VERSION 5.4 ;
NAMESCASESENSITIVE ON ;
BUSBITCHARS "[]" ;
DIVIDERCHAR "/" ;
UNITS
  DATABASE MICRONS 2000 ;
END UNITS
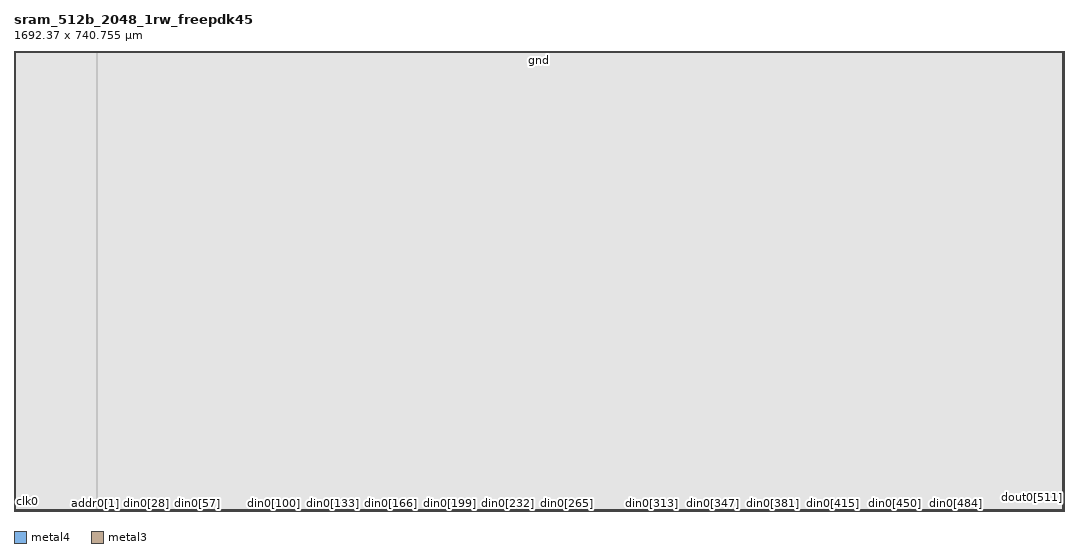
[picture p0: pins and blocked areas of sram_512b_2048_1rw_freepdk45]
MACRO sram_512b_2048_1rw_freepdk45
   CLASS BLOCK ;
   SIZE 1692.37 BY 740.755 ;
   SYMMETRY X Y R90 ;
   PIN din0[0]
      DIRECTION INPUT ;
      PORT
         LAYER metal4 ;
         RECT  133.4175 0.0 133.5575 0.14 ;
      END
   END din0[0]
   PIN din0[1]
      DIRECTION INPUT ;
      PORT
         LAYER metal4 ;
         RECT  136.2775 0.0 136.4175 0.14 ;
      END
   END din0[1]
   PIN din0[2]
      DIRECTION INPUT ;
      PORT
         LAYER metal4 ;
         RECT  139.1375 0.0 139.2775 0.14 ;
      END
   END din0[2]
   PIN din0[3]
      DIRECTION INPUT ;
      PORT
         LAYER metal4 ;
         RECT  141.9975 0.0 142.1375 0.14 ;
      END
   END din0[3]
   PIN din0[4]
      DIRECTION INPUT ;
      PORT
         LAYER metal4 ;
         RECT  144.8575 0.0 144.9975 0.14 ;
      END
   END din0[4]
   PIN din0[5]
      DIRECTION INPUT ;
      PORT
         LAYER metal4 ;
         RECT  147.7175 0.0 147.8575 0.14 ;
      END
   END din0[5]
   PIN din0[6]
      DIRECTION INPUT ;
      PORT
         LAYER metal4 ;
         RECT  150.5775 0.0 150.7175 0.14 ;
      END
   END din0[6]
   PIN din0[7]
      DIRECTION INPUT ;
      PORT
         LAYER metal4 ;
         RECT  153.4375 0.0 153.5775 0.14 ;
      END
   END din0[7]
   PIN din0[8]
      DIRECTION INPUT ;
      PORT
         LAYER metal4 ;
         RECT  156.2975 0.0 156.4375 0.14 ;
      END
   END din0[8]
   PIN din0[9]
      DIRECTION INPUT ;
      PORT
         LAYER metal4 ;
         RECT  159.1575 0.0 159.2975 0.14 ;
      END
   END din0[9]
   PIN din0[10]
      DIRECTION INPUT ;
      PORT
         LAYER metal4 ;
         RECT  162.0175 0.0 162.1575 0.14 ;
      END
   END din0[10]
   PIN din0[11]
      DIRECTION INPUT ;
      PORT
         LAYER metal4 ;
         RECT  164.8775 0.0 165.0175 0.14 ;
      END
   END din0[11]
   PIN din0[12]
      DIRECTION INPUT ;
      PORT
         LAYER metal4 ;
         RECT  167.7375 0.0 167.8775 0.14 ;
      END
   END din0[12]
   PIN din0[13]
      DIRECTION INPUT ;
      PORT
         LAYER metal4 ;
         RECT  170.5975 0.0 170.7375 0.14 ;
      END
   END din0[13]
   PIN din0[14]
      DIRECTION INPUT ;
      PORT
         LAYER metal4 ;
         RECT  173.4575 0.0 173.5975 0.14 ;
      END
   END din0[14]
   PIN din0[15]
      DIRECTION INPUT ;
      PORT
         LAYER metal4 ;
         RECT  176.3175 0.0 176.4575 0.14 ;
      END
   END din0[15]
   PIN din0[16]
      DIRECTION INPUT ;
      PORT
         LAYER metal4 ;
         RECT  179.1775 0.0 179.3175 0.14 ;
      END
   END din0[16]
   PIN din0[17]
      DIRECTION INPUT ;
      PORT
         LAYER metal4 ;
         RECT  182.0375 0.0 182.1775 0.14 ;
      END
   END din0[17]
   PIN din0[18]
      DIRECTION INPUT ;
      PORT
         LAYER metal4 ;
         RECT  184.8975 0.0 185.0375 0.14 ;
      END
   END din0[18]
   PIN din0[19]
      DIRECTION INPUT ;
      PORT
         LAYER metal4 ;
         RECT  187.7575 0.0 187.8975 0.14 ;
      END
   END din0[19]
   PIN din0[20]
      DIRECTION INPUT ;
      PORT
         LAYER metal4 ;
         RECT  190.6175 0.0 190.7575 0.14 ;
      END
   END din0[20]
   PIN din0[21]
      DIRECTION INPUT ;
      PORT
         LAYER metal4 ;
         RECT  193.4775 0.0 193.6175 0.14 ;
      END
   END din0[21]
   PIN din0[22]
      DIRECTION INPUT ;
      PORT
         LAYER metal4 ;
         RECT  196.3375 0.0 196.4775 0.14 ;
      END
   END din0[22]
   PIN din0[23]
      DIRECTION INPUT ;
      PORT
         LAYER metal4 ;
         RECT  199.1975 0.0 199.3375 0.14 ;
      END
   END din0[23]
   PIN din0[24]
      DIRECTION INPUT ;
      PORT
         LAYER metal4 ;
         RECT  202.0575 0.0 202.1975 0.14 ;
      END
   END din0[24]
   PIN din0[25]
      DIRECTION INPUT ;
      PORT
         LAYER metal4 ;
         RECT  204.9175 0.0 205.0575 0.14 ;
      END
   END din0[25]
   PIN din0[26]
      DIRECTION INPUT ;
      PORT
         LAYER metal4 ;
         RECT  207.7775 0.0 207.9175 0.14 ;
      END
   END din0[26]
   PIN din0[27]
      DIRECTION INPUT ;
      PORT
         LAYER metal4 ;
         RECT  210.6375 0.0 210.7775 0.14 ;
      END
   END din0[27]
   PIN din0[28]
      DIRECTION INPUT ;
      PORT
         LAYER metal4 ;
         RECT  213.4975 0.0 213.6375 0.14 ;
      END
   END din0[28]
   PIN din0[29]
      DIRECTION INPUT ;
      PORT
         LAYER metal4 ;
         RECT  216.3575 0.0 216.4975 0.14 ;
      END
   END din0[29]
   PIN din0[30]
      DIRECTION INPUT ;
      PORT
         LAYER metal4 ;
         RECT  219.2175 0.0 219.3575 0.14 ;
      END
   END din0[30]
   PIN din0[31]
      DIRECTION INPUT ;
      PORT
         LAYER metal4 ;
         RECT  222.0775 0.0 222.2175 0.14 ;
      END
   END din0[31]
   PIN din0[32]
      DIRECTION INPUT ;
      PORT
         LAYER metal4 ;
         RECT  224.9375 0.0 225.0775 0.14 ;
      END
   END din0[32]
   PIN din0[33]
      DIRECTION INPUT ;
      PORT
         LAYER metal4 ;
         RECT  227.7975 0.0 227.9375 0.14 ;
      END
   END din0[33]
   PIN din0[34]
      DIRECTION INPUT ;
      PORT
         LAYER metal4 ;
         RECT  230.6575 0.0 230.7975 0.14 ;
      END
   END din0[34]
   PIN din0[35]
      DIRECTION INPUT ;
      PORT
         LAYER metal4 ;
         RECT  233.5175 0.0 233.6575 0.14 ;
      END
   END din0[35]
   PIN din0[36]
      DIRECTION INPUT ;
      PORT
         LAYER metal4 ;
         RECT  236.3775 0.0 236.5175 0.14 ;
      END
   END din0[36]
   PIN din0[37]
      DIRECTION INPUT ;
      PORT
         LAYER metal4 ;
         RECT  239.2375 0.0 239.3775 0.14 ;
      END
   END din0[37]
   PIN din0[38]
      DIRECTION INPUT ;
      PORT
         LAYER metal4 ;
         RECT  242.0975 0.0 242.2375 0.14 ;
      END
   END din0[38]
   PIN din0[39]
      DIRECTION INPUT ;
      PORT
         LAYER metal4 ;
         RECT  244.9575 0.0 245.0975 0.14 ;
      END
   END din0[39]
   PIN din0[40]
      DIRECTION INPUT ;
      PORT
         LAYER metal4 ;
         RECT  247.8175 0.0 247.9575 0.14 ;
      END
   END din0[40]
   PIN din0[41]
      DIRECTION INPUT ;
      PORT
         LAYER metal4 ;
         RECT  250.6775 0.0 250.8175 0.14 ;
      END
   END din0[41]
   PIN din0[42]
      DIRECTION INPUT ;
      PORT
         LAYER metal4 ;
         RECT  253.5375 0.0 253.6775 0.14 ;
      END
   END din0[42]
   PIN din0[43]
      DIRECTION INPUT ;
      PORT
         LAYER metal4 ;
         RECT  256.3975 0.0 256.5375 0.14 ;
      END
   END din0[43]
   PIN din0[44]
      DIRECTION INPUT ;
      PORT
         LAYER metal4 ;
         RECT  259.2575 0.0 259.3975 0.14 ;
      END
   END din0[44]
   PIN din0[45]
      DIRECTION INPUT ;
      PORT
         LAYER metal4 ;
         RECT  262.1175 0.0 262.2575 0.14 ;
      END
   END din0[45]
   PIN din0[46]
      DIRECTION INPUT ;
      PORT
         LAYER metal4 ;
         RECT  264.9775 0.0 265.1175 0.14 ;
      END
   END din0[46]
   PIN din0[47]
      DIRECTION INPUT ;
      PORT
         LAYER metal4 ;
         RECT  267.8375 0.0 267.9775 0.14 ;
      END
   END din0[47]
   PIN din0[48]
      DIRECTION INPUT ;
      PORT
         LAYER metal4 ;
         RECT  270.6975 0.0 270.8375 0.14 ;
      END
   END din0[48]
   PIN din0[49]
      DIRECTION INPUT ;
      PORT
         LAYER metal4 ;
         RECT  273.5575 0.0 273.6975 0.14 ;
      END
   END din0[49]
   PIN din0[50]
      DIRECTION INPUT ;
      PORT
         LAYER metal4 ;
         RECT  276.4175 0.0 276.5575 0.14 ;
      END
   END din0[50]
   PIN din0[51]
      DIRECTION INPUT ;
      PORT
         LAYER metal4 ;
         RECT  279.2775 0.0 279.4175 0.14 ;
      END
   END din0[51]
   PIN din0[52]
      DIRECTION INPUT ;
      PORT
         LAYER metal4 ;
         RECT  282.1375 0.0 282.2775 0.14 ;
      END
   END din0[52]
   PIN din0[53]
      DIRECTION INPUT ;
      PORT
         LAYER metal4 ;
         RECT  284.9975 0.0 285.1375 0.14 ;
      END
   END din0[53]
   PIN din0[54]
      DIRECTION INPUT ;
      PORT
         LAYER metal4 ;
         RECT  287.8575 0.0 287.9975 0.14 ;
      END
   END din0[54]
   PIN din0[55]
      DIRECTION INPUT ;
      PORT
         LAYER metal4 ;
         RECT  290.7175 0.0 290.8575 0.14 ;
      END
   END din0[55]
   PIN din0[56]
      DIRECTION INPUT ;
      PORT
         LAYER metal4 ;
         RECT  293.5775 0.0 293.7175 0.14 ;
      END
   END din0[56]
   PIN din0[57]
      DIRECTION INPUT ;
      PORT
         LAYER metal4 ;
         RECT  296.4375 0.0 296.5775 0.14 ;
      END
   END din0[57]
   PIN din0[58]
      DIRECTION INPUT ;
      PORT
         LAYER metal4 ;
         RECT  299.2975 0.0 299.4375 0.14 ;
      END
   END din0[58]
   PIN din0[59]
      DIRECTION INPUT ;
      PORT
         LAYER metal4 ;
         RECT  302.1575 0.0 302.2975 0.14 ;
      END
   END din0[59]
   PIN din0[60]
      DIRECTION INPUT ;
      PORT
         LAYER metal4 ;
         RECT  305.0175 0.0 305.1575 0.14 ;
      END
   END din0[60]
   PIN din0[61]
      DIRECTION INPUT ;
      PORT
         LAYER metal4 ;
         RECT  307.8775 0.0 308.0175 0.14 ;
      END
   END din0[61]
   PIN din0[62]
      DIRECTION INPUT ;
      PORT
         LAYER metal4 ;
         RECT  310.7375 0.0 310.8775 0.14 ;
      END
   END din0[62]
   PIN din0[63]
      DIRECTION INPUT ;
      PORT
         LAYER metal4 ;
         RECT  313.5975 0.0 313.7375 0.14 ;
      END
   END din0[63]
   PIN din0[64]
      DIRECTION INPUT ;
      PORT
         LAYER metal4 ;
         RECT  316.4575 0.0 316.5975 0.14 ;
      END
   END din0[64]
   PIN din0[65]
      DIRECTION INPUT ;
      PORT
         LAYER metal4 ;
         RECT  319.3175 0.0 319.4575 0.14 ;
      END
   END din0[65]
   PIN din0[66]
      DIRECTION INPUT ;
      PORT
         LAYER metal4 ;
         RECT  322.1775 0.0 322.3175 0.14 ;
      END
   END din0[66]
   PIN din0[67]
      DIRECTION INPUT ;
      PORT
         LAYER metal4 ;
         RECT  325.0375 0.0 325.1775 0.14 ;
      END
   END din0[67]
   PIN din0[68]
      DIRECTION INPUT ;
      PORT
         LAYER metal4 ;
         RECT  327.8975 0.0 328.0375 0.14 ;
      END
   END din0[68]
   PIN din0[69]
      DIRECTION INPUT ;
      PORT
         LAYER metal4 ;
         RECT  330.7575 0.0 330.8975 0.14 ;
      END
   END din0[69]
   PIN din0[70]
      DIRECTION INPUT ;
      PORT
         LAYER metal4 ;
         RECT  333.6175 0.0 333.7575 0.14 ;
      END
   END din0[70]
   PIN din0[71]
      DIRECTION INPUT ;
      PORT
         LAYER metal4 ;
         RECT  336.4775 0.0 336.6175 0.14 ;
      END
   END din0[71]
   PIN din0[72]
      DIRECTION INPUT ;
      PORT
         LAYER metal4 ;
         RECT  339.3375 0.0 339.4775 0.14 ;
      END
   END din0[72]
   PIN din0[73]
      DIRECTION INPUT ;
      PORT
         LAYER metal4 ;
         RECT  342.1975 0.0 342.3375 0.14 ;
      END
   END din0[73]
   PIN din0[74]
      DIRECTION INPUT ;
      PORT
         LAYER metal4 ;
         RECT  345.0575 0.0 345.1975 0.14 ;
      END
   END din0[74]
   PIN din0[75]
      DIRECTION INPUT ;
      PORT
         LAYER metal4 ;
         RECT  347.9175 0.0 348.0575 0.14 ;
      END
   END din0[75]
   PIN din0[76]
      DIRECTION INPUT ;
      PORT
         LAYER metal4 ;
         RECT  350.7775 0.0 350.9175 0.14 ;
      END
   END din0[76]
   PIN din0[77]
      DIRECTION INPUT ;
      PORT
         LAYER metal4 ;
         RECT  353.6375 0.0 353.7775 0.14 ;
      END
   END din0[77]
   PIN din0[78]
      DIRECTION INPUT ;
      PORT
         LAYER metal4 ;
         RECT  356.4975 0.0 356.6375 0.14 ;
      END
   END din0[78]
   PIN din0[79]
      DIRECTION INPUT ;
      PORT
         LAYER metal4 ;
         RECT  359.3575 0.0 359.4975 0.14 ;
      END
   END din0[79]
   PIN din0[80]
      DIRECTION INPUT ;
      PORT
         LAYER metal4 ;
         RECT  362.2175 0.0 362.3575 0.14 ;
      END
   END din0[80]
   PIN din0[81]
      DIRECTION INPUT ;
      PORT
         LAYER metal4 ;
         RECT  365.0775 0.0 365.2175 0.14 ;
      END
   END din0[81]
   PIN din0[82]
      DIRECTION INPUT ;
      PORT
         LAYER metal4 ;
         RECT  367.9375 0.0 368.0775 0.14 ;
      END
   END din0[82]
   PIN din0[83]
      DIRECTION INPUT ;
      PORT
         LAYER metal4 ;
         RECT  370.7975 0.0 370.9375 0.14 ;
      END
   END din0[83]
   PIN din0[84]
      DIRECTION INPUT ;
      PORT
         LAYER metal4 ;
         RECT  373.6575 0.0 373.7975 0.14 ;
      END
   END din0[84]
   PIN din0[85]
      DIRECTION INPUT ;
      PORT
         LAYER metal4 ;
         RECT  376.5175 0.0 376.6575 0.14 ;
      END
   END din0[85]
   PIN din0[86]
      DIRECTION INPUT ;
      PORT
         LAYER metal4 ;
         RECT  379.3775 0.0 379.5175 0.14 ;
      END
   END din0[86]
   PIN din0[87]
      DIRECTION INPUT ;
      PORT
         LAYER metal4 ;
         RECT  382.2375 0.0 382.3775 0.14 ;
      END
   END din0[87]
   PIN din0[88]
      DIRECTION INPUT ;
      PORT
         LAYER metal4 ;
         RECT  385.0975 0.0 385.2375 0.14 ;
      END
   END din0[88]
   PIN din0[89]
      DIRECTION INPUT ;
      PORT
         LAYER metal4 ;
         RECT  387.9575 0.0 388.0975 0.14 ;
      END
   END din0[89]
   PIN din0[90]
      DIRECTION INPUT ;
      PORT
         LAYER metal4 ;
         RECT  390.8175 0.0 390.9575 0.14 ;
      END
   END din0[90]
   PIN din0[91]
      DIRECTION INPUT ;
      PORT
         LAYER metal4 ;
         RECT  393.6775 0.0 393.8175 0.14 ;
      END
   END din0[91]
   PIN din0[92]
      DIRECTION INPUT ;
      PORT
         LAYER metal4 ;
         RECT  396.5375 0.0 396.6775 0.14 ;
      END
   END din0[92]
   PIN din0[93]
      DIRECTION INPUT ;
      PORT
         LAYER metal4 ;
         RECT  399.3975 0.0 399.5375 0.14 ;
      END
   END din0[93]
   PIN din0[94]
      DIRECTION INPUT ;
      PORT
         LAYER metal4 ;
         RECT  402.2575 0.0 402.3975 0.14 ;
      END
   END din0[94]
   PIN din0[95]
      DIRECTION INPUT ;
      PORT
         LAYER metal4 ;
         RECT  405.1175 0.0 405.2575 0.14 ;
      END
   END din0[95]
   PIN din0[96]
      DIRECTION INPUT ;
      PORT
         LAYER metal4 ;
         RECT  407.9775 0.0 408.1175 0.14 ;
      END
   END din0[96]
   PIN din0[97]
      DIRECTION INPUT ;
      PORT
         LAYER metal4 ;
         RECT  410.8375 0.0 410.9775 0.14 ;
      END
   END din0[97]
   PIN din0[98]
      DIRECTION INPUT ;
      PORT
         LAYER metal4 ;
         RECT  413.6975 0.0 413.8375 0.14 ;
      END
   END din0[98]
   PIN din0[99]
      DIRECTION INPUT ;
      PORT
         LAYER metal4 ;
         RECT  416.5575 0.0 416.6975 0.14 ;
      END
   END din0[99]
   PIN din0[100]
      DIRECTION INPUT ;
      PORT
         LAYER metal4 ;
         RECT  419.4175 0.0 419.5575 0.14 ;
      END
   END din0[100]
   PIN din0[101]
      DIRECTION INPUT ;
      PORT
         LAYER metal4 ;
         RECT  422.2775 0.0 422.4175 0.14 ;
      END
   END din0[101]
   PIN din0[102]
      DIRECTION INPUT ;
      PORT
         LAYER metal4 ;
         RECT  425.1375 0.0 425.2775 0.14 ;
      END
   END din0[102]
   PIN din0[103]
      DIRECTION INPUT ;
      PORT
         LAYER metal4 ;
         RECT  427.9975 0.0 428.1375 0.14 ;
      END
   END din0[103]
   PIN din0[104]
      DIRECTION INPUT ;
      PORT
         LAYER metal4 ;
         RECT  430.8575 0.0 430.9975 0.14 ;
      END
   END din0[104]
   PIN din0[105]
      DIRECTION INPUT ;
      PORT
         LAYER metal4 ;
         RECT  433.7175 0.0 433.8575 0.14 ;
      END
   END din0[105]
   PIN din0[106]
      DIRECTION INPUT ;
      PORT
         LAYER metal4 ;
         RECT  436.5775 0.0 436.7175 0.14 ;
      END
   END din0[106]
   PIN din0[107]
      DIRECTION INPUT ;
      PORT
         LAYER metal4 ;
         RECT  439.4375 0.0 439.5775 0.14 ;
      END
   END din0[107]
   PIN din0[108]
      DIRECTION INPUT ;
      PORT
         LAYER metal4 ;
         RECT  442.2975 0.0 442.4375 0.14 ;
      END
   END din0[108]
   PIN din0[109]
      DIRECTION INPUT ;
      PORT
         LAYER metal4 ;
         RECT  445.1575 0.0 445.2975 0.14 ;
      END
   END din0[109]
   PIN din0[110]
      DIRECTION INPUT ;
      PORT
         LAYER metal4 ;
         RECT  448.0175 0.0 448.1575 0.14 ;
      END
   END din0[110]
   PIN din0[111]
      DIRECTION INPUT ;
      PORT
         LAYER metal4 ;
         RECT  450.8775 0.0 451.0175 0.14 ;
      END
   END din0[111]
   PIN din0[112]
      DIRECTION INPUT ;
      PORT
         LAYER metal4 ;
         RECT  453.7375 0.0 453.8775 0.14 ;
      END
   END din0[112]
   PIN din0[113]
      DIRECTION INPUT ;
      PORT
         LAYER metal4 ;
         RECT  456.5975 0.0 456.7375 0.14 ;
      END
   END din0[113]
   PIN din0[114]
      DIRECTION INPUT ;
      PORT
         LAYER metal4 ;
         RECT  459.4575 0.0 459.5975 0.14 ;
      END
   END din0[114]
   PIN din0[115]
      DIRECTION INPUT ;
      PORT
         LAYER metal4 ;
         RECT  462.3175 0.0 462.4575 0.14 ;
      END
   END din0[115]
   PIN din0[116]
      DIRECTION INPUT ;
      PORT
         LAYER metal4 ;
         RECT  465.1775 0.0 465.3175 0.14 ;
      END
   END din0[116]
   PIN din0[117]
      DIRECTION INPUT ;
      PORT
         LAYER metal4 ;
         RECT  468.0375 0.0 468.1775 0.14 ;
      END
   END din0[117]
   PIN din0[118]
      DIRECTION INPUT ;
      PORT
         LAYER metal4 ;
         RECT  470.8975 0.0 471.0375 0.14 ;
      END
   END din0[118]
   PIN din0[119]
      DIRECTION INPUT ;
      PORT
         LAYER metal4 ;
         RECT  473.7575 0.0 473.8975 0.14 ;
      END
   END din0[119]
   PIN din0[120]
      DIRECTION INPUT ;
      PORT
         LAYER metal4 ;
         RECT  476.6175 0.0 476.7575 0.14 ;
      END
   END din0[120]
   PIN din0[121]
      DIRECTION INPUT ;
      PORT
         LAYER metal4 ;
         RECT  479.4775 0.0 479.6175 0.14 ;
      END
   END din0[121]
   PIN din0[122]
      DIRECTION INPUT ;
      PORT
         LAYER metal4 ;
         RECT  482.3375 0.0 482.4775 0.14 ;
      END
   END din0[122]
   PIN din0[123]
      DIRECTION INPUT ;
      PORT
         LAYER metal4 ;
         RECT  485.1975 0.0 485.3375 0.14 ;
      END
   END din0[123]
   PIN din0[124]
      DIRECTION INPUT ;
      PORT
         LAYER metal4 ;
         RECT  488.0575 0.0 488.1975 0.14 ;
      END
   END din0[124]
   PIN din0[125]
      DIRECTION INPUT ;
      PORT
         LAYER metal4 ;
         RECT  490.9175 0.0 491.0575 0.14 ;
      END
   END din0[125]
   PIN din0[126]
      DIRECTION INPUT ;
      PORT
         LAYER metal4 ;
         RECT  493.7775 0.0 493.9175 0.14 ;
      END
   END din0[126]
   PIN din0[127]
      DIRECTION INPUT ;
      PORT
         LAYER metal4 ;
         RECT  496.6375 0.0 496.7775 0.14 ;
      END
   END din0[127]
   PIN din0[128]
      DIRECTION INPUT ;
      PORT
         LAYER metal4 ;
         RECT  499.4975 0.0 499.6375 0.14 ;
      END
   END din0[128]
   PIN din0[129]
      DIRECTION INPUT ;
      PORT
         LAYER metal4 ;
         RECT  502.3575 0.0 502.4975 0.14 ;
      END
   END din0[129]
   PIN din0[130]
      DIRECTION INPUT ;
      PORT
         LAYER metal4 ;
         RECT  505.2175 0.0 505.3575 0.14 ;
      END
   END din0[130]
   PIN din0[131]
      DIRECTION INPUT ;
      PORT
         LAYER metal4 ;
         RECT  508.0775 0.0 508.2175 0.14 ;
      END
   END din0[131]
   PIN din0[132]
      DIRECTION INPUT ;
      PORT
         LAYER metal4 ;
         RECT  510.9375 0.0 511.0775 0.14 ;
      END
   END din0[132]
   PIN din0[133]
      DIRECTION INPUT ;
      PORT
         LAYER metal4 ;
         RECT  513.7975 0.0 513.9375 0.14 ;
      END
   END din0[133]
   PIN din0[134]
      DIRECTION INPUT ;
      PORT
         LAYER metal4 ;
         RECT  516.6575 0.0 516.7975 0.14 ;
      END
   END din0[134]
   PIN din0[135]
      DIRECTION INPUT ;
      PORT
         LAYER metal4 ;
         RECT  519.5175 0.0 519.6575 0.14 ;
      END
   END din0[135]
   PIN din0[136]
      DIRECTION INPUT ;
      PORT
         LAYER metal4 ;
         RECT  522.3775 0.0 522.5175 0.14 ;
      END
   END din0[136]
   PIN din0[137]
      DIRECTION INPUT ;
      PORT
         LAYER metal4 ;
         RECT  525.2375 0.0 525.3775 0.14 ;
      END
   END din0[137]
   PIN din0[138]
      DIRECTION INPUT ;
      PORT
         LAYER metal4 ;
         RECT  528.0975 0.0 528.2375 0.14 ;
      END
   END din0[138]
   PIN din0[139]
      DIRECTION INPUT ;
      PORT
         LAYER metal4 ;
         RECT  530.9575 0.0 531.0975 0.14 ;
      END
   END din0[139]
   PIN din0[140]
      DIRECTION INPUT ;
      PORT
         LAYER metal4 ;
         RECT  533.8175 0.0 533.9575 0.14 ;
      END
   END din0[140]
   PIN din0[141]
      DIRECTION INPUT ;
      PORT
         LAYER metal4 ;
         RECT  536.6775 0.0 536.8175 0.14 ;
      END
   END din0[141]
   PIN din0[142]
      DIRECTION INPUT ;
      PORT
         LAYER metal4 ;
         RECT  539.5375 0.0 539.6775 0.14 ;
      END
   END din0[142]
   PIN din0[143]
      DIRECTION INPUT ;
      PORT
         LAYER metal4 ;
         RECT  542.3975 0.0 542.5375 0.14 ;
      END
   END din0[143]
   PIN din0[144]
      DIRECTION INPUT ;
      PORT
         LAYER metal4 ;
         RECT  545.2575 0.0 545.3975 0.14 ;
      END
   END din0[144]
   PIN din0[145]
      DIRECTION INPUT ;
      PORT
         LAYER metal4 ;
         RECT  548.1175 0.0 548.2575 0.14 ;
      END
   END din0[145]
   PIN din0[146]
      DIRECTION INPUT ;
      PORT
         LAYER metal4 ;
         RECT  550.9775 0.0 551.1175 0.14 ;
      END
   END din0[146]
   PIN din0[147]
      DIRECTION INPUT ;
      PORT
         LAYER metal4 ;
         RECT  553.8375 0.0 553.9775 0.14 ;
      END
   END din0[147]
   PIN din0[148]
      DIRECTION INPUT ;
      PORT
         LAYER metal4 ;
         RECT  556.6975 0.0 556.8375 0.14 ;
      END
   END din0[148]
   PIN din0[149]
      DIRECTION INPUT ;
      PORT
         LAYER metal4 ;
         RECT  559.5575 0.0 559.6975 0.14 ;
      END
   END din0[149]
   PIN din0[150]
      DIRECTION INPUT ;
      PORT
         LAYER metal4 ;
         RECT  562.4175 0.0 562.5575 0.14 ;
      END
   END din0[150]
   PIN din0[151]
      DIRECTION INPUT ;
      PORT
         LAYER metal4 ;
         RECT  565.2775 0.0 565.4175 0.14 ;
      END
   END din0[151]
   PIN din0[152]
      DIRECTION INPUT ;
      PORT
         LAYER metal4 ;
         RECT  568.1375 0.0 568.2775 0.14 ;
      END
   END din0[152]
   PIN din0[153]
      DIRECTION INPUT ;
      PORT
         LAYER metal4 ;
         RECT  570.9975 0.0 571.1375 0.14 ;
      END
   END din0[153]
   PIN din0[154]
      DIRECTION INPUT ;
      PORT
         LAYER metal4 ;
         RECT  573.8575 0.0 573.9975 0.14 ;
      END
   END din0[154]
   PIN din0[155]
      DIRECTION INPUT ;
      PORT
         LAYER metal4 ;
         RECT  576.7175 0.0 576.8575 0.14 ;
      END
   END din0[155]
   PIN din0[156]
      DIRECTION INPUT ;
      PORT
         LAYER metal4 ;
         RECT  579.5775 0.0 579.7175 0.14 ;
      END
   END din0[156]
   PIN din0[157]
      DIRECTION INPUT ;
      PORT
         LAYER metal4 ;
         RECT  582.4375 0.0 582.5775 0.14 ;
      END
   END din0[157]
   PIN din0[158]
      DIRECTION INPUT ;
      PORT
         LAYER metal4 ;
         RECT  585.2975 0.0 585.4375 0.14 ;
      END
   END din0[158]
   PIN din0[159]
      DIRECTION INPUT ;
      PORT
         LAYER metal4 ;
         RECT  588.1575 0.0 588.2975 0.14 ;
      END
   END din0[159]
   PIN din0[160]
      DIRECTION INPUT ;
      PORT
         LAYER metal4 ;
         RECT  591.0175 0.0 591.1575 0.14 ;
      END
   END din0[160]
   PIN din0[161]
      DIRECTION INPUT ;
      PORT
         LAYER metal4 ;
         RECT  593.8775 0.0 594.0175 0.14 ;
      END
   END din0[161]
   PIN din0[162]
      DIRECTION INPUT ;
      PORT
         LAYER metal4 ;
         RECT  596.7375 0.0 596.8775 0.14 ;
      END
   END din0[162]
   PIN din0[163]
      DIRECTION INPUT ;
      PORT
         LAYER metal4 ;
         RECT  599.5975 0.0 599.7375 0.14 ;
      END
   END din0[163]
   PIN din0[164]
      DIRECTION INPUT ;
      PORT
         LAYER metal4 ;
         RECT  602.4575 0.0 602.5975 0.14 ;
      END
   END din0[164]
   PIN din0[165]
      DIRECTION INPUT ;
      PORT
         LAYER metal4 ;
         RECT  605.3175 0.0 605.4575 0.14 ;
      END
   END din0[165]
   PIN din0[166]
      DIRECTION INPUT ;
      PORT
         LAYER metal4 ;
         RECT  608.1775 0.0 608.3175 0.14 ;
      END
   END din0[166]
   PIN din0[167]
      DIRECTION INPUT ;
      PORT
         LAYER metal4 ;
         RECT  611.0375 0.0 611.1775 0.14 ;
      END
   END din0[167]
   PIN din0[168]
      DIRECTION INPUT ;
      PORT
         LAYER metal4 ;
         RECT  613.8975 0.0 614.0375 0.14 ;
      END
   END din0[168]
   PIN din0[169]
      DIRECTION INPUT ;
      PORT
         LAYER metal4 ;
         RECT  616.7575 0.0 616.8975 0.14 ;
      END
   END din0[169]
   PIN din0[170]
      DIRECTION INPUT ;
      PORT
         LAYER metal4 ;
         RECT  619.6175 0.0 619.7575 0.14 ;
      END
   END din0[170]
   PIN din0[171]
      DIRECTION INPUT ;
      PORT
         LAYER metal4 ;
         RECT  622.4775 0.0 622.6175 0.14 ;
      END
   END din0[171]
   PIN din0[172]
      DIRECTION INPUT ;
      PORT
         LAYER metal4 ;
         RECT  625.3375 0.0 625.4775 0.14 ;
      END
   END din0[172]
   PIN din0[173]
      DIRECTION INPUT ;
      PORT
         LAYER metal4 ;
         RECT  628.1975 0.0 628.3375 0.14 ;
      END
   END din0[173]
   PIN din0[174]
      DIRECTION INPUT ;
      PORT
         LAYER metal4 ;
         RECT  631.0575 0.0 631.1975 0.14 ;
      END
   END din0[174]
   PIN din0[175]
      DIRECTION INPUT ;
      PORT
         LAYER metal4 ;
         RECT  633.9175 0.0 634.0575 0.14 ;
      END
   END din0[175]
   PIN din0[176]
      DIRECTION INPUT ;
      PORT
         LAYER metal4 ;
         RECT  636.7775 0.0 636.9175 0.14 ;
      END
   END din0[176]
   PIN din0[177]
      DIRECTION INPUT ;
      PORT
         LAYER metal4 ;
         RECT  639.6375 0.0 639.7775 0.14 ;
      END
   END din0[177]
   PIN din0[178]
      DIRECTION INPUT ;
      PORT
         LAYER metal4 ;
         RECT  642.4975 0.0 642.6375 0.14 ;
      END
   END din0[178]
   PIN din0[179]
      DIRECTION INPUT ;
      PORT
         LAYER metal4 ;
         RECT  645.3575 0.0 645.4975 0.14 ;
      END
   END din0[179]
   PIN din0[180]
      DIRECTION INPUT ;
      PORT
         LAYER metal4 ;
         RECT  648.2175 0.0 648.3575 0.14 ;
      END
   END din0[180]
   PIN din0[181]
      DIRECTION INPUT ;
      PORT
         LAYER metal4 ;
         RECT  651.0775 0.0 651.2175 0.14 ;
      END
   END din0[181]
   PIN din0[182]
      DIRECTION INPUT ;
      PORT
         LAYER metal4 ;
         RECT  653.9375 0.0 654.0775 0.14 ;
      END
   END din0[182]
   PIN din0[183]
      DIRECTION INPUT ;
      PORT
         LAYER metal4 ;
         RECT  656.7975 0.0 656.9375 0.14 ;
      END
   END din0[183]
   PIN din0[184]
      DIRECTION INPUT ;
      PORT
         LAYER metal4 ;
         RECT  659.6575 0.0 659.7975 0.14 ;
      END
   END din0[184]
   PIN din0[185]
      DIRECTION INPUT ;
      PORT
         LAYER metal4 ;
         RECT  662.5175 0.0 662.6575 0.14 ;
      END
   END din0[185]
   PIN din0[186]
      DIRECTION INPUT ;
      PORT
         LAYER metal4 ;
         RECT  665.3775 0.0 665.5175 0.14 ;
      END
   END din0[186]
   PIN din0[187]
      DIRECTION INPUT ;
      PORT
         LAYER metal4 ;
         RECT  668.2375 0.0 668.3775 0.14 ;
      END
   END din0[187]
   PIN din0[188]
      DIRECTION INPUT ;
      PORT
         LAYER metal4 ;
         RECT  671.0975 0.0 671.2375 0.14 ;
      END
   END din0[188]
   PIN din0[189]
      DIRECTION INPUT ;
      PORT
         LAYER metal4 ;
         RECT  673.9575 0.0 674.0975 0.14 ;
      END
   END din0[189]
   PIN din0[190]
      DIRECTION INPUT ;
      PORT
         LAYER metal4 ;
         RECT  676.8175 0.0 676.9575 0.14 ;
      END
   END din0[190]
   PIN din0[191]
      DIRECTION INPUT ;
      PORT
         LAYER metal4 ;
         RECT  679.6775 0.0 679.8175 0.14 ;
      END
   END din0[191]
   PIN din0[192]
      DIRECTION INPUT ;
      PORT
         LAYER metal4 ;
         RECT  682.5375 0.0 682.6775 0.14 ;
      END
   END din0[192]
   PIN din0[193]
      DIRECTION INPUT ;
      PORT
         LAYER metal4 ;
         RECT  685.3975 0.0 685.5375 0.14 ;
      END
   END din0[193]
   PIN din0[194]
      DIRECTION INPUT ;
      PORT
         LAYER metal4 ;
         RECT  688.2575 0.0 688.3975 0.14 ;
      END
   END din0[194]
   PIN din0[195]
      DIRECTION INPUT ;
      PORT
         LAYER metal4 ;
         RECT  691.1175 0.0 691.2575 0.14 ;
      END
   END din0[195]
   PIN din0[196]
      DIRECTION INPUT ;
      PORT
         LAYER metal4 ;
         RECT  693.9775 0.0 694.1175 0.14 ;
      END
   END din0[196]
   PIN din0[197]
      DIRECTION INPUT ;
      PORT
         LAYER metal4 ;
         RECT  696.8375 0.0 696.9775 0.14 ;
      END
   END din0[197]
   PIN din0[198]
      DIRECTION INPUT ;
      PORT
         LAYER metal4 ;
         RECT  699.6975 0.0 699.8375 0.14 ;
      END
   END din0[198]
   PIN din0[199]
      DIRECTION INPUT ;
      PORT
         LAYER metal4 ;
         RECT  702.5575 0.0 702.6975 0.14 ;
      END
   END din0[199]
   PIN din0[200]
      DIRECTION INPUT ;
      PORT
         LAYER metal4 ;
         RECT  705.4175 0.0 705.5575 0.14 ;
      END
   END din0[200]
   PIN din0[201]
      DIRECTION INPUT ;
      PORT
         LAYER metal4 ;
         RECT  708.2775 0.0 708.4175 0.14 ;
      END
   END din0[201]
   PIN din0[202]
      DIRECTION INPUT ;
      PORT
         LAYER metal4 ;
         RECT  711.1375 0.0 711.2775 0.14 ;
      END
   END din0[202]
   PIN din0[203]
      DIRECTION INPUT ;
      PORT
         LAYER metal4 ;
         RECT  713.9975 0.0 714.1375 0.14 ;
      END
   END din0[203]
   PIN din0[204]
      DIRECTION INPUT ;
      PORT
         LAYER metal4 ;
         RECT  716.8575 0.0 716.9975 0.14 ;
      END
   END din0[204]
   PIN din0[205]
      DIRECTION INPUT ;
      PORT
         LAYER metal4 ;
         RECT  719.7175 0.0 719.8575 0.14 ;
      END
   END din0[205]
   PIN din0[206]
      DIRECTION INPUT ;
      PORT
         LAYER metal4 ;
         RECT  722.5775 0.0 722.7175 0.14 ;
      END
   END din0[206]
   PIN din0[207]
      DIRECTION INPUT ;
      PORT
         LAYER metal4 ;
         RECT  725.4375 0.0 725.5775 0.14 ;
      END
   END din0[207]
   PIN din0[208]
      DIRECTION INPUT ;
      PORT
         LAYER metal4 ;
         RECT  728.2975 0.0 728.4375 0.14 ;
      END
   END din0[208]
   PIN din0[209]
      DIRECTION INPUT ;
      PORT
         LAYER metal4 ;
         RECT  731.1575 0.0 731.2975 0.14 ;
      END
   END din0[209]
   PIN din0[210]
      DIRECTION INPUT ;
      PORT
         LAYER metal4 ;
         RECT  734.0175 0.0 734.1575 0.14 ;
      END
   END din0[210]
   PIN din0[211]
      DIRECTION INPUT ;
      PORT
         LAYER metal4 ;
         RECT  736.8775 0.0 737.0175 0.14 ;
      END
   END din0[211]
   PIN din0[212]
      DIRECTION INPUT ;
      PORT
         LAYER metal4 ;
         RECT  739.7375 0.0 739.8775 0.14 ;
      END
   END din0[212]
   PIN din0[213]
      DIRECTION INPUT ;
      PORT
         LAYER metal4 ;
         RECT  742.5975 0.0 742.7375 0.14 ;
      END
   END din0[213]
   PIN din0[214]
      DIRECTION INPUT ;
      PORT
         LAYER metal4 ;
         RECT  745.4575 0.0 745.5975 0.14 ;
      END
   END din0[214]
   PIN din0[215]
      DIRECTION INPUT ;
      PORT
         LAYER metal4 ;
         RECT  748.3175 0.0 748.4575 0.14 ;
      END
   END din0[215]
   PIN din0[216]
      DIRECTION INPUT ;
      PORT
         LAYER metal4 ;
         RECT  751.1775 0.0 751.3175 0.14 ;
      END
   END din0[216]
   PIN din0[217]
      DIRECTION INPUT ;
      PORT
         LAYER metal4 ;
         RECT  754.0375 0.0 754.1775 0.14 ;
      END
   END din0[217]
   PIN din0[218]
      DIRECTION INPUT ;
      PORT
         LAYER metal4 ;
         RECT  756.8975 0.0 757.0375 0.14 ;
      END
   END din0[218]
   PIN din0[219]
      DIRECTION INPUT ;
      PORT
         LAYER metal4 ;
         RECT  759.7575 0.0 759.8975 0.14 ;
      END
   END din0[219]
   PIN din0[220]
      DIRECTION INPUT ;
      PORT
         LAYER metal4 ;
         RECT  762.6175 0.0 762.7575 0.14 ;
      END
   END din0[220]
   PIN din0[221]
      DIRECTION INPUT ;
      PORT
         LAYER metal4 ;
         RECT  765.4775 0.0 765.6175 0.14 ;
      END
   END din0[221]
   PIN din0[222]
      DIRECTION INPUT ;
      PORT
         LAYER metal4 ;
         RECT  768.3375 0.0 768.4775 0.14 ;
      END
   END din0[222]
   PIN din0[223]
      DIRECTION INPUT ;
      PORT
         LAYER metal4 ;
         RECT  771.1975 0.0 771.3375 0.14 ;
      END
   END din0[223]
   PIN din0[224]
      DIRECTION INPUT ;
      PORT
         LAYER metal4 ;
         RECT  774.0575 0.0 774.1975 0.14 ;
      END
   END din0[224]
   PIN din0[225]
      DIRECTION INPUT ;
      PORT
         LAYER metal4 ;
         RECT  776.9175 0.0 777.0575 0.14 ;
      END
   END din0[225]
   PIN din0[226]
      DIRECTION INPUT ;
      PORT
         LAYER metal4 ;
         RECT  779.7775 0.0 779.9175 0.14 ;
      END
   END din0[226]
   PIN din0[227]
      DIRECTION INPUT ;
      PORT
         LAYER metal4 ;
         RECT  782.6375 0.0 782.7775 0.14 ;
      END
   END din0[227]
   PIN din0[228]
      DIRECTION INPUT ;
      PORT
         LAYER metal4 ;
         RECT  785.4975 0.0 785.6375 0.14 ;
      END
   END din0[228]
   PIN din0[229]
      DIRECTION INPUT ;
      PORT
         LAYER metal4 ;
         RECT  788.3575 0.0 788.4975 0.14 ;
      END
   END din0[229]
   PIN din0[230]
      DIRECTION INPUT ;
      PORT
         LAYER metal4 ;
         RECT  791.2175 0.0 791.3575 0.14 ;
      END
   END din0[230]
   PIN din0[231]
      DIRECTION INPUT ;
      PORT
         LAYER metal4 ;
         RECT  794.0775 0.0 794.2175 0.14 ;
      END
   END din0[231]
   PIN din0[232]
      DIRECTION INPUT ;
      PORT
         LAYER metal4 ;
         RECT  796.9375 0.0 797.0775 0.14 ;
      END
   END din0[232]
   PIN din0[233]
      DIRECTION INPUT ;
      PORT
         LAYER metal4 ;
         RECT  799.7975 0.0 799.9375 0.14 ;
      END
   END din0[233]
   PIN din0[234]
      DIRECTION INPUT ;
      PORT
         LAYER metal4 ;
         RECT  802.6575 0.0 802.7975 0.14 ;
      END
   END din0[234]
   PIN din0[235]
      DIRECTION INPUT ;
      PORT
         LAYER metal4 ;
         RECT  805.5175 0.0 805.6575 0.14 ;
      END
   END din0[235]
   PIN din0[236]
      DIRECTION INPUT ;
      PORT
         LAYER metal4 ;
         RECT  808.3775 0.0 808.5175 0.14 ;
      END
   END din0[236]
   PIN din0[237]
      DIRECTION INPUT ;
      PORT
         LAYER metal4 ;
         RECT  811.2375 0.0 811.3775 0.14 ;
      END
   END din0[237]
   PIN din0[238]
      DIRECTION INPUT ;
      PORT
         LAYER metal4 ;
         RECT  814.0975 0.0 814.2375 0.14 ;
      END
   END din0[238]
   PIN din0[239]
      DIRECTION INPUT ;
      PORT
         LAYER metal4 ;
         RECT  816.9575 0.0 817.0975 0.14 ;
      END
   END din0[239]
   PIN din0[240]
      DIRECTION INPUT ;
      PORT
         LAYER metal4 ;
         RECT  819.8175 0.0 819.9575 0.14 ;
      END
   END din0[240]
   PIN din0[241]
      DIRECTION INPUT ;
      PORT
         LAYER metal4 ;
         RECT  822.6775 0.0 822.8175 0.14 ;
      END
   END din0[241]
   PIN din0[242]
      DIRECTION INPUT ;
      PORT
         LAYER metal4 ;
         RECT  825.5375 0.0 825.6775 0.14 ;
      END
   END din0[242]
   PIN din0[243]
      DIRECTION INPUT ;
      PORT
         LAYER metal4 ;
         RECT  828.3975 0.0 828.5375 0.14 ;
      END
   END din0[243]
   PIN din0[244]
      DIRECTION INPUT ;
      PORT
         LAYER metal4 ;
         RECT  831.2575 0.0 831.3975 0.14 ;
      END
   END din0[244]
   PIN din0[245]
      DIRECTION INPUT ;
      PORT
         LAYER metal4 ;
         RECT  834.1175 0.0 834.2575 0.14 ;
      END
   END din0[245]
   PIN din0[246]
      DIRECTION INPUT ;
      PORT
         LAYER metal4 ;
         RECT  836.9775 0.0 837.1175 0.14 ;
      END
   END din0[246]
   PIN din0[247]
      DIRECTION INPUT ;
      PORT
         LAYER metal4 ;
         RECT  839.8375 0.0 839.9775 0.14 ;
      END
   END din0[247]
   PIN din0[248]
      DIRECTION INPUT ;
      PORT
         LAYER metal4 ;
         RECT  842.6975 0.0 842.8375 0.14 ;
      END
   END din0[248]
   PIN din0[249]
      DIRECTION INPUT ;
      PORT
         LAYER metal4 ;
         RECT  845.5575 0.0 845.6975 0.14 ;
      END
   END din0[249]
   PIN din0[250]
      DIRECTION INPUT ;
      PORT
         LAYER metal4 ;
         RECT  848.4175 0.0 848.5575 0.14 ;
      END
   END din0[250]
   PIN din0[251]
      DIRECTION INPUT ;
      PORT
         LAYER metal4 ;
         RECT  851.2775 0.0 851.4175 0.14 ;
      END
   END din0[251]
   PIN din0[252]
      DIRECTION INPUT ;
      PORT
         LAYER metal4 ;
         RECT  854.1375 0.0 854.2775 0.14 ;
      END
   END din0[252]
   PIN din0[253]
      DIRECTION INPUT ;
      PORT
         LAYER metal4 ;
         RECT  856.9975 0.0 857.1375 0.14 ;
      END
   END din0[253]
   PIN din0[254]
      DIRECTION INPUT ;
      PORT
         LAYER metal4 ;
         RECT  859.8575 0.0 859.9975 0.14 ;
      END
   END din0[254]
   PIN din0[255]
      DIRECTION INPUT ;
      PORT
         LAYER metal4 ;
         RECT  862.7175 0.0 862.8575 0.14 ;
      END
   END din0[255]
   PIN din0[256]
      DIRECTION INPUT ;
      PORT
         LAYER metal4 ;
         RECT  865.5775 0.0 865.7175 0.14 ;
      END
   END din0[256]
   PIN din0[257]
      DIRECTION INPUT ;
      PORT
         LAYER metal4 ;
         RECT  868.4375 0.0 868.5775 0.14 ;
      END
   END din0[257]
   PIN din0[258]
      DIRECTION INPUT ;
      PORT
         LAYER metal4 ;
         RECT  871.2975 0.0 871.4375 0.14 ;
      END
   END din0[258]
   PIN din0[259]
      DIRECTION INPUT ;
      PORT
         LAYER metal4 ;
         RECT  874.1575 0.0 874.2975 0.14 ;
      END
   END din0[259]
   PIN din0[260]
      DIRECTION INPUT ;
      PORT
         LAYER metal4 ;
         RECT  877.0175 0.0 877.1575 0.14 ;
      END
   END din0[260]
   PIN din0[261]
      DIRECTION INPUT ;
      PORT
         LAYER metal4 ;
         RECT  879.8775 0.0 880.0175 0.14 ;
      END
   END din0[261]
   PIN din0[262]
      DIRECTION INPUT ;
      PORT
         LAYER metal4 ;
         RECT  882.7375 0.0 882.8775 0.14 ;
      END
   END din0[262]
   PIN din0[263]
      DIRECTION INPUT ;
      PORT
         LAYER metal4 ;
         RECT  885.5975 0.0 885.7375 0.14 ;
      END
   END din0[263]
   PIN din0[264]
      DIRECTION INPUT ;
      PORT
         LAYER metal4 ;
         RECT  888.4575 0.0 888.5975 0.14 ;
      END
   END din0[264]
   PIN din0[265]
      DIRECTION INPUT ;
      PORT
         LAYER metal4 ;
         RECT  891.3175 0.0 891.4575 0.14 ;
      END
   END din0[265]
   PIN din0[266]
      DIRECTION INPUT ;
      PORT
         LAYER metal4 ;
         RECT  894.1775 0.0 894.3175 0.14 ;
      END
   END din0[266]
   PIN din0[267]
      DIRECTION INPUT ;
      PORT
         LAYER metal4 ;
         RECT  897.0375 0.0 897.1775 0.14 ;
      END
   END din0[267]
   PIN din0[268]
      DIRECTION INPUT ;
      PORT
         LAYER metal4 ;
         RECT  899.8975 0.0 900.0375 0.14 ;
      END
   END din0[268]
   PIN din0[269]
      DIRECTION INPUT ;
      PORT
         LAYER metal4 ;
         RECT  902.7575 0.0 902.8975 0.14 ;
      END
   END din0[269]
   PIN din0[270]
      DIRECTION INPUT ;
      PORT
         LAYER metal4 ;
         RECT  905.6175 0.0 905.7575 0.14 ;
      END
   END din0[270]
   PIN din0[271]
      DIRECTION INPUT ;
      PORT
         LAYER metal4 ;
         RECT  908.4775 0.0 908.6175 0.14 ;
      END
   END din0[271]
   PIN din0[272]
      DIRECTION INPUT ;
      PORT
         LAYER metal4 ;
         RECT  911.3375 0.0 911.4775 0.14 ;
      END
   END din0[272]
   PIN din0[273]
      DIRECTION INPUT ;
      PORT
         LAYER metal4 ;
         RECT  914.1975 0.0 914.3375 0.14 ;
      END
   END din0[273]
   PIN din0[274]
      DIRECTION INPUT ;
      PORT
         LAYER metal4 ;
         RECT  917.0575 0.0 917.1975 0.14 ;
      END
   END din0[274]
   PIN din0[275]
      DIRECTION INPUT ;
      PORT
         LAYER metal4 ;
         RECT  919.9175 0.0 920.0575 0.14 ;
      END
   END din0[275]
   PIN din0[276]
      DIRECTION INPUT ;
      PORT
         LAYER metal4 ;
         RECT  922.7775 0.0 922.9175 0.14 ;
      END
   END din0[276]
   PIN din0[277]
      DIRECTION INPUT ;
      PORT
         LAYER metal4 ;
         RECT  925.6375 0.0 925.7775 0.14 ;
      END
   END din0[277]
   PIN din0[278]
      DIRECTION INPUT ;
      PORT
         LAYER metal4 ;
         RECT  928.4975 0.0 928.6375 0.14 ;
      END
   END din0[278]
   PIN din0[279]
      DIRECTION INPUT ;
      PORT
         LAYER metal4 ;
         RECT  931.3575 0.0 931.4975 0.14 ;
      END
   END din0[279]
   PIN din0[280]
      DIRECTION INPUT ;
      PORT
         LAYER metal4 ;
         RECT  934.2175 0.0 934.3575 0.14 ;
      END
   END din0[280]
   PIN din0[281]
      DIRECTION INPUT ;
      PORT
         LAYER metal4 ;
         RECT  937.0775 0.0 937.2175 0.14 ;
      END
   END din0[281]
   PIN din0[282]
      DIRECTION INPUT ;
      PORT
         LAYER metal4 ;
         RECT  939.9375 0.0 940.0775 0.14 ;
      END
   END din0[282]
   PIN din0[283]
      DIRECTION INPUT ;
      PORT
         LAYER metal4 ;
         RECT  942.7975 0.0 942.9375 0.14 ;
      END
   END din0[283]
   PIN din0[284]
      DIRECTION INPUT ;
      PORT
         LAYER metal4 ;
         RECT  945.6575 0.0 945.7975 0.14 ;
      END
   END din0[284]
   PIN din0[285]
      DIRECTION INPUT ;
      PORT
         LAYER metal4 ;
         RECT  948.5175 0.0 948.6575 0.14 ;
      END
   END din0[285]
   PIN din0[286]
      DIRECTION INPUT ;
      PORT
         LAYER metal4 ;
         RECT  951.3775 0.0 951.5175 0.14 ;
      END
   END din0[286]
   PIN din0[287]
      DIRECTION INPUT ;
      PORT
         LAYER metal4 ;
         RECT  954.2375 0.0 954.3775 0.14 ;
      END
   END din0[287]
   PIN din0[288]
      DIRECTION INPUT ;
      PORT
         LAYER metal4 ;
         RECT  957.0975 0.0 957.2375 0.14 ;
      END
   END din0[288]
   PIN din0[289]
      DIRECTION INPUT ;
      PORT
         LAYER metal4 ;
         RECT  959.9575 0.0 960.0975 0.14 ;
      END
   END din0[289]
   PIN din0[290]
      DIRECTION INPUT ;
      PORT
         LAYER metal4 ;
         RECT  962.8175 0.0 962.9575 0.14 ;
      END
   END din0[290]
   PIN din0[291]
      DIRECTION INPUT ;
      PORT
         LAYER metal4 ;
         RECT  965.6775 0.0 965.8175 0.14 ;
      END
   END din0[291]
   PIN din0[292]
      DIRECTION INPUT ;
      PORT
         LAYER metal4 ;
         RECT  968.5375 0.0 968.6775 0.14 ;
      END
   END din0[292]
   PIN din0[293]
      DIRECTION INPUT ;
      PORT
         LAYER metal4 ;
         RECT  971.3975 0.0 971.5375 0.14 ;
      END
   END din0[293]
   PIN din0[294]
      DIRECTION INPUT ;
      PORT
         LAYER metal4 ;
         RECT  974.2575 0.0 974.3975 0.14 ;
      END
   END din0[294]
   PIN din0[295]
      DIRECTION INPUT ;
      PORT
         LAYER metal4 ;
         RECT  977.1175 0.0 977.2575 0.14 ;
      END
   END din0[295]
   PIN din0[296]
      DIRECTION INPUT ;
      PORT
         LAYER metal4 ;
         RECT  979.9775 0.0 980.1175 0.14 ;
      END
   END din0[296]
   PIN din0[297]
      DIRECTION INPUT ;
      PORT
         LAYER metal4 ;
         RECT  982.8375 0.0 982.9775 0.14 ;
      END
   END din0[297]
   PIN din0[298]
      DIRECTION INPUT ;
      PORT
         LAYER metal4 ;
         RECT  985.6975 0.0 985.8375 0.14 ;
      END
   END din0[298]
   PIN din0[299]
      DIRECTION INPUT ;
      PORT
         LAYER metal4 ;
         RECT  988.5575 0.0 988.6975 0.14 ;
      END
   END din0[299]
   PIN din0[300]
      DIRECTION INPUT ;
      PORT
         LAYER metal4 ;
         RECT  991.4175 0.0 991.5575 0.14 ;
      END
   END din0[300]
   PIN din0[301]
      DIRECTION INPUT ;
      PORT
         LAYER metal4 ;
         RECT  994.2775 0.0 994.4175 0.14 ;
      END
   END din0[301]
   PIN din0[302]
      DIRECTION INPUT ;
      PORT
         LAYER metal4 ;
         RECT  997.1375 0.0 997.2775 0.14 ;
      END
   END din0[302]
   PIN din0[303]
      DIRECTION INPUT ;
      PORT
         LAYER metal4 ;
         RECT  999.9975 0.0 1000.1375 0.14 ;
      END
   END din0[303]
   PIN din0[304]
      DIRECTION INPUT ;
      PORT
         LAYER metal4 ;
         RECT  1002.8575 0.0 1002.9975 0.14 ;
      END
   END din0[304]
   PIN din0[305]
      DIRECTION INPUT ;
      PORT
         LAYER metal4 ;
         RECT  1005.7175 0.0 1005.8575 0.14 ;
      END
   END din0[305]
   PIN din0[306]
      DIRECTION INPUT ;
      PORT
         LAYER metal4 ;
         RECT  1008.5775 0.0 1008.7175 0.14 ;
      END
   END din0[306]
   PIN din0[307]
      DIRECTION INPUT ;
      PORT
         LAYER metal4 ;
         RECT  1011.4375 0.0 1011.5775 0.14 ;
      END
   END din0[307]
   PIN din0[308]
      DIRECTION INPUT ;
      PORT
         LAYER metal4 ;
         RECT  1014.2975 0.0 1014.4375 0.14 ;
      END
   END din0[308]
   PIN din0[309]
      DIRECTION INPUT ;
      PORT
         LAYER metal4 ;
         RECT  1017.1575 0.0 1017.2975 0.14 ;
      END
   END din0[309]
   PIN din0[310]
      DIRECTION INPUT ;
      PORT
         LAYER metal4 ;
         RECT  1020.0175 0.0 1020.1575 0.14 ;
      END
   END din0[310]
   PIN din0[311]
      DIRECTION INPUT ;
      PORT
         LAYER metal4 ;
         RECT  1022.8775 0.0 1023.0175 0.14 ;
      END
   END din0[311]
   PIN din0[312]
      DIRECTION INPUT ;
      PORT
         LAYER metal4 ;
         RECT  1025.7375 0.0 1025.8775 0.14 ;
      END
   END din0[312]
   PIN din0[313]
      DIRECTION INPUT ;
      PORT
         LAYER metal4 ;
         RECT  1028.5975 0.0 1028.7375 0.14 ;
      END
   END din0[313]
   PIN din0[314]
      DIRECTION INPUT ;
      PORT
         LAYER metal4 ;
         RECT  1031.4575 0.0 1031.5975 0.14 ;
      END
   END din0[314]
   PIN din0[315]
      DIRECTION INPUT ;
      PORT
         LAYER metal4 ;
         RECT  1034.3175 0.0 1034.4575 0.14 ;
      END
   END din0[315]
   PIN din0[316]
      DIRECTION INPUT ;
      PORT
         LAYER metal4 ;
         RECT  1037.1775 0.0 1037.3175 0.14 ;
      END
   END din0[316]
   PIN din0[317]
      DIRECTION INPUT ;
      PORT
         LAYER metal4 ;
         RECT  1040.0375 0.0 1040.1775 0.14 ;
      END
   END din0[317]
   PIN din0[318]
      DIRECTION INPUT ;
      PORT
         LAYER metal4 ;
         RECT  1042.8975 0.0 1043.0375 0.14 ;
      END
   END din0[318]
   PIN din0[319]
      DIRECTION INPUT ;
      PORT
         LAYER metal4 ;
         RECT  1045.7575 0.0 1045.8975 0.14 ;
      END
   END din0[319]
   PIN din0[320]
      DIRECTION INPUT ;
      PORT
         LAYER metal4 ;
         RECT  1048.6175 0.0 1048.7575 0.14 ;
      END
   END din0[320]
   PIN din0[321]
      DIRECTION INPUT ;
      PORT
         LAYER metal4 ;
         RECT  1051.4775 0.0 1051.6175 0.14 ;
      END
   END din0[321]
   PIN din0[322]
      DIRECTION INPUT ;
      PORT
         LAYER metal4 ;
         RECT  1054.3375 0.0 1054.4775 0.14 ;
      END
   END din0[322]
   PIN din0[323]
      DIRECTION INPUT ;
      PORT
         LAYER metal4 ;
         RECT  1057.1975 0.0 1057.3375 0.14 ;
      END
   END din0[323]
   PIN din0[324]
      DIRECTION INPUT ;
      PORT
         LAYER metal4 ;
         RECT  1060.0575 0.0 1060.1975 0.14 ;
      END
   END din0[324]
   PIN din0[325]
      DIRECTION INPUT ;
      PORT
         LAYER metal4 ;
         RECT  1062.9175 0.0 1063.0575 0.14 ;
      END
   END din0[325]
   PIN din0[326]
      DIRECTION INPUT ;
      PORT
         LAYER metal4 ;
         RECT  1065.7775 0.0 1065.9175 0.14 ;
      END
   END din0[326]
   PIN din0[327]
      DIRECTION INPUT ;
      PORT
         LAYER metal4 ;
         RECT  1068.6375 0.0 1068.7775 0.14 ;
      END
   END din0[327]
   PIN din0[328]
      DIRECTION INPUT ;
      PORT
         LAYER metal4 ;
         RECT  1071.4975 0.0 1071.6375 0.14 ;
      END
   END din0[328]
   PIN din0[329]
      DIRECTION INPUT ;
      PORT
         LAYER metal4 ;
         RECT  1074.3575 0.0 1074.4975 0.14 ;
      END
   END din0[329]
   PIN din0[330]
      DIRECTION INPUT ;
      PORT
         LAYER metal4 ;
         RECT  1077.2175 0.0 1077.3575 0.14 ;
      END
   END din0[330]
   PIN din0[331]
      DIRECTION INPUT ;
      PORT
         LAYER metal4 ;
         RECT  1080.0775 0.0 1080.2175 0.14 ;
      END
   END din0[331]
   PIN din0[332]
      DIRECTION INPUT ;
      PORT
         LAYER metal4 ;
         RECT  1082.9375 0.0 1083.0775 0.14 ;
      END
   END din0[332]
   PIN din0[333]
      DIRECTION INPUT ;
      PORT
         LAYER metal4 ;
         RECT  1085.7975 0.0 1085.9375 0.14 ;
      END
   END din0[333]
   PIN din0[334]
      DIRECTION INPUT ;
      PORT
         LAYER metal4 ;
         RECT  1088.6575 0.0 1088.7975 0.14 ;
      END
   END din0[334]
   PIN din0[335]
      DIRECTION INPUT ;
      PORT
         LAYER metal4 ;
         RECT  1091.5175 0.0 1091.6575 0.14 ;
      END
   END din0[335]
   PIN din0[336]
      DIRECTION INPUT ;
      PORT
         LAYER metal4 ;
         RECT  1094.3775 0.0 1094.5175 0.14 ;
      END
   END din0[336]
   PIN din0[337]
      DIRECTION INPUT ;
      PORT
         LAYER metal4 ;
         RECT  1097.2375 0.0 1097.3775 0.14 ;
      END
   END din0[337]
   PIN din0[338]
      DIRECTION INPUT ;
      PORT
         LAYER metal4 ;
         RECT  1100.0975 0.0 1100.2375 0.14 ;
      END
   END din0[338]
   PIN din0[339]
      DIRECTION INPUT ;
      PORT
         LAYER metal4 ;
         RECT  1102.9575 0.0 1103.0975 0.14 ;
      END
   END din0[339]
   PIN din0[340]
      DIRECTION INPUT ;
      PORT
         LAYER metal4 ;
         RECT  1105.8175 0.0 1105.9575 0.14 ;
      END
   END din0[340]
   PIN din0[341]
      DIRECTION INPUT ;
      PORT
         LAYER metal4 ;
         RECT  1108.6775 0.0 1108.8175 0.14 ;
      END
   END din0[341]
   PIN din0[342]
      DIRECTION INPUT ;
      PORT
         LAYER metal4 ;
         RECT  1111.5375 0.0 1111.6775 0.14 ;
      END
   END din0[342]
   PIN din0[343]
      DIRECTION INPUT ;
      PORT
         LAYER metal4 ;
         RECT  1114.3975 0.0 1114.5375 0.14 ;
      END
   END din0[343]
   PIN din0[344]
      DIRECTION INPUT ;
      PORT
         LAYER metal4 ;
         RECT  1117.2575 0.0 1117.3975 0.14 ;
      END
   END din0[344]
   PIN din0[345]
      DIRECTION INPUT ;
      PORT
         LAYER metal4 ;
         RECT  1120.1175 0.0 1120.2575 0.14 ;
      END
   END din0[345]
   PIN din0[346]
      DIRECTION INPUT ;
      PORT
         LAYER metal4 ;
         RECT  1122.9775 0.0 1123.1175 0.14 ;
      END
   END din0[346]
   PIN din0[347]
      DIRECTION INPUT ;
      PORT
         LAYER metal4 ;
         RECT  1125.8375 0.0 1125.9775 0.14 ;
      END
   END din0[347]
   PIN din0[348]
      DIRECTION INPUT ;
      PORT
         LAYER metal4 ;
         RECT  1128.6975 0.0 1128.8375 0.14 ;
      END
   END din0[348]
   PIN din0[349]
      DIRECTION INPUT ;
      PORT
         LAYER metal4 ;
         RECT  1131.5575 0.0 1131.6975 0.14 ;
      END
   END din0[349]
   PIN din0[350]
      DIRECTION INPUT ;
      PORT
         LAYER metal4 ;
         RECT  1134.4175 0.0 1134.5575 0.14 ;
      END
   END din0[350]
   PIN din0[351]
      DIRECTION INPUT ;
      PORT
         LAYER metal4 ;
         RECT  1137.2775 0.0 1137.4175 0.14 ;
      END
   END din0[351]
   PIN din0[352]
      DIRECTION INPUT ;
      PORT
         LAYER metal4 ;
         RECT  1140.1375 0.0 1140.2775 0.14 ;
      END
   END din0[352]
   PIN din0[353]
      DIRECTION INPUT ;
      PORT
         LAYER metal4 ;
         RECT  1142.9975 0.0 1143.1375 0.14 ;
      END
   END din0[353]
   PIN din0[354]
      DIRECTION INPUT ;
      PORT
         LAYER metal4 ;
         RECT  1145.8575 0.0 1145.9975 0.14 ;
      END
   END din0[354]
   PIN din0[355]
      DIRECTION INPUT ;
      PORT
         LAYER metal4 ;
         RECT  1148.7175 0.0 1148.8575 0.14 ;
      END
   END din0[355]
   PIN din0[356]
      DIRECTION INPUT ;
      PORT
         LAYER metal4 ;
         RECT  1151.5775 0.0 1151.7175 0.14 ;
      END
   END din0[356]
   PIN din0[357]
      DIRECTION INPUT ;
      PORT
         LAYER metal4 ;
         RECT  1154.4375 0.0 1154.5775 0.14 ;
      END
   END din0[357]
   PIN din0[358]
      DIRECTION INPUT ;
      PORT
         LAYER metal4 ;
         RECT  1157.2975 0.0 1157.4375 0.14 ;
      END
   END din0[358]
   PIN din0[359]
      DIRECTION INPUT ;
      PORT
         LAYER metal4 ;
         RECT  1160.1575 0.0 1160.2975 0.14 ;
      END
   END din0[359]
   PIN din0[360]
      DIRECTION INPUT ;
      PORT
         LAYER metal4 ;
         RECT  1163.0175 0.0 1163.1575 0.14 ;
      END
   END din0[360]
   PIN din0[361]
      DIRECTION INPUT ;
      PORT
         LAYER metal4 ;
         RECT  1165.8775 0.0 1166.0175 0.14 ;
      END
   END din0[361]
   PIN din0[362]
      DIRECTION INPUT ;
      PORT
         LAYER metal4 ;
         RECT  1168.7375 0.0 1168.8775 0.14 ;
      END
   END din0[362]
   PIN din0[363]
      DIRECTION INPUT ;
      PORT
         LAYER metal4 ;
         RECT  1171.5975 0.0 1171.7375 0.14 ;
      END
   END din0[363]
   PIN din0[364]
      DIRECTION INPUT ;
      PORT
         LAYER metal4 ;
         RECT  1174.4575 0.0 1174.5975 0.14 ;
      END
   END din0[364]
   PIN din0[365]
      DIRECTION INPUT ;
      PORT
         LAYER metal4 ;
         RECT  1177.3175 0.0 1177.4575 0.14 ;
      END
   END din0[365]
   PIN din0[366]
      DIRECTION INPUT ;
      PORT
         LAYER metal4 ;
         RECT  1180.1775 0.0 1180.3175 0.14 ;
      END
   END din0[366]
   PIN din0[367]
      DIRECTION INPUT ;
      PORT
         LAYER metal4 ;
         RECT  1183.0375 0.0 1183.1775 0.14 ;
      END
   END din0[367]
   PIN din0[368]
      DIRECTION INPUT ;
      PORT
         LAYER metal4 ;
         RECT  1185.8975 0.0 1186.0375 0.14 ;
      END
   END din0[368]
   PIN din0[369]
      DIRECTION INPUT ;
      PORT
         LAYER metal4 ;
         RECT  1188.7575 0.0 1188.8975 0.14 ;
      END
   END din0[369]
   PIN din0[370]
      DIRECTION INPUT ;
      PORT
         LAYER metal4 ;
         RECT  1191.6175 0.0 1191.7575 0.14 ;
      END
   END din0[370]
   PIN din0[371]
      DIRECTION INPUT ;
      PORT
         LAYER metal4 ;
         RECT  1194.4775 0.0 1194.6175 0.14 ;
      END
   END din0[371]
   PIN din0[372]
      DIRECTION INPUT ;
      PORT
         LAYER metal4 ;
         RECT  1197.3375 0.0 1197.4775 0.14 ;
      END
   END din0[372]
   PIN din0[373]
      DIRECTION INPUT ;
      PORT
         LAYER metal4 ;
         RECT  1200.1975 0.0 1200.3375 0.14 ;
      END
   END din0[373]
   PIN din0[374]
      DIRECTION INPUT ;
      PORT
         LAYER metal4 ;
         RECT  1203.0575 0.0 1203.1975 0.14 ;
      END
   END din0[374]
   PIN din0[375]
      DIRECTION INPUT ;
      PORT
         LAYER metal4 ;
         RECT  1205.9175 0.0 1206.0575 0.14 ;
      END
   END din0[375]
   PIN din0[376]
      DIRECTION INPUT ;
      PORT
         LAYER metal4 ;
         RECT  1208.7775 0.0 1208.9175 0.14 ;
      END
   END din0[376]
   PIN din0[377]
      DIRECTION INPUT ;
      PORT
         LAYER metal4 ;
         RECT  1211.6375 0.0 1211.7775 0.14 ;
      END
   END din0[377]
   PIN din0[378]
      DIRECTION INPUT ;
      PORT
         LAYER metal4 ;
         RECT  1214.4975 0.0 1214.6375 0.14 ;
      END
   END din0[378]
   PIN din0[379]
      DIRECTION INPUT ;
      PORT
         LAYER metal4 ;
         RECT  1217.3575 0.0 1217.4975 0.14 ;
      END
   END din0[379]
   PIN din0[380]
      DIRECTION INPUT ;
      PORT
         LAYER metal4 ;
         RECT  1220.2175 0.0 1220.3575 0.14 ;
      END
   END din0[380]
   PIN din0[381]
      DIRECTION INPUT ;
      PORT
         LAYER metal4 ;
         RECT  1223.0775 0.0 1223.2175 0.14 ;
      END
   END din0[381]
   PIN din0[382]
      DIRECTION INPUT ;
      PORT
         LAYER metal4 ;
         RECT  1225.9375 0.0 1226.0775 0.14 ;
      END
   END din0[382]
   PIN din0[383]
      DIRECTION INPUT ;
      PORT
         LAYER metal4 ;
         RECT  1228.7975 0.0 1228.9375 0.14 ;
      END
   END din0[383]
   PIN din0[384]
      DIRECTION INPUT ;
      PORT
         LAYER metal4 ;
         RECT  1231.6575 0.0 1231.7975 0.14 ;
      END
   END din0[384]
   PIN din0[385]
      DIRECTION INPUT ;
      PORT
         LAYER metal4 ;
         RECT  1234.5175 0.0 1234.6575 0.14 ;
      END
   END din0[385]
   PIN din0[386]
      DIRECTION INPUT ;
      PORT
         LAYER metal4 ;
         RECT  1237.3775 0.0 1237.5175 0.14 ;
      END
   END din0[386]
   PIN din0[387]
      DIRECTION INPUT ;
      PORT
         LAYER metal4 ;
         RECT  1240.2375 0.0 1240.3775 0.14 ;
      END
   END din0[387]
   PIN din0[388]
      DIRECTION INPUT ;
      PORT
         LAYER metal4 ;
         RECT  1243.0975 0.0 1243.2375 0.14 ;
      END
   END din0[388]
   PIN din0[389]
      DIRECTION INPUT ;
      PORT
         LAYER metal4 ;
         RECT  1245.9575 0.0 1246.0975 0.14 ;
      END
   END din0[389]
   PIN din0[390]
      DIRECTION INPUT ;
      PORT
         LAYER metal4 ;
         RECT  1248.8175 0.0 1248.9575 0.14 ;
      END
   END din0[390]
   PIN din0[391]
      DIRECTION INPUT ;
      PORT
         LAYER metal4 ;
         RECT  1251.6775 0.0 1251.8175 0.14 ;
      END
   END din0[391]
   PIN din0[392]
      DIRECTION INPUT ;
      PORT
         LAYER metal4 ;
         RECT  1254.5375 0.0 1254.6775 0.14 ;
      END
   END din0[392]
   PIN din0[393]
      DIRECTION INPUT ;
      PORT
         LAYER metal4 ;
         RECT  1257.3975 0.0 1257.5375 0.14 ;
      END
   END din0[393]
   PIN din0[394]
      DIRECTION INPUT ;
      PORT
         LAYER metal4 ;
         RECT  1260.2575 0.0 1260.3975 0.14 ;
      END
   END din0[394]
   PIN din0[395]
      DIRECTION INPUT ;
      PORT
         LAYER metal4 ;
         RECT  1263.1175 0.0 1263.2575 0.14 ;
      END
   END din0[395]
   PIN din0[396]
      DIRECTION INPUT ;
      PORT
         LAYER metal4 ;
         RECT  1265.9775 0.0 1266.1175 0.14 ;
      END
   END din0[396]
   PIN din0[397]
      DIRECTION INPUT ;
      PORT
         LAYER metal4 ;
         RECT  1268.8375 0.0 1268.9775 0.14 ;
      END
   END din0[397]
   PIN din0[398]
      DIRECTION INPUT ;
      PORT
         LAYER metal4 ;
         RECT  1271.6975 0.0 1271.8375 0.14 ;
      END
   END din0[398]
   PIN din0[399]
      DIRECTION INPUT ;
      PORT
         LAYER metal4 ;
         RECT  1274.5575 0.0 1274.6975 0.14 ;
      END
   END din0[399]
   PIN din0[400]
      DIRECTION INPUT ;
      PORT
         LAYER metal4 ;
         RECT  1277.4175 0.0 1277.5575 0.14 ;
      END
   END din0[400]
   PIN din0[401]
      DIRECTION INPUT ;
      PORT
         LAYER metal4 ;
         RECT  1280.2775 0.0 1280.4175 0.14 ;
      END
   END din0[401]
   PIN din0[402]
      DIRECTION INPUT ;
      PORT
         LAYER metal4 ;
         RECT  1283.1375 0.0 1283.2775 0.14 ;
      END
   END din0[402]
   PIN din0[403]
      DIRECTION INPUT ;
      PORT
         LAYER metal4 ;
         RECT  1285.9975 0.0 1286.1375 0.14 ;
      END
   END din0[403]
   PIN din0[404]
      DIRECTION INPUT ;
      PORT
         LAYER metal4 ;
         RECT  1288.8575 0.0 1288.9975 0.14 ;
      END
   END din0[404]
   PIN din0[405]
      DIRECTION INPUT ;
      PORT
         LAYER metal4 ;
         RECT  1291.7175 0.0 1291.8575 0.14 ;
      END
   END din0[405]
   PIN din0[406]
      DIRECTION INPUT ;
      PORT
         LAYER metal4 ;
         RECT  1294.5775 0.0 1294.7175 0.14 ;
      END
   END din0[406]
   PIN din0[407]
      DIRECTION INPUT ;
      PORT
         LAYER metal4 ;
         RECT  1297.4375 0.0 1297.5775 0.14 ;
      END
   END din0[407]
   PIN din0[408]
      DIRECTION INPUT ;
      PORT
         LAYER metal4 ;
         RECT  1300.2975 0.0 1300.4375 0.14 ;
      END
   END din0[408]
   PIN din0[409]
      DIRECTION INPUT ;
      PORT
         LAYER metal4 ;
         RECT  1303.1575 0.0 1303.2975 0.14 ;
      END
   END din0[409]
   PIN din0[410]
      DIRECTION INPUT ;
      PORT
         LAYER metal4 ;
         RECT  1306.0175 0.0 1306.1575 0.14 ;
      END
   END din0[410]
   PIN din0[411]
      DIRECTION INPUT ;
      PORT
         LAYER metal4 ;
         RECT  1308.8775 0.0 1309.0175 0.14 ;
      END
   END din0[411]
   PIN din0[412]
      DIRECTION INPUT ;
      PORT
         LAYER metal4 ;
         RECT  1311.7375 0.0 1311.8775 0.14 ;
      END
   END din0[412]
   PIN din0[413]
      DIRECTION INPUT ;
      PORT
         LAYER metal4 ;
         RECT  1314.5975 0.0 1314.7375 0.14 ;
      END
   END din0[413]
   PIN din0[414]
      DIRECTION INPUT ;
      PORT
         LAYER metal4 ;
         RECT  1317.4575 0.0 1317.5975 0.14 ;
      END
   END din0[414]
   PIN din0[415]
      DIRECTION INPUT ;
      PORT
         LAYER metal4 ;
         RECT  1320.3175 0.0 1320.4575 0.14 ;
      END
   END din0[415]
   PIN din0[416]
      DIRECTION INPUT ;
      PORT
         LAYER metal4 ;
         RECT  1323.1775 0.0 1323.3175 0.14 ;
      END
   END din0[416]
   PIN din0[417]
      DIRECTION INPUT ;
      PORT
         LAYER metal4 ;
         RECT  1326.0375 0.0 1326.1775 0.14 ;
      END
   END din0[417]
   PIN din0[418]
      DIRECTION INPUT ;
      PORT
         LAYER metal4 ;
         RECT  1328.8975 0.0 1329.0375 0.14 ;
      END
   END din0[418]
   PIN din0[419]
      DIRECTION INPUT ;
      PORT
         LAYER metal4 ;
         RECT  1331.7575 0.0 1331.8975 0.14 ;
      END
   END din0[419]
   PIN din0[420]
      DIRECTION INPUT ;
      PORT
         LAYER metal4 ;
         RECT  1334.6175 0.0 1334.7575 0.14 ;
      END
   END din0[420]
   PIN din0[421]
      DIRECTION INPUT ;
      PORT
         LAYER metal4 ;
         RECT  1337.4775 0.0 1337.6175 0.14 ;
      END
   END din0[421]
   PIN din0[422]
      DIRECTION INPUT ;
      PORT
         LAYER metal4 ;
         RECT  1340.3375 0.0 1340.4775 0.14 ;
      END
   END din0[422]
   PIN din0[423]
      DIRECTION INPUT ;
      PORT
         LAYER metal4 ;
         RECT  1343.1975 0.0 1343.3375 0.14 ;
      END
   END din0[423]
   PIN din0[424]
      DIRECTION INPUT ;
      PORT
         LAYER metal4 ;
         RECT  1346.0575 0.0 1346.1975 0.14 ;
      END
   END din0[424]
   PIN din0[425]
      DIRECTION INPUT ;
      PORT
         LAYER metal4 ;
         RECT  1348.9175 0.0 1349.0575 0.14 ;
      END
   END din0[425]
   PIN din0[426]
      DIRECTION INPUT ;
      PORT
         LAYER metal4 ;
         RECT  1351.7775 0.0 1351.9175 0.14 ;
      END
   END din0[426]
   PIN din0[427]
      DIRECTION INPUT ;
      PORT
         LAYER metal4 ;
         RECT  1354.6375 0.0 1354.7775 0.14 ;
      END
   END din0[427]
   PIN din0[428]
      DIRECTION INPUT ;
      PORT
         LAYER metal4 ;
         RECT  1357.4975 0.0 1357.6375 0.14 ;
      END
   END din0[428]
   PIN din0[429]
      DIRECTION INPUT ;
      PORT
         LAYER metal4 ;
         RECT  1360.3575 0.0 1360.4975 0.14 ;
      END
   END din0[429]
   PIN din0[430]
      DIRECTION INPUT ;
      PORT
         LAYER metal4 ;
         RECT  1363.2175 0.0 1363.3575 0.14 ;
      END
   END din0[430]
   PIN din0[431]
      DIRECTION INPUT ;
      PORT
         LAYER metal4 ;
         RECT  1366.0775 0.0 1366.2175 0.14 ;
      END
   END din0[431]
   PIN din0[432]
      DIRECTION INPUT ;
      PORT
         LAYER metal4 ;
         RECT  1368.9375 0.0 1369.0775 0.14 ;
      END
   END din0[432]
   PIN din0[433]
      DIRECTION INPUT ;
      PORT
         LAYER metal4 ;
         RECT  1371.7975 0.0 1371.9375 0.14 ;
      END
   END din0[433]
   PIN din0[434]
      DIRECTION INPUT ;
      PORT
         LAYER metal4 ;
         RECT  1374.6575 0.0 1374.7975 0.14 ;
      END
   END din0[434]
   PIN din0[435]
      DIRECTION INPUT ;
      PORT
         LAYER metal4 ;
         RECT  1377.5175 0.0 1377.6575 0.14 ;
      END
   END din0[435]
   PIN din0[436]
      DIRECTION INPUT ;
      PORT
         LAYER metal4 ;
         RECT  1380.3775 0.0 1380.5175 0.14 ;
      END
   END din0[436]
   PIN din0[437]
      DIRECTION INPUT ;
      PORT
         LAYER metal4 ;
         RECT  1383.2375 0.0 1383.3775 0.14 ;
      END
   END din0[437]
   PIN din0[438]
      DIRECTION INPUT ;
      PORT
         LAYER metal4 ;
         RECT  1386.0975 0.0 1386.2375 0.14 ;
      END
   END din0[438]
   PIN din0[439]
      DIRECTION INPUT ;
      PORT
         LAYER metal4 ;
         RECT  1388.9575 0.0 1389.0975 0.14 ;
      END
   END din0[439]
   PIN din0[440]
      DIRECTION INPUT ;
      PORT
         LAYER metal4 ;
         RECT  1391.8175 0.0 1391.9575 0.14 ;
      END
   END din0[440]
   PIN din0[441]
      DIRECTION INPUT ;
      PORT
         LAYER metal4 ;
         RECT  1394.6775 0.0 1394.8175 0.14 ;
      END
   END din0[441]
   PIN din0[442]
      DIRECTION INPUT ;
      PORT
         LAYER metal4 ;
         RECT  1397.5375 0.0 1397.6775 0.14 ;
      END
   END din0[442]
   PIN din0[443]
      DIRECTION INPUT ;
      PORT
         LAYER metal4 ;
         RECT  1400.3975 0.0 1400.5375 0.14 ;
      END
   END din0[443]
   PIN din0[444]
      DIRECTION INPUT ;
      PORT
         LAYER metal4 ;
         RECT  1403.2575 0.0 1403.3975 0.14 ;
      END
   END din0[444]
   PIN din0[445]
      DIRECTION INPUT ;
      PORT
         LAYER metal4 ;
         RECT  1406.1175 0.0 1406.2575 0.14 ;
      END
   END din0[445]
   PIN din0[446]
      DIRECTION INPUT ;
      PORT
         LAYER metal4 ;
         RECT  1408.9775 0.0 1409.1175 0.14 ;
      END
   END din0[446]
   PIN din0[447]
      DIRECTION INPUT ;
      PORT
         LAYER metal4 ;
         RECT  1411.8375 0.0 1411.9775 0.14 ;
      END
   END din0[447]
   PIN din0[448]
      DIRECTION INPUT ;
      PORT
         LAYER metal4 ;
         RECT  1414.6975 0.0 1414.8375 0.14 ;
      END
   END din0[448]
   PIN din0[449]
      DIRECTION INPUT ;
      PORT
         LAYER metal4 ;
         RECT  1417.5575 0.0 1417.6975 0.14 ;
      END
   END din0[449]
   PIN din0[450]
      DIRECTION INPUT ;
      PORT
         LAYER metal4 ;
         RECT  1420.4175 0.0 1420.5575 0.14 ;
      END
   END din0[450]
   PIN din0[451]
      DIRECTION INPUT ;
      PORT
         LAYER metal4 ;
         RECT  1423.2775 0.0 1423.4175 0.14 ;
      END
   END din0[451]
   PIN din0[452]
      DIRECTION INPUT ;
      PORT
         LAYER metal4 ;
         RECT  1426.1375 0.0 1426.2775 0.14 ;
      END
   END din0[452]
   PIN din0[453]
      DIRECTION INPUT ;
      PORT
         LAYER metal4 ;
         RECT  1428.9975 0.0 1429.1375 0.14 ;
      END
   END din0[453]
   PIN din0[454]
      DIRECTION INPUT ;
      PORT
         LAYER metal4 ;
         RECT  1431.8575 0.0 1431.9975 0.14 ;
      END
   END din0[454]
   PIN din0[455]
      DIRECTION INPUT ;
      PORT
         LAYER metal4 ;
         RECT  1434.7175 0.0 1434.8575 0.14 ;
      END
   END din0[455]
   PIN din0[456]
      DIRECTION INPUT ;
      PORT
         LAYER metal4 ;
         RECT  1437.5775 0.0 1437.7175 0.14 ;
      END
   END din0[456]
   PIN din0[457]
      DIRECTION INPUT ;
      PORT
         LAYER metal4 ;
         RECT  1440.4375 0.0 1440.5775 0.14 ;
      END
   END din0[457]
   PIN din0[458]
      DIRECTION INPUT ;
      PORT
         LAYER metal4 ;
         RECT  1443.2975 0.0 1443.4375 0.14 ;
      END
   END din0[458]
   PIN din0[459]
      DIRECTION INPUT ;
      PORT
         LAYER metal4 ;
         RECT  1446.1575 0.0 1446.2975 0.14 ;
      END
   END din0[459]
   PIN din0[460]
      DIRECTION INPUT ;
      PORT
         LAYER metal4 ;
         RECT  1449.0175 0.0 1449.1575 0.14 ;
      END
   END din0[460]
   PIN din0[461]
      DIRECTION INPUT ;
      PORT
         LAYER metal4 ;
         RECT  1451.8775 0.0 1452.0175 0.14 ;
      END
   END din0[461]
   PIN din0[462]
      DIRECTION INPUT ;
      PORT
         LAYER metal4 ;
         RECT  1454.7375 0.0 1454.8775 0.14 ;
      END
   END din0[462]
   PIN din0[463]
      DIRECTION INPUT ;
      PORT
         LAYER metal4 ;
         RECT  1457.5975 0.0 1457.7375 0.14 ;
      END
   END din0[463]
   PIN din0[464]
      DIRECTION INPUT ;
      PORT
         LAYER metal4 ;
         RECT  1460.4575 0.0 1460.5975 0.14 ;
      END
   END din0[464]
   PIN din0[465]
      DIRECTION INPUT ;
      PORT
         LAYER metal4 ;
         RECT  1463.3175 0.0 1463.4575 0.14 ;
      END
   END din0[465]
   PIN din0[466]
      DIRECTION INPUT ;
      PORT
         LAYER metal4 ;
         RECT  1466.1775 0.0 1466.3175 0.14 ;
      END
   END din0[466]
   PIN din0[467]
      DIRECTION INPUT ;
      PORT
         LAYER metal4 ;
         RECT  1469.0375 0.0 1469.1775 0.14 ;
      END
   END din0[467]
   PIN din0[468]
      DIRECTION INPUT ;
      PORT
         LAYER metal4 ;
         RECT  1471.8975 0.0 1472.0375 0.14 ;
      END
   END din0[468]
   PIN din0[469]
      DIRECTION INPUT ;
      PORT
         LAYER metal4 ;
         RECT  1474.7575 0.0 1474.8975 0.14 ;
      END
   END din0[469]
   PIN din0[470]
      DIRECTION INPUT ;
      PORT
         LAYER metal4 ;
         RECT  1477.6175 0.0 1477.7575 0.14 ;
      END
   END din0[470]
   PIN din0[471]
      DIRECTION INPUT ;
      PORT
         LAYER metal4 ;
         RECT  1480.4775 0.0 1480.6175 0.14 ;
      END
   END din0[471]
   PIN din0[472]
      DIRECTION INPUT ;
      PORT
         LAYER metal4 ;
         RECT  1483.3375 0.0 1483.4775 0.14 ;
      END
   END din0[472]
   PIN din0[473]
      DIRECTION INPUT ;
      PORT
         LAYER metal4 ;
         RECT  1486.1975 0.0 1486.3375 0.14 ;
      END
   END din0[473]
   PIN din0[474]
      DIRECTION INPUT ;
      PORT
         LAYER metal4 ;
         RECT  1489.0575 0.0 1489.1975 0.14 ;
      END
   END din0[474]
   PIN din0[475]
      DIRECTION INPUT ;
      PORT
         LAYER metal4 ;
         RECT  1491.9175 0.0 1492.0575 0.14 ;
      END
   END din0[475]
   PIN din0[476]
      DIRECTION INPUT ;
      PORT
         LAYER metal4 ;
         RECT  1494.7775 0.0 1494.9175 0.14 ;
      END
   END din0[476]
   PIN din0[477]
      DIRECTION INPUT ;
      PORT
         LAYER metal4 ;
         RECT  1497.6375 0.0 1497.7775 0.14 ;
      END
   END din0[477]
   PIN din0[478]
      DIRECTION INPUT ;
      PORT
         LAYER metal4 ;
         RECT  1500.4975 0.0 1500.6375 0.14 ;
      END
   END din0[478]
   PIN din0[479]
      DIRECTION INPUT ;
      PORT
         LAYER metal4 ;
         RECT  1503.3575 0.0 1503.4975 0.14 ;
      END
   END din0[479]
   PIN din0[480]
      DIRECTION INPUT ;
      PORT
         LAYER metal4 ;
         RECT  1506.2175 0.0 1506.3575 0.14 ;
      END
   END din0[480]
   PIN din0[481]
      DIRECTION INPUT ;
      PORT
         LAYER metal4 ;
         RECT  1509.0775 0.0 1509.2175 0.14 ;
      END
   END din0[481]
   PIN din0[482]
      DIRECTION INPUT ;
      PORT
         LAYER metal4 ;
         RECT  1511.9375 0.0 1512.0775 0.14 ;
      END
   END din0[482]
   PIN din0[483]
      DIRECTION INPUT ;
      PORT
         LAYER metal4 ;
         RECT  1514.7975 0.0 1514.9375 0.14 ;
      END
   END din0[483]
   PIN din0[484]
      DIRECTION INPUT ;
      PORT
         LAYER metal4 ;
         RECT  1517.6575 0.0 1517.7975 0.14 ;
      END
   END din0[484]
   PIN din0[485]
      DIRECTION INPUT ;
      PORT
         LAYER metal4 ;
         RECT  1520.5175 0.0 1520.6575 0.14 ;
      END
   END din0[485]
   PIN din0[486]
      DIRECTION INPUT ;
      PORT
         LAYER metal4 ;
         RECT  1523.3775 0.0 1523.5175 0.14 ;
      END
   END din0[486]
   PIN din0[487]
      DIRECTION INPUT ;
      PORT
         LAYER metal4 ;
         RECT  1526.2375 0.0 1526.3775 0.14 ;
      END
   END din0[487]
   PIN din0[488]
      DIRECTION INPUT ;
      PORT
         LAYER metal4 ;
         RECT  1529.0975 0.0 1529.2375 0.14 ;
      END
   END din0[488]
   PIN din0[489]
      DIRECTION INPUT ;
      PORT
         LAYER metal4 ;
         RECT  1531.9575 0.0 1532.0975 0.14 ;
      END
   END din0[489]
   PIN din0[490]
      DIRECTION INPUT ;
      PORT
         LAYER metal4 ;
         RECT  1534.8175 0.0 1534.9575 0.14 ;
      END
   END din0[490]
   PIN din0[491]
      DIRECTION INPUT ;
      PORT
         LAYER metal4 ;
         RECT  1537.6775 0.0 1537.8175 0.14 ;
      END
   END din0[491]
   PIN din0[492]
      DIRECTION INPUT ;
      PORT
         LAYER metal4 ;
         RECT  1540.5375 0.0 1540.6775 0.14 ;
      END
   END din0[492]
   PIN din0[493]
      DIRECTION INPUT ;
      PORT
         LAYER metal4 ;
         RECT  1543.3975 0.0 1543.5375 0.14 ;
      END
   END din0[493]
   PIN din0[494]
      DIRECTION INPUT ;
      PORT
         LAYER metal4 ;
         RECT  1546.2575 0.0 1546.3975 0.14 ;
      END
   END din0[494]
   PIN din0[495]
      DIRECTION INPUT ;
      PORT
         LAYER metal4 ;
         RECT  1549.1175 0.0 1549.2575 0.14 ;
      END
   END din0[495]
   PIN din0[496]
      DIRECTION INPUT ;
      PORT
         LAYER metal4 ;
         RECT  1551.9775 0.0 1552.1175 0.14 ;
      END
   END din0[496]
   PIN din0[497]
      DIRECTION INPUT ;
      PORT
         LAYER metal4 ;
         RECT  1554.8375 0.0 1554.9775 0.14 ;
      END
   END din0[497]
   PIN din0[498]
      DIRECTION INPUT ;
      PORT
         LAYER metal4 ;
         RECT  1557.6975 0.0 1557.8375 0.14 ;
      END
   END din0[498]
   PIN din0[499]
      DIRECTION INPUT ;
      PORT
         LAYER metal4 ;
         RECT  1560.5575 0.0 1560.6975 0.14 ;
      END
   END din0[499]
   PIN din0[500]
      DIRECTION INPUT ;
      PORT
         LAYER metal4 ;
         RECT  1563.4175 0.0 1563.5575 0.14 ;
      END
   END din0[500]
   PIN din0[501]
      DIRECTION INPUT ;
      PORT
         LAYER metal4 ;
         RECT  1566.2775 0.0 1566.4175 0.14 ;
      END
   END din0[501]
   PIN din0[502]
      DIRECTION INPUT ;
      PORT
         LAYER metal4 ;
         RECT  1569.1375 0.0 1569.2775 0.14 ;
      END
   END din0[502]
   PIN din0[503]
      DIRECTION INPUT ;
      PORT
         LAYER metal4 ;
         RECT  1571.9975 0.0 1572.1375 0.14 ;
      END
   END din0[503]
   PIN din0[504]
      DIRECTION INPUT ;
      PORT
         LAYER metal4 ;
         RECT  1574.8575 0.0 1574.9975 0.14 ;
      END
   END din0[504]
   PIN din0[505]
      DIRECTION INPUT ;
      PORT
         LAYER metal4 ;
         RECT  1577.7175 0.0 1577.8575 0.14 ;
      END
   END din0[505]
   PIN din0[506]
      DIRECTION INPUT ;
      PORT
         LAYER metal4 ;
         RECT  1580.5775 0.0 1580.7175 0.14 ;
      END
   END din0[506]
   PIN din0[507]
      DIRECTION INPUT ;
      PORT
         LAYER metal4 ;
         RECT  1583.4375 0.0 1583.5775 0.14 ;
      END
   END din0[507]
   PIN din0[508]
      DIRECTION INPUT ;
      PORT
         LAYER metal4 ;
         RECT  1586.2975 0.0 1586.4375 0.14 ;
      END
   END din0[508]
   PIN din0[509]
      DIRECTION INPUT ;
      PORT
         LAYER metal4 ;
         RECT  1589.1575 0.0 1589.2975 0.14 ;
      END
   END din0[509]
   PIN din0[510]
      DIRECTION INPUT ;
      PORT
         LAYER metal4 ;
         RECT  1592.0175 0.0 1592.1575 0.14 ;
      END
   END din0[510]
   PIN din0[511]
      DIRECTION INPUT ;
      PORT
         LAYER metal4 ;
         RECT  1594.8775 0.0 1595.0175 0.14 ;
      END
   END din0[511]
   PIN addr0[0]
      DIRECTION INPUT ;
      PORT
         LAYER metal4 ;
         RECT  127.6975 0.0 127.8375 0.14 ;
      END
   END addr0[0]
   PIN addr0[1]
      DIRECTION INPUT ;
      PORT
         LAYER metal4 ;
         RECT  130.5575 0.0 130.6975 0.14 ;
      END
   END addr0[1]
   PIN addr0[2]
      DIRECTION INPUT ;
      PORT
         LAYER metal4 ;
         RECT  121.98 0.0 122.12 0.14 ;
      END
   END addr0[2]
   PIN addr0[3]
      DIRECTION INPUT ;
      PORT
         LAYER metal4 ;
         RECT  122.265 0.0 122.405 0.14 ;
      END
   END addr0[3]
   PIN addr0[4]
      DIRECTION INPUT ;
      PORT
         LAYER metal4 ;
         RECT  121.41 0.0 121.55 0.14 ;
      END
   END addr0[4]
   PIN addr0[5]
      DIRECTION INPUT ;
      PORT
         LAYER metal4 ;
         RECT  122.55 0.0 122.69 0.14 ;
      END
   END addr0[5]
   PIN addr0[6]
      DIRECTION INPUT ;
      PORT
         LAYER metal4 ;
         RECT  121.125 0.0 121.265 0.14 ;
      END
   END addr0[6]
   PIN addr0[7]
      DIRECTION INPUT ;
      PORT
         LAYER metal4 ;
         RECT  122.835 0.0 122.975 0.14 ;
      END
   END addr0[7]
   PIN addr0[8]
      DIRECTION INPUT ;
      PORT
         LAYER metal4 ;
         RECT  121.695 0.0 121.835 0.14 ;
      END
   END addr0[8]
   PIN addr0[9]
      DIRECTION INPUT ;
      PORT
         LAYER metal4 ;
         RECT  124.755 0.0 124.895 0.14 ;
      END
   END addr0[9]
   PIN addr0[10]
      DIRECTION INPUT ;
      PORT
         LAYER metal4 ;
         RECT  121.9775 0.0 122.1175 0.14 ;
      END
   END addr0[10]
   PIN csb0
      DIRECTION INPUT ;
      PORT
         LAYER metal3 ;
         RECT  0.0 14.52 0.14 14.66 ;
      END
   END csb0
   PIN web0
      DIRECTION INPUT ;
      PORT
         LAYER metal3 ;
         RECT  0.0 17.25 0.14 17.39 ;
      END
   END web0
   PIN clk0
      DIRECTION INPUT ;
      PORT
         LAYER metal3 ;
         RECT  0.0 14.755 0.14 14.895 ;
      END
   END clk0
   PIN dout0[0]
      DIRECTION OUTPUT ;
      PORT
         LAYER metal4 ;
         RECT  243.9475 0.0 244.0875 0.14 ;
      END
   END dout0[0]
   PIN dout0[1]
      DIRECTION OUTPUT ;
      PORT
         LAYER metal4 ;
         RECT  246.7675 0.0 246.9075 0.14 ;
      END
   END dout0[1]
   PIN dout0[2]
      DIRECTION OUTPUT ;
      PORT
         LAYER metal4 ;
         RECT  249.5875 0.0 249.7275 0.14 ;
      END
   END dout0[2]
   PIN dout0[3]
      DIRECTION OUTPUT ;
      PORT
         LAYER metal4 ;
         RECT  252.4075 0.0 252.5475 0.14 ;
      END
   END dout0[3]
   PIN dout0[4]
      DIRECTION OUTPUT ;
      PORT
         LAYER metal4 ;
         RECT  255.2275 0.0 255.3675 0.14 ;
      END
   END dout0[4]
   PIN dout0[5]
      DIRECTION OUTPUT ;
      PORT
         LAYER metal4 ;
         RECT  258.0475 0.0 258.1875 0.14 ;
      END
   END dout0[5]
   PIN dout0[6]
      DIRECTION OUTPUT ;
      PORT
         LAYER metal4 ;
         RECT  260.8675 0.0 261.0075 0.14 ;
      END
   END dout0[6]
   PIN dout0[7]
      DIRECTION OUTPUT ;
      PORT
         LAYER metal4 ;
         RECT  263.6875 0.0 263.8275 0.14 ;
      END
   END dout0[7]
   PIN dout0[8]
      DIRECTION OUTPUT ;
      PORT
         LAYER metal4 ;
         RECT  266.5075 0.0 266.6475 0.14 ;
      END
   END dout0[8]
   PIN dout0[9]
      DIRECTION OUTPUT ;
      PORT
         LAYER metal4 ;
         RECT  269.3275 0.0 269.4675 0.14 ;
      END
   END dout0[9]
   PIN dout0[10]
      DIRECTION OUTPUT ;
      PORT
         LAYER metal4 ;
         RECT  272.1475 0.0 272.2875 0.14 ;
      END
   END dout0[10]
   PIN dout0[11]
      DIRECTION OUTPUT ;
      PORT
         LAYER metal4 ;
         RECT  274.9675 0.0 275.1075 0.14 ;
      END
   END dout0[11]
   PIN dout0[12]
      DIRECTION OUTPUT ;
      PORT
         LAYER metal4 ;
         RECT  277.7875 0.0 277.9275 0.14 ;
      END
   END dout0[12]
   PIN dout0[13]
      DIRECTION OUTPUT ;
      PORT
         LAYER metal4 ;
         RECT  280.6075 0.0 280.7475 0.14 ;
      END
   END dout0[13]
   PIN dout0[14]
      DIRECTION OUTPUT ;
      PORT
         LAYER metal4 ;
         RECT  283.4275 0.0 283.5675 0.14 ;
      END
   END dout0[14]
   PIN dout0[15]
      DIRECTION OUTPUT ;
      PORT
         LAYER metal4 ;
         RECT  286.2475 0.0 286.3875 0.14 ;
      END
   END dout0[15]
   PIN dout0[16]
      DIRECTION OUTPUT ;
      PORT
         LAYER metal4 ;
         RECT  289.0675 0.0 289.2075 0.14 ;
      END
   END dout0[16]
   PIN dout0[17]
      DIRECTION OUTPUT ;
      PORT
         LAYER metal4 ;
         RECT  291.8875 0.0 292.0275 0.14 ;
      END
   END dout0[17]
   PIN dout0[18]
      DIRECTION OUTPUT ;
      PORT
         LAYER metal4 ;
         RECT  294.7075 0.0 294.8475 0.14 ;
      END
   END dout0[18]
   PIN dout0[19]
      DIRECTION OUTPUT ;
      PORT
         LAYER metal4 ;
         RECT  297.5275 0.0 297.6675 0.14 ;
      END
   END dout0[19]
   PIN dout0[20]
      DIRECTION OUTPUT ;
      PORT
         LAYER metal4 ;
         RECT  300.3475 0.0 300.4875 0.14 ;
      END
   END dout0[20]
   PIN dout0[21]
      DIRECTION OUTPUT ;
      PORT
         LAYER metal4 ;
         RECT  303.1675 0.0 303.3075 0.14 ;
      END
   END dout0[21]
   PIN dout0[22]
      DIRECTION OUTPUT ;
      PORT
         LAYER metal4 ;
         RECT  305.9875 0.0 306.1275 0.14 ;
      END
   END dout0[22]
   PIN dout0[23]
      DIRECTION OUTPUT ;
      PORT
         LAYER metal4 ;
         RECT  308.8075 0.0 308.9475 0.14 ;
      END
   END dout0[23]
   PIN dout0[24]
      DIRECTION OUTPUT ;
      PORT
         LAYER metal4 ;
         RECT  311.6275 0.0 311.7675 0.14 ;
      END
   END dout0[24]
   PIN dout0[25]
      DIRECTION OUTPUT ;
      PORT
         LAYER metal4 ;
         RECT  314.4475 0.0 314.5875 0.14 ;
      END
   END dout0[25]
   PIN dout0[26]
      DIRECTION OUTPUT ;
      PORT
         LAYER metal4 ;
         RECT  317.2675 0.0 317.4075 0.14 ;
      END
   END dout0[26]
   PIN dout0[27]
      DIRECTION OUTPUT ;
      PORT
         LAYER metal4 ;
         RECT  320.0875 0.0 320.2275 0.14 ;
      END
   END dout0[27]
   PIN dout0[28]
      DIRECTION OUTPUT ;
      PORT
         LAYER metal4 ;
         RECT  322.9075 0.0 323.0475 0.14 ;
      END
   END dout0[28]
   PIN dout0[29]
      DIRECTION OUTPUT ;
      PORT
         LAYER metal4 ;
         RECT  325.7275 0.0 325.8675 0.14 ;
      END
   END dout0[29]
   PIN dout0[30]
      DIRECTION OUTPUT ;
      PORT
         LAYER metal4 ;
         RECT  328.5475 0.0 328.6875 0.14 ;
      END
   END dout0[30]
   PIN dout0[31]
      DIRECTION OUTPUT ;
      PORT
         LAYER metal4 ;
         RECT  331.3675 0.0 331.5075 0.14 ;
      END
   END dout0[31]
   PIN dout0[32]
      DIRECTION OUTPUT ;
      PORT
         LAYER metal4 ;
         RECT  334.1875 0.0 334.3275 0.14 ;
      END
   END dout0[32]
   PIN dout0[33]
      DIRECTION OUTPUT ;
      PORT
         LAYER metal4 ;
         RECT  337.0075 0.0 337.1475 0.14 ;
      END
   END dout0[33]
   PIN dout0[34]
      DIRECTION OUTPUT ;
      PORT
         LAYER metal4 ;
         RECT  339.8275 0.0 339.9675 0.14 ;
      END
   END dout0[34]
   PIN dout0[35]
      DIRECTION OUTPUT ;
      PORT
         LAYER metal4 ;
         RECT  342.6475 0.0 342.7875 0.14 ;
      END
   END dout0[35]
   PIN dout0[36]
      DIRECTION OUTPUT ;
      PORT
         LAYER metal4 ;
         RECT  345.4675 0.0 345.6075 0.14 ;
      END
   END dout0[36]
   PIN dout0[37]
      DIRECTION OUTPUT ;
      PORT
         LAYER metal4 ;
         RECT  348.2875 0.0 348.4275 0.14 ;
      END
   END dout0[37]
   PIN dout0[38]
      DIRECTION OUTPUT ;
      PORT
         LAYER metal4 ;
         RECT  351.1075 0.0 351.2475 0.14 ;
      END
   END dout0[38]
   PIN dout0[39]
      DIRECTION OUTPUT ;
      PORT
         LAYER metal4 ;
         RECT  353.9275 0.0 354.0675 0.14 ;
      END
   END dout0[39]
   PIN dout0[40]
      DIRECTION OUTPUT ;
      PORT
         LAYER metal4 ;
         RECT  356.7825 0.0 356.9225 0.14 ;
      END
   END dout0[40]
   PIN dout0[41]
      DIRECTION OUTPUT ;
      PORT
         LAYER metal4 ;
         RECT  359.6425 0.0 359.7825 0.14 ;
      END
   END dout0[41]
   PIN dout0[42]
      DIRECTION OUTPUT ;
      PORT
         LAYER metal4 ;
         RECT  362.5025 0.0 362.6425 0.14 ;
      END
   END dout0[42]
   PIN dout0[43]
      DIRECTION OUTPUT ;
      PORT
         LAYER metal4 ;
         RECT  365.3625 0.0 365.5025 0.14 ;
      END
   END dout0[43]
   PIN dout0[44]
      DIRECTION OUTPUT ;
      PORT
         LAYER metal4 ;
         RECT  368.2225 0.0 368.3625 0.14 ;
      END
   END dout0[44]
   PIN dout0[45]
      DIRECTION OUTPUT ;
      PORT
         LAYER metal4 ;
         RECT  371.0825 0.0 371.2225 0.14 ;
      END
   END dout0[45]
   PIN dout0[46]
      DIRECTION OUTPUT ;
      PORT
         LAYER metal4 ;
         RECT  373.9425 0.0 374.0825 0.14 ;
      END
   END dout0[46]
   PIN dout0[47]
      DIRECTION OUTPUT ;
      PORT
         LAYER metal4 ;
         RECT  376.8025 0.0 376.9425 0.14 ;
      END
   END dout0[47]
   PIN dout0[48]
      DIRECTION OUTPUT ;
      PORT
         LAYER metal4 ;
         RECT  379.6625 0.0 379.8025 0.14 ;
      END
   END dout0[48]
   PIN dout0[49]
      DIRECTION OUTPUT ;
      PORT
         LAYER metal4 ;
         RECT  382.7 0.0 382.84 0.14 ;
      END
   END dout0[49]
   PIN dout0[50]
      DIRECTION OUTPUT ;
      PORT
         LAYER metal4 ;
         RECT  385.52 0.0 385.66 0.14 ;
      END
   END dout0[50]
   PIN dout0[51]
      DIRECTION OUTPUT ;
      PORT
         LAYER metal4 ;
         RECT  387.2 0.0 387.34 0.14 ;
      END
   END dout0[51]
   PIN dout0[52]
      DIRECTION OUTPUT ;
      PORT
         LAYER metal4 ;
         RECT  390.06 0.0 390.2 0.14 ;
      END
   END dout0[52]
   PIN dout0[53]
      DIRECTION OUTPUT ;
      PORT
         LAYER metal4 ;
         RECT  392.92 0.0 393.06 0.14 ;
      END
   END dout0[53]
   PIN dout0[54]
      DIRECTION OUTPUT ;
      PORT
         LAYER metal4 ;
         RECT  395.78 0.0 395.92 0.14 ;
      END
   END dout0[54]
   PIN dout0[55]
      DIRECTION OUTPUT ;
      PORT
         LAYER metal4 ;
         RECT  398.64 0.0 398.78 0.14 ;
      END
   END dout0[55]
   PIN dout0[56]
      DIRECTION OUTPUT ;
      PORT
         LAYER metal4 ;
         RECT  401.5 0.0 401.64 0.14 ;
      END
   END dout0[56]
   PIN dout0[57]
      DIRECTION OUTPUT ;
      PORT
         LAYER metal4 ;
         RECT  404.36 0.0 404.5 0.14 ;
      END
   END dout0[57]
   PIN dout0[58]
      DIRECTION OUTPUT ;
      PORT
         LAYER metal4 ;
         RECT  407.22 0.0 407.36 0.14 ;
      END
   END dout0[58]
   PIN dout0[59]
      DIRECTION OUTPUT ;
      PORT
         LAYER metal4 ;
         RECT  410.08 0.0 410.22 0.14 ;
      END
   END dout0[59]
   PIN dout0[60]
      DIRECTION OUTPUT ;
      PORT
         LAYER metal4 ;
         RECT  412.9125 0.0 413.0525 0.14 ;
      END
   END dout0[60]
   PIN dout0[61]
      DIRECTION OUTPUT ;
      PORT
         LAYER metal4 ;
         RECT  415.7325 0.0 415.8725 0.14 ;
      END
   END dout0[61]
   PIN dout0[62]
      DIRECTION OUTPUT ;
      PORT
         LAYER metal4 ;
         RECT  418.66 0.0 418.8 0.14 ;
      END
   END dout0[62]
   PIN dout0[63]
      DIRECTION OUTPUT ;
      PORT
         LAYER metal4 ;
         RECT  421.52 0.0 421.66 0.14 ;
      END
   END dout0[63]
   PIN dout0[64]
      DIRECTION OUTPUT ;
      PORT
         LAYER metal4 ;
         RECT  424.38 0.0 424.52 0.14 ;
      END
   END dout0[64]
   PIN dout0[65]
      DIRECTION OUTPUT ;
      PORT
         LAYER metal4 ;
         RECT  427.24 0.0 427.38 0.14 ;
      END
   END dout0[65]
   PIN dout0[66]
      DIRECTION OUTPUT ;
      PORT
         LAYER metal4 ;
         RECT  430.0675 0.0 430.2075 0.14 ;
      END
   END dout0[66]
   PIN dout0[67]
      DIRECTION OUTPUT ;
      PORT
         LAYER metal4 ;
         RECT  432.8875 0.0 433.0275 0.14 ;
      END
   END dout0[67]
   PIN dout0[68]
      DIRECTION OUTPUT ;
      PORT
         LAYER metal4 ;
         RECT  435.7075 0.0 435.8475 0.14 ;
      END
   END dout0[68]
   PIN dout0[69]
      DIRECTION OUTPUT ;
      PORT
         LAYER metal4 ;
         RECT  438.5275 0.0 438.6675 0.14 ;
      END
   END dout0[69]
   PIN dout0[70]
      DIRECTION OUTPUT ;
      PORT
         LAYER metal4 ;
         RECT  441.3475 0.0 441.4875 0.14 ;
      END
   END dout0[70]
   PIN dout0[71]
      DIRECTION OUTPUT ;
      PORT
         LAYER metal4 ;
         RECT  444.1675 0.0 444.3075 0.14 ;
      END
   END dout0[71]
   PIN dout0[72]
      DIRECTION OUTPUT ;
      PORT
         LAYER metal4 ;
         RECT  446.9875 0.0 447.1275 0.14 ;
      END
   END dout0[72]
   PIN dout0[73]
      DIRECTION OUTPUT ;
      PORT
         LAYER metal4 ;
         RECT  449.8075 0.0 449.9475 0.14 ;
      END
   END dout0[73]
   PIN dout0[74]
      DIRECTION OUTPUT ;
      PORT
         LAYER metal4 ;
         RECT  452.6275 0.0 452.7675 0.14 ;
      END
   END dout0[74]
   PIN dout0[75]
      DIRECTION OUTPUT ;
      PORT
         LAYER metal4 ;
         RECT  455.4475 0.0 455.5875 0.14 ;
      END
   END dout0[75]
   PIN dout0[76]
      DIRECTION OUTPUT ;
      PORT
         LAYER metal4 ;
         RECT  458.2675 0.0 458.4075 0.14 ;
      END
   END dout0[76]
   PIN dout0[77]
      DIRECTION OUTPUT ;
      PORT
         LAYER metal4 ;
         RECT  461.0875 0.0 461.2275 0.14 ;
      END
   END dout0[77]
   PIN dout0[78]
      DIRECTION OUTPUT ;
      PORT
         LAYER metal4 ;
         RECT  463.9075 0.0 464.0475 0.14 ;
      END
   END dout0[78]
   PIN dout0[79]
      DIRECTION OUTPUT ;
      PORT
         LAYER metal4 ;
         RECT  466.7275 0.0 466.8675 0.14 ;
      END
   END dout0[79]
   PIN dout0[80]
      DIRECTION OUTPUT ;
      PORT
         LAYER metal4 ;
         RECT  469.5475 0.0 469.6875 0.14 ;
      END
   END dout0[80]
   PIN dout0[81]
      DIRECTION OUTPUT ;
      PORT
         LAYER metal4 ;
         RECT  472.3675 0.0 472.5075 0.14 ;
      END
   END dout0[81]
   PIN dout0[82]
      DIRECTION OUTPUT ;
      PORT
         LAYER metal4 ;
         RECT  475.1875 0.0 475.3275 0.14 ;
      END
   END dout0[82]
   PIN dout0[83]
      DIRECTION OUTPUT ;
      PORT
         LAYER metal4 ;
         RECT  478.0075 0.0 478.1475 0.14 ;
      END
   END dout0[83]
   PIN dout0[84]
      DIRECTION OUTPUT ;
      PORT
         LAYER metal4 ;
         RECT  480.8275 0.0 480.9675 0.14 ;
      END
   END dout0[84]
   PIN dout0[85]
      DIRECTION OUTPUT ;
      PORT
         LAYER metal4 ;
         RECT  483.6475 0.0 483.7875 0.14 ;
      END
   END dout0[85]
   PIN dout0[86]
      DIRECTION OUTPUT ;
      PORT
         LAYER metal4 ;
         RECT  486.4675 0.0 486.6075 0.14 ;
      END
   END dout0[86]
   PIN dout0[87]
      DIRECTION OUTPUT ;
      PORT
         LAYER metal4 ;
         RECT  489.2875 0.0 489.4275 0.14 ;
      END
   END dout0[87]
   PIN dout0[88]
      DIRECTION OUTPUT ;
      PORT
         LAYER metal4 ;
         RECT  492.1075 0.0 492.2475 0.14 ;
      END
   END dout0[88]
   PIN dout0[89]
      DIRECTION OUTPUT ;
      PORT
         LAYER metal4 ;
         RECT  494.9275 0.0 495.0675 0.14 ;
      END
   END dout0[89]
   PIN dout0[90]
      DIRECTION OUTPUT ;
      PORT
         LAYER metal4 ;
         RECT  497.7475 0.0 497.8875 0.14 ;
      END
   END dout0[90]
   PIN dout0[91]
      DIRECTION OUTPUT ;
      PORT
         LAYER metal4 ;
         RECT  500.5675 0.0 500.7075 0.14 ;
      END
   END dout0[91]
   PIN dout0[92]
      DIRECTION OUTPUT ;
      PORT
         LAYER metal4 ;
         RECT  503.3875 0.0 503.5275 0.14 ;
      END
   END dout0[92]
   PIN dout0[93]
      DIRECTION OUTPUT ;
      PORT
         LAYER metal4 ;
         RECT  506.2075 0.0 506.3475 0.14 ;
      END
   END dout0[93]
   PIN dout0[94]
      DIRECTION OUTPUT ;
      PORT
         LAYER metal4 ;
         RECT  509.0275 0.0 509.1675 0.14 ;
      END
   END dout0[94]
   PIN dout0[95]
      DIRECTION OUTPUT ;
      PORT
         LAYER metal4 ;
         RECT  511.8475 0.0 511.9875 0.14 ;
      END
   END dout0[95]
   PIN dout0[96]
      DIRECTION OUTPUT ;
      PORT
         LAYER metal4 ;
         RECT  514.6675 0.0 514.8075 0.14 ;
      END
   END dout0[96]
   PIN dout0[97]
      DIRECTION OUTPUT ;
      PORT
         LAYER metal4 ;
         RECT  517.4875 0.0 517.6275 0.14 ;
      END
   END dout0[97]
   PIN dout0[98]
      DIRECTION OUTPUT ;
      PORT
         LAYER metal4 ;
         RECT  520.3075 0.0 520.4475 0.14 ;
      END
   END dout0[98]
   PIN dout0[99]
      DIRECTION OUTPUT ;
      PORT
         LAYER metal4 ;
         RECT  523.1275 0.0 523.2675 0.14 ;
      END
   END dout0[99]
   PIN dout0[100]
      DIRECTION OUTPUT ;
      PORT
         LAYER metal4 ;
         RECT  525.9475 0.0 526.0875 0.14 ;
      END
   END dout0[100]
   PIN dout0[101]
      DIRECTION OUTPUT ;
      PORT
         LAYER metal4 ;
         RECT  528.7675 0.0 528.9075 0.14 ;
      END
   END dout0[101]
   PIN dout0[102]
      DIRECTION OUTPUT ;
      PORT
         LAYER metal4 ;
         RECT  531.5875 0.0 531.7275 0.14 ;
      END
   END dout0[102]
   PIN dout0[103]
      DIRECTION OUTPUT ;
      PORT
         LAYER metal4 ;
         RECT  534.4075 0.0 534.5475 0.14 ;
      END
   END dout0[103]
   PIN dout0[104]
      DIRECTION OUTPUT ;
      PORT
         LAYER metal4 ;
         RECT  537.2275 0.0 537.3675 0.14 ;
      END
   END dout0[104]
   PIN dout0[105]
      DIRECTION OUTPUT ;
      PORT
         LAYER metal4 ;
         RECT  540.0475 0.0 540.1875 0.14 ;
      END
   END dout0[105]
   PIN dout0[106]
      DIRECTION OUTPUT ;
      PORT
         LAYER metal4 ;
         RECT  542.8675 0.0 543.0075 0.14 ;
      END
   END dout0[106]
   PIN dout0[107]
      DIRECTION OUTPUT ;
      PORT
         LAYER metal4 ;
         RECT  545.6875 0.0 545.8275 0.14 ;
      END
   END dout0[107]
   PIN dout0[108]
      DIRECTION OUTPUT ;
      PORT
         LAYER metal4 ;
         RECT  548.5075 0.0 548.6475 0.14 ;
      END
   END dout0[108]
   PIN dout0[109]
      DIRECTION OUTPUT ;
      PORT
         LAYER metal4 ;
         RECT  551.3275 0.0 551.4675 0.14 ;
      END
   END dout0[109]
   PIN dout0[110]
      DIRECTION OUTPUT ;
      PORT
         LAYER metal4 ;
         RECT  554.1475 0.0 554.2875 0.14 ;
      END
   END dout0[110]
   PIN dout0[111]
      DIRECTION OUTPUT ;
      PORT
         LAYER metal4 ;
         RECT  556.9825 0.0 557.1225 0.14 ;
      END
   END dout0[111]
   PIN dout0[112]
      DIRECTION OUTPUT ;
      PORT
         LAYER metal4 ;
         RECT  559.86 0.0 560.0 0.14 ;
      END
   END dout0[112]
   PIN dout0[113]
      DIRECTION OUTPUT ;
      PORT
         LAYER metal4 ;
         RECT  562.7025 0.0 562.8425 0.14 ;
      END
   END dout0[113]
   PIN dout0[114]
      DIRECTION OUTPUT ;
      PORT
         LAYER metal4 ;
         RECT  565.5625 0.0 565.7025 0.14 ;
      END
   END dout0[114]
   PIN dout0[115]
      DIRECTION OUTPUT ;
      PORT
         LAYER metal4 ;
         RECT  568.4225 0.0 568.5625 0.14 ;
      END
   END dout0[115]
   PIN dout0[116]
      DIRECTION OUTPUT ;
      PORT
         LAYER metal4 ;
         RECT  571.2825 0.0 571.4225 0.14 ;
      END
   END dout0[116]
   PIN dout0[117]
      DIRECTION OUTPUT ;
      PORT
         LAYER metal4 ;
         RECT  574.1425 0.0 574.2825 0.14 ;
      END
   END dout0[117]
   PIN dout0[118]
      DIRECTION OUTPUT ;
      PORT
         LAYER metal4 ;
         RECT  577.0025 0.0 577.1425 0.14 ;
      END
   END dout0[118]
   PIN dout0[119]
      DIRECTION OUTPUT ;
      PORT
         LAYER metal4 ;
         RECT  579.8625 0.0 580.0025 0.14 ;
      END
   END dout0[119]
   PIN dout0[120]
      DIRECTION OUTPUT ;
      PORT
         LAYER metal4 ;
         RECT  582.92 0.0 583.06 0.14 ;
      END
   END dout0[120]
   PIN dout0[121]
      DIRECTION OUTPUT ;
      PORT
         LAYER metal4 ;
         RECT  585.74 0.0 585.88 0.14 ;
      END
   END dout0[121]
   PIN dout0[122]
      DIRECTION OUTPUT ;
      PORT
         LAYER metal4 ;
         RECT  588.56 0.0 588.7 0.14 ;
      END
   END dout0[122]
   PIN dout0[123]
      DIRECTION OUTPUT ;
      PORT
         LAYER metal4 ;
         RECT  590.26 0.0 590.4 0.14 ;
      END
   END dout0[123]
   PIN dout0[124]
      DIRECTION OUTPUT ;
      PORT
         LAYER metal4 ;
         RECT  593.12 0.0 593.26 0.14 ;
      END
   END dout0[124]
   PIN dout0[125]
      DIRECTION OUTPUT ;
      PORT
         LAYER metal4 ;
         RECT  595.98 0.0 596.12 0.14 ;
      END
   END dout0[125]
   PIN dout0[126]
      DIRECTION OUTPUT ;
      PORT
         LAYER metal4 ;
         RECT  598.84 0.0 598.98 0.14 ;
      END
   END dout0[126]
   PIN dout0[127]
      DIRECTION OUTPUT ;
      PORT
         LAYER metal4 ;
         RECT  601.7 0.0 601.84 0.14 ;
      END
   END dout0[127]
   PIN dout0[128]
      DIRECTION OUTPUT ;
      PORT
         LAYER metal4 ;
         RECT  604.56 0.0 604.7 0.14 ;
      END
   END dout0[128]
   PIN dout0[129]
      DIRECTION OUTPUT ;
      PORT
         LAYER metal4 ;
         RECT  607.42 0.0 607.56 0.14 ;
      END
   END dout0[129]
   PIN dout0[130]
      DIRECTION OUTPUT ;
      PORT
         LAYER metal4 ;
         RECT  610.28 0.0 610.42 0.14 ;
      END
   END dout0[130]
   PIN dout0[131]
      DIRECTION OUTPUT ;
      PORT
         LAYER metal4 ;
         RECT  613.1325 0.0 613.2725 0.14 ;
      END
   END dout0[131]
   PIN dout0[132]
      DIRECTION OUTPUT ;
      PORT
         LAYER metal4 ;
         RECT  615.9525 0.0 616.0925 0.14 ;
      END
   END dout0[132]
   PIN dout0[133]
      DIRECTION OUTPUT ;
      PORT
         LAYER metal4 ;
         RECT  618.7725 0.0 618.9125 0.14 ;
      END
   END dout0[133]
   PIN dout0[134]
      DIRECTION OUTPUT ;
      PORT
         LAYER metal4 ;
         RECT  621.72 0.0 621.86 0.14 ;
      END
   END dout0[134]
   PIN dout0[135]
      DIRECTION OUTPUT ;
      PORT
         LAYER metal4 ;
         RECT  624.58 0.0 624.72 0.14 ;
      END
   END dout0[135]
   PIN dout0[136]
      DIRECTION OUTPUT ;
      PORT
         LAYER metal4 ;
         RECT  627.44 0.0 627.58 0.14 ;
      END
   END dout0[136]
   PIN dout0[137]
      DIRECTION OUTPUT ;
      PORT
         LAYER metal4 ;
         RECT  630.2875 0.0 630.4275 0.14 ;
      END
   END dout0[137]
   PIN dout0[138]
      DIRECTION OUTPUT ;
      PORT
         LAYER metal4 ;
         RECT  633.1075 0.0 633.2475 0.14 ;
      END
   END dout0[138]
   PIN dout0[139]
      DIRECTION OUTPUT ;
      PORT
         LAYER metal4 ;
         RECT  635.9275 0.0 636.0675 0.14 ;
      END
   END dout0[139]
   PIN dout0[140]
      DIRECTION OUTPUT ;
      PORT
         LAYER metal4 ;
         RECT  638.7475 0.0 638.8875 0.14 ;
      END
   END dout0[140]
   PIN dout0[141]
      DIRECTION OUTPUT ;
      PORT
         LAYER metal4 ;
         RECT  641.5675 0.0 641.7075 0.14 ;
      END
   END dout0[141]
   PIN dout0[142]
      DIRECTION OUTPUT ;
      PORT
         LAYER metal4 ;
         RECT  644.3875 0.0 644.5275 0.14 ;
      END
   END dout0[142]
   PIN dout0[143]
      DIRECTION OUTPUT ;
      PORT
         LAYER metal4 ;
         RECT  647.2075 0.0 647.3475 0.14 ;
      END
   END dout0[143]
   PIN dout0[144]
      DIRECTION OUTPUT ;
      PORT
         LAYER metal4 ;
         RECT  650.0275 0.0 650.1675 0.14 ;
      END
   END dout0[144]
   PIN dout0[145]
      DIRECTION OUTPUT ;
      PORT
         LAYER metal4 ;
         RECT  652.8475 0.0 652.9875 0.14 ;
      END
   END dout0[145]
   PIN dout0[146]
      DIRECTION OUTPUT ;
      PORT
         LAYER metal4 ;
         RECT  655.6675 0.0 655.8075 0.14 ;
      END
   END dout0[146]
   PIN dout0[147]
      DIRECTION OUTPUT ;
      PORT
         LAYER metal4 ;
         RECT  658.4875 0.0 658.6275 0.14 ;
      END
   END dout0[147]
   PIN dout0[148]
      DIRECTION OUTPUT ;
      PORT
         LAYER metal4 ;
         RECT  661.3075 0.0 661.4475 0.14 ;
      END
   END dout0[148]
   PIN dout0[149]
      DIRECTION OUTPUT ;
      PORT
         LAYER metal4 ;
         RECT  664.1275 0.0 664.2675 0.14 ;
      END
   END dout0[149]
   PIN dout0[150]
      DIRECTION OUTPUT ;
      PORT
         LAYER metal4 ;
         RECT  666.9475 0.0 667.0875 0.14 ;
      END
   END dout0[150]
   PIN dout0[151]
      DIRECTION OUTPUT ;
      PORT
         LAYER metal4 ;
         RECT  669.7675 0.0 669.9075 0.14 ;
      END
   END dout0[151]
   PIN dout0[152]
      DIRECTION OUTPUT ;
      PORT
         LAYER metal4 ;
         RECT  672.5875 0.0 672.7275 0.14 ;
      END
   END dout0[152]
   PIN dout0[153]
      DIRECTION OUTPUT ;
      PORT
         LAYER metal4 ;
         RECT  675.4075 0.0 675.5475 0.14 ;
      END
   END dout0[153]
   PIN dout0[154]
      DIRECTION OUTPUT ;
      PORT
         LAYER metal4 ;
         RECT  678.2275 0.0 678.3675 0.14 ;
      END
   END dout0[154]
   PIN dout0[155]
      DIRECTION OUTPUT ;
      PORT
         LAYER metal4 ;
         RECT  681.0475 0.0 681.1875 0.14 ;
      END
   END dout0[155]
   PIN dout0[156]
      DIRECTION OUTPUT ;
      PORT
         LAYER metal4 ;
         RECT  683.8675 0.0 684.0075 0.14 ;
      END
   END dout0[156]
   PIN dout0[157]
      DIRECTION OUTPUT ;
      PORT
         LAYER metal4 ;
         RECT  686.6875 0.0 686.8275 0.14 ;
      END
   END dout0[157]
   PIN dout0[158]
      DIRECTION OUTPUT ;
      PORT
         LAYER metal4 ;
         RECT  689.5075 0.0 689.6475 0.14 ;
      END
   END dout0[158]
   PIN dout0[159]
      DIRECTION OUTPUT ;
      PORT
         LAYER metal4 ;
         RECT  692.3275 0.0 692.4675 0.14 ;
      END
   END dout0[159]
   PIN dout0[160]
      DIRECTION OUTPUT ;
      PORT
         LAYER metal4 ;
         RECT  695.1475 0.0 695.2875 0.14 ;
      END
   END dout0[160]
   PIN dout0[161]
      DIRECTION OUTPUT ;
      PORT
         LAYER metal4 ;
         RECT  697.9675 0.0 698.1075 0.14 ;
      END
   END dout0[161]
   PIN dout0[162]
      DIRECTION OUTPUT ;
      PORT
         LAYER metal4 ;
         RECT  700.7875 0.0 700.9275 0.14 ;
      END
   END dout0[162]
   PIN dout0[163]
      DIRECTION OUTPUT ;
      PORT
         LAYER metal4 ;
         RECT  703.6075 0.0 703.7475 0.14 ;
      END
   END dout0[163]
   PIN dout0[164]
      DIRECTION OUTPUT ;
      PORT
         LAYER metal4 ;
         RECT  706.4275 0.0 706.5675 0.14 ;
      END
   END dout0[164]
   PIN dout0[165]
      DIRECTION OUTPUT ;
      PORT
         LAYER metal4 ;
         RECT  709.2475 0.0 709.3875 0.14 ;
      END
   END dout0[165]
   PIN dout0[166]
      DIRECTION OUTPUT ;
      PORT
         LAYER metal4 ;
         RECT  712.0675 0.0 712.2075 0.14 ;
      END
   END dout0[166]
   PIN dout0[167]
      DIRECTION OUTPUT ;
      PORT
         LAYER metal4 ;
         RECT  714.8875 0.0 715.0275 0.14 ;
      END
   END dout0[167]
   PIN dout0[168]
      DIRECTION OUTPUT ;
      PORT
         LAYER metal4 ;
         RECT  717.7075 0.0 717.8475 0.14 ;
      END
   END dout0[168]
   PIN dout0[169]
      DIRECTION OUTPUT ;
      PORT
         LAYER metal4 ;
         RECT  720.5275 0.0 720.6675 0.14 ;
      END
   END dout0[169]
   PIN dout0[170]
      DIRECTION OUTPUT ;
      PORT
         LAYER metal4 ;
         RECT  723.3475 0.0 723.4875 0.14 ;
      END
   END dout0[170]
   PIN dout0[171]
      DIRECTION OUTPUT ;
      PORT
         LAYER metal4 ;
         RECT  726.1675 0.0 726.3075 0.14 ;
      END
   END dout0[171]
   PIN dout0[172]
      DIRECTION OUTPUT ;
      PORT
         LAYER metal4 ;
         RECT  728.9875 0.0 729.1275 0.14 ;
      END
   END dout0[172]
   PIN dout0[173]
      DIRECTION OUTPUT ;
      PORT
         LAYER metal4 ;
         RECT  731.8075 0.0 731.9475 0.14 ;
      END
   END dout0[173]
   PIN dout0[174]
      DIRECTION OUTPUT ;
      PORT
         LAYER metal4 ;
         RECT  734.6275 0.0 734.7675 0.14 ;
      END
   END dout0[174]
   PIN dout0[175]
      DIRECTION OUTPUT ;
      PORT
         LAYER metal4 ;
         RECT  737.4475 0.0 737.5875 0.14 ;
      END
   END dout0[175]
   PIN dout0[176]
      DIRECTION OUTPUT ;
      PORT
         LAYER metal4 ;
         RECT  740.2675 0.0 740.4075 0.14 ;
      END
   END dout0[176]
   PIN dout0[177]
      DIRECTION OUTPUT ;
      PORT
         LAYER metal4 ;
         RECT  743.0875 0.0 743.2275 0.14 ;
      END
   END dout0[177]
   PIN dout0[178]
      DIRECTION OUTPUT ;
      PORT
         LAYER metal4 ;
         RECT  745.9075 0.0 746.0475 0.14 ;
      END
   END dout0[178]
   PIN dout0[179]
      DIRECTION OUTPUT ;
      PORT
         LAYER metal4 ;
         RECT  748.7275 0.0 748.8675 0.14 ;
      END
   END dout0[179]
   PIN dout0[180]
      DIRECTION OUTPUT ;
      PORT
         LAYER metal4 ;
         RECT  751.5475 0.0 751.6875 0.14 ;
      END
   END dout0[180]
   PIN dout0[181]
      DIRECTION OUTPUT ;
      PORT
         LAYER metal4 ;
         RECT  754.3675 0.0 754.5075 0.14 ;
      END
   END dout0[181]
   PIN dout0[182]
      DIRECTION OUTPUT ;
      PORT
         LAYER metal4 ;
         RECT  757.1875 0.0 757.3275 0.14 ;
      END
   END dout0[182]
   PIN dout0[183]
      DIRECTION OUTPUT ;
      PORT
         LAYER metal4 ;
         RECT  760.0425 0.0 760.1825 0.14 ;
      END
   END dout0[183]
   PIN dout0[184]
      DIRECTION OUTPUT ;
      PORT
         LAYER metal4 ;
         RECT  762.9025 0.0 763.0425 0.14 ;
      END
   END dout0[184]
   PIN dout0[185]
      DIRECTION OUTPUT ;
      PORT
         LAYER metal4 ;
         RECT  765.7625 0.0 765.9025 0.14 ;
      END
   END dout0[185]
   PIN dout0[186]
      DIRECTION OUTPUT ;
      PORT
         LAYER metal4 ;
         RECT  768.6225 0.0 768.7625 0.14 ;
      END
   END dout0[186]
   PIN dout0[187]
      DIRECTION OUTPUT ;
      PORT
         LAYER metal4 ;
         RECT  771.4825 0.0 771.6225 0.14 ;
      END
   END dout0[187]
   PIN dout0[188]
      DIRECTION OUTPUT ;
      PORT
         LAYER metal4 ;
         RECT  774.3425 0.0 774.4825 0.14 ;
      END
   END dout0[188]
   PIN dout0[189]
      DIRECTION OUTPUT ;
      PORT
         LAYER metal4 ;
         RECT  777.2025 0.0 777.3425 0.14 ;
      END
   END dout0[189]
   PIN dout0[190]
      DIRECTION OUTPUT ;
      PORT
         LAYER metal4 ;
         RECT  780.0625 0.0 780.2025 0.14 ;
      END
   END dout0[190]
   PIN dout0[191]
      DIRECTION OUTPUT ;
      PORT
         LAYER metal4 ;
         RECT  782.9225 0.0 783.0625 0.14 ;
      END
   END dout0[191]
   PIN dout0[192]
      DIRECTION OUTPUT ;
      PORT
         LAYER metal4 ;
         RECT  785.96 0.0 786.1 0.14 ;
      END
   END dout0[192]
   PIN dout0[193]
      DIRECTION OUTPUT ;
      PORT
         LAYER metal4 ;
         RECT  788.78 0.0 788.92 0.14 ;
      END
   END dout0[193]
   PIN dout0[194]
      DIRECTION OUTPUT ;
      PORT
         LAYER metal4 ;
         RECT  790.46 0.0 790.6 0.14 ;
      END
   END dout0[194]
   PIN dout0[195]
      DIRECTION OUTPUT ;
      PORT
         LAYER metal4 ;
         RECT  793.32 0.0 793.46 0.14 ;
      END
   END dout0[195]
   PIN dout0[196]
      DIRECTION OUTPUT ;
      PORT
         LAYER metal4 ;
         RECT  796.18 0.0 796.32 0.14 ;
      END
   END dout0[196]
   PIN dout0[197]
      DIRECTION OUTPUT ;
      PORT
         LAYER metal4 ;
         RECT  799.04 0.0 799.18 0.14 ;
      END
   END dout0[197]
   PIN dout0[198]
      DIRECTION OUTPUT ;
      PORT
         LAYER metal4 ;
         RECT  801.9 0.0 802.04 0.14 ;
      END
   END dout0[198]
   PIN dout0[199]
      DIRECTION OUTPUT ;
      PORT
         LAYER metal4 ;
         RECT  804.76 0.0 804.9 0.14 ;
      END
   END dout0[199]
   PIN dout0[200]
      DIRECTION OUTPUT ;
      PORT
         LAYER metal4 ;
         RECT  807.62 0.0 807.76 0.14 ;
      END
   END dout0[200]
   PIN dout0[201]
      DIRECTION OUTPUT ;
      PORT
         LAYER metal4 ;
         RECT  810.48 0.0 810.62 0.14 ;
      END
   END dout0[201]
   PIN dout0[202]
      DIRECTION OUTPUT ;
      PORT
         LAYER metal4 ;
         RECT  813.34 0.0 813.48 0.14 ;
      END
   END dout0[202]
   PIN dout0[203]
      DIRECTION OUTPUT ;
      PORT
         LAYER metal4 ;
         RECT  816.1725 0.0 816.3125 0.14 ;
      END
   END dout0[203]
   PIN dout0[204]
      DIRECTION OUTPUT ;
      PORT
         LAYER metal4 ;
         RECT  818.9925 0.0 819.1325 0.14 ;
      END
   END dout0[204]
   PIN dout0[205]
      DIRECTION OUTPUT ;
      PORT
         LAYER metal4 ;
         RECT  821.92 0.0 822.06 0.14 ;
      END
   END dout0[205]
   PIN dout0[206]
      DIRECTION OUTPUT ;
      PORT
         LAYER metal4 ;
         RECT  824.78 0.0 824.92 0.14 ;
      END
   END dout0[206]
   PIN dout0[207]
      DIRECTION OUTPUT ;
      PORT
         LAYER metal4 ;
         RECT  827.64 0.0 827.78 0.14 ;
      END
   END dout0[207]
   PIN dout0[208]
      DIRECTION OUTPUT ;
      PORT
         LAYER metal4 ;
         RECT  830.5 0.0 830.64 0.14 ;
      END
   END dout0[208]
   PIN dout0[209]
      DIRECTION OUTPUT ;
      PORT
         LAYER metal4 ;
         RECT  833.3275 0.0 833.4675 0.14 ;
      END
   END dout0[209]
   PIN dout0[210]
      DIRECTION OUTPUT ;
      PORT
         LAYER metal4 ;
         RECT  836.1475 0.0 836.2875 0.14 ;
      END
   END dout0[210]
   PIN dout0[211]
      DIRECTION OUTPUT ;
      PORT
         LAYER metal4 ;
         RECT  838.9675 0.0 839.1075 0.14 ;
      END
   END dout0[211]
   PIN dout0[212]
      DIRECTION OUTPUT ;
      PORT
         LAYER metal4 ;
         RECT  841.7875 0.0 841.9275 0.14 ;
      END
   END dout0[212]
   PIN dout0[213]
      DIRECTION OUTPUT ;
      PORT
         LAYER metal4 ;
         RECT  844.6075 0.0 844.7475 0.14 ;
      END
   END dout0[213]
   PIN dout0[214]
      DIRECTION OUTPUT ;
      PORT
         LAYER metal4 ;
         RECT  847.4275 0.0 847.5675 0.14 ;
      END
   END dout0[214]
   PIN dout0[215]
      DIRECTION OUTPUT ;
      PORT
         LAYER metal4 ;
         RECT  850.2475 0.0 850.3875 0.14 ;
      END
   END dout0[215]
   PIN dout0[216]
      DIRECTION OUTPUT ;
      PORT
         LAYER metal4 ;
         RECT  853.0675 0.0 853.2075 0.14 ;
      END
   END dout0[216]
   PIN dout0[217]
      DIRECTION OUTPUT ;
      PORT
         LAYER metal4 ;
         RECT  855.8875 0.0 856.0275 0.14 ;
      END
   END dout0[217]
   PIN dout0[218]
      DIRECTION OUTPUT ;
      PORT
         LAYER metal4 ;
         RECT  858.7075 0.0 858.8475 0.14 ;
      END
   END dout0[218]
   PIN dout0[219]
      DIRECTION OUTPUT ;
      PORT
         LAYER metal4 ;
         RECT  861.5275 0.0 861.6675 0.14 ;
      END
   END dout0[219]
   PIN dout0[220]
      DIRECTION OUTPUT ;
      PORT
         LAYER metal4 ;
         RECT  864.3475 0.0 864.4875 0.14 ;
      END
   END dout0[220]
   PIN dout0[221]
      DIRECTION OUTPUT ;
      PORT
         LAYER metal4 ;
         RECT  867.1675 0.0 867.3075 0.14 ;
      END
   END dout0[221]
   PIN dout0[222]
      DIRECTION OUTPUT ;
      PORT
         LAYER metal4 ;
         RECT  869.9875 0.0 870.1275 0.14 ;
      END
   END dout0[222]
   PIN dout0[223]
      DIRECTION OUTPUT ;
      PORT
         LAYER metal4 ;
         RECT  872.8075 0.0 872.9475 0.14 ;
      END
   END dout0[223]
   PIN dout0[224]
      DIRECTION OUTPUT ;
      PORT
         LAYER metal4 ;
         RECT  875.6275 0.0 875.7675 0.14 ;
      END
   END dout0[224]
   PIN dout0[225]
      DIRECTION OUTPUT ;
      PORT
         LAYER metal4 ;
         RECT  878.4475 0.0 878.5875 0.14 ;
      END
   END dout0[225]
   PIN dout0[226]
      DIRECTION OUTPUT ;
      PORT
         LAYER metal4 ;
         RECT  881.2675 0.0 881.4075 0.14 ;
      END
   END dout0[226]
   PIN dout0[227]
      DIRECTION OUTPUT ;
      PORT
         LAYER metal4 ;
         RECT  884.0875 0.0 884.2275 0.14 ;
      END
   END dout0[227]
   PIN dout0[228]
      DIRECTION OUTPUT ;
      PORT
         LAYER metal4 ;
         RECT  886.9075 0.0 887.0475 0.14 ;
      END
   END dout0[228]
   PIN dout0[229]
      DIRECTION OUTPUT ;
      PORT
         LAYER metal4 ;
         RECT  889.7275 0.0 889.8675 0.14 ;
      END
   END dout0[229]
   PIN dout0[230]
      DIRECTION OUTPUT ;
      PORT
         LAYER metal4 ;
         RECT  892.5475 0.0 892.6875 0.14 ;
      END
   END dout0[230]
   PIN dout0[231]
      DIRECTION OUTPUT ;
      PORT
         LAYER metal4 ;
         RECT  895.3675 0.0 895.5075 0.14 ;
      END
   END dout0[231]
   PIN dout0[232]
      DIRECTION OUTPUT ;
      PORT
         LAYER metal4 ;
         RECT  898.1875 0.0 898.3275 0.14 ;
      END
   END dout0[232]
   PIN dout0[233]
      DIRECTION OUTPUT ;
      PORT
         LAYER metal4 ;
         RECT  901.0075 0.0 901.1475 0.14 ;
      END
   END dout0[233]
   PIN dout0[234]
      DIRECTION OUTPUT ;
      PORT
         LAYER metal4 ;
         RECT  903.8275 0.0 903.9675 0.14 ;
      END
   END dout0[234]
   PIN dout0[235]
      DIRECTION OUTPUT ;
      PORT
         LAYER metal4 ;
         RECT  906.6475 0.0 906.7875 0.14 ;
      END
   END dout0[235]
   PIN dout0[236]
      DIRECTION OUTPUT ;
      PORT
         LAYER metal4 ;
         RECT  909.4675 0.0 909.6075 0.14 ;
      END
   END dout0[236]
   PIN dout0[237]
      DIRECTION OUTPUT ;
      PORT
         LAYER metal4 ;
         RECT  912.2875 0.0 912.4275 0.14 ;
      END
   END dout0[237]
   PIN dout0[238]
      DIRECTION OUTPUT ;
      PORT
         LAYER metal4 ;
         RECT  915.1075 0.0 915.2475 0.14 ;
      END
   END dout0[238]
   PIN dout0[239]
      DIRECTION OUTPUT ;
      PORT
         LAYER metal4 ;
         RECT  917.9275 0.0 918.0675 0.14 ;
      END
   END dout0[239]
   PIN dout0[240]
      DIRECTION OUTPUT ;
      PORT
         LAYER metal4 ;
         RECT  920.7475 0.0 920.8875 0.14 ;
      END
   END dout0[240]
   PIN dout0[241]
      DIRECTION OUTPUT ;
      PORT
         LAYER metal4 ;
         RECT  923.5675 0.0 923.7075 0.14 ;
      END
   END dout0[241]
   PIN dout0[242]
      DIRECTION OUTPUT ;
      PORT
         LAYER metal4 ;
         RECT  926.3875 0.0 926.5275 0.14 ;
      END
   END dout0[242]
   PIN dout0[243]
      DIRECTION OUTPUT ;
      PORT
         LAYER metal4 ;
         RECT  929.2075 0.0 929.3475 0.14 ;
      END
   END dout0[243]
   PIN dout0[244]
      DIRECTION OUTPUT ;
      PORT
         LAYER metal4 ;
         RECT  932.0275 0.0 932.1675 0.14 ;
      END
   END dout0[244]
   PIN dout0[245]
      DIRECTION OUTPUT ;
      PORT
         LAYER metal4 ;
         RECT  934.8475 0.0 934.9875 0.14 ;
      END
   END dout0[245]
   PIN dout0[246]
      DIRECTION OUTPUT ;
      PORT
         LAYER metal4 ;
         RECT  937.6675 0.0 937.8075 0.14 ;
      END
   END dout0[246]
   PIN dout0[247]
      DIRECTION OUTPUT ;
      PORT
         LAYER metal4 ;
         RECT  940.4875 0.0 940.6275 0.14 ;
      END
   END dout0[247]
   PIN dout0[248]
      DIRECTION OUTPUT ;
      PORT
         LAYER metal4 ;
         RECT  943.3075 0.0 943.4475 0.14 ;
      END
   END dout0[248]
   PIN dout0[249]
      DIRECTION OUTPUT ;
      PORT
         LAYER metal4 ;
         RECT  946.1275 0.0 946.2675 0.14 ;
      END
   END dout0[249]
   PIN dout0[250]
      DIRECTION OUTPUT ;
      PORT
         LAYER metal4 ;
         RECT  948.9475 0.0 949.0875 0.14 ;
      END
   END dout0[250]
   PIN dout0[251]
      DIRECTION OUTPUT ;
      PORT
         LAYER metal4 ;
         RECT  951.7675 0.0 951.9075 0.14 ;
      END
   END dout0[251]
   PIN dout0[252]
      DIRECTION OUTPUT ;
      PORT
         LAYER metal4 ;
         RECT  954.5875 0.0 954.7275 0.14 ;
      END
   END dout0[252]
   PIN dout0[253]
      DIRECTION OUTPUT ;
      PORT
         LAYER metal4 ;
         RECT  957.4075 0.0 957.5475 0.14 ;
      END
   END dout0[253]
   PIN dout0[254]
      DIRECTION OUTPUT ;
      PORT
         LAYER metal4 ;
         RECT  960.2425 0.0 960.3825 0.14 ;
      END
   END dout0[254]
   PIN dout0[255]
      DIRECTION OUTPUT ;
      PORT
         LAYER metal4 ;
         RECT  963.12 0.0 963.26 0.14 ;
      END
   END dout0[255]
   PIN dout0[256]
      DIRECTION OUTPUT ;
      PORT
         LAYER metal4 ;
         RECT  965.9625 0.0 966.1025 0.14 ;
      END
   END dout0[256]
   PIN dout0[257]
      DIRECTION OUTPUT ;
      PORT
         LAYER metal4 ;
         RECT  968.8225 0.0 968.9625 0.14 ;
      END
   END dout0[257]
   PIN dout0[258]
      DIRECTION OUTPUT ;
      PORT
         LAYER metal4 ;
         RECT  971.6825 0.0 971.8225 0.14 ;
      END
   END dout0[258]
   PIN dout0[259]
      DIRECTION OUTPUT ;
      PORT
         LAYER metal4 ;
         RECT  974.5425 0.0 974.6825 0.14 ;
      END
   END dout0[259]
   PIN dout0[260]
      DIRECTION OUTPUT ;
      PORT
         LAYER metal4 ;
         RECT  977.4025 0.0 977.5425 0.14 ;
      END
   END dout0[260]
   PIN dout0[261]
      DIRECTION OUTPUT ;
      PORT
         LAYER metal4 ;
         RECT  980.2625 0.0 980.4025 0.14 ;
      END
   END dout0[261]
   PIN dout0[262]
      DIRECTION OUTPUT ;
      PORT
         LAYER metal4 ;
         RECT  983.1225 0.0 983.2625 0.14 ;
      END
   END dout0[262]
   PIN dout0[263]
      DIRECTION OUTPUT ;
      PORT
         LAYER metal4 ;
         RECT  986.18 0.0 986.32 0.14 ;
      END
   END dout0[263]
   PIN dout0[264]
      DIRECTION OUTPUT ;
      PORT
         LAYER metal4 ;
         RECT  989.0 0.0 989.14 0.14 ;
      END
   END dout0[264]
   PIN dout0[265]
      DIRECTION OUTPUT ;
      PORT
         LAYER metal4 ;
         RECT  991.82 0.0 991.96 0.14 ;
      END
   END dout0[265]
   PIN dout0[266]
      DIRECTION OUTPUT ;
      PORT
         LAYER metal4 ;
         RECT  993.52 0.0 993.66 0.14 ;
      END
   END dout0[266]
   PIN dout0[267]
      DIRECTION OUTPUT ;
      PORT
         LAYER metal4 ;
         RECT  996.38 0.0 996.52 0.14 ;
      END
   END dout0[267]
   PIN dout0[268]
      DIRECTION OUTPUT ;
      PORT
         LAYER metal4 ;
         RECT  999.24 0.0 999.38 0.14 ;
      END
   END dout0[268]
   PIN dout0[269]
      DIRECTION OUTPUT ;
      PORT
         LAYER metal4 ;
         RECT  1002.1 0.0 1002.24 0.14 ;
      END
   END dout0[269]
   PIN dout0[270]
      DIRECTION OUTPUT ;
      PORT
         LAYER metal4 ;
         RECT  1004.96 0.0 1005.1 0.14 ;
      END
   END dout0[270]
   PIN dout0[271]
      DIRECTION OUTPUT ;
      PORT
         LAYER metal4 ;
         RECT  1007.82 0.0 1007.96 0.14 ;
      END
   END dout0[271]
   PIN dout0[272]
      DIRECTION OUTPUT ;
      PORT
         LAYER metal4 ;
         RECT  1010.68 0.0 1010.82 0.14 ;
      END
   END dout0[272]
   PIN dout0[273]
      DIRECTION OUTPUT ;
      PORT
         LAYER metal4 ;
         RECT  1013.54 0.0 1013.68 0.14 ;
      END
   END dout0[273]
   PIN dout0[274]
      DIRECTION OUTPUT ;
      PORT
         LAYER metal4 ;
         RECT  1016.3925 0.0 1016.5325 0.14 ;
      END
   END dout0[274]
   PIN dout0[275]
      DIRECTION OUTPUT ;
      PORT
         LAYER metal4 ;
         RECT  1019.2125 0.0 1019.3525 0.14 ;
      END
   END dout0[275]
   PIN dout0[276]
      DIRECTION OUTPUT ;
      PORT
         LAYER metal4 ;
         RECT  1022.0325 0.0 1022.1725 0.14 ;
      END
   END dout0[276]
   PIN dout0[277]
      DIRECTION OUTPUT ;
      PORT
         LAYER metal4 ;
         RECT  1024.98 0.0 1025.12 0.14 ;
      END
   END dout0[277]
   PIN dout0[278]
      DIRECTION OUTPUT ;
      PORT
         LAYER metal4 ;
         RECT  1027.84 0.0 1027.98 0.14 ;
      END
   END dout0[278]
   PIN dout0[279]
      DIRECTION OUTPUT ;
      PORT
         LAYER metal4 ;
         RECT  1030.7 0.0 1030.84 0.14 ;
      END
   END dout0[279]
   PIN dout0[280]
      DIRECTION OUTPUT ;
      PORT
         LAYER metal4 ;
         RECT  1033.5475 0.0 1033.6875 0.14 ;
      END
   END dout0[280]
   PIN dout0[281]
      DIRECTION OUTPUT ;
      PORT
         LAYER metal4 ;
         RECT  1036.3675 0.0 1036.5075 0.14 ;
      END
   END dout0[281]
   PIN dout0[282]
      DIRECTION OUTPUT ;
      PORT
         LAYER metal4 ;
         RECT  1039.1875 0.0 1039.3275 0.14 ;
      END
   END dout0[282]
   PIN dout0[283]
      DIRECTION OUTPUT ;
      PORT
         LAYER metal4 ;
         RECT  1042.0075 0.0 1042.1475 0.14 ;
      END
   END dout0[283]
   PIN dout0[284]
      DIRECTION OUTPUT ;
      PORT
         LAYER metal4 ;
         RECT  1044.8275 0.0 1044.9675 0.14 ;
      END
   END dout0[284]
   PIN dout0[285]
      DIRECTION OUTPUT ;
      PORT
         LAYER metal4 ;
         RECT  1047.6475 0.0 1047.7875 0.14 ;
      END
   END dout0[285]
   PIN dout0[286]
      DIRECTION OUTPUT ;
      PORT
         LAYER metal4 ;
         RECT  1050.4675 0.0 1050.6075 0.14 ;
      END
   END dout0[286]
   PIN dout0[287]
      DIRECTION OUTPUT ;
      PORT
         LAYER metal4 ;
         RECT  1053.2875 0.0 1053.4275 0.14 ;
      END
   END dout0[287]
   PIN dout0[288]
      DIRECTION OUTPUT ;
      PORT
         LAYER metal4 ;
         RECT  1056.1075 0.0 1056.2475 0.14 ;
      END
   END dout0[288]
   PIN dout0[289]
      DIRECTION OUTPUT ;
      PORT
         LAYER metal4 ;
         RECT  1058.9275 0.0 1059.0675 0.14 ;
      END
   END dout0[289]
   PIN dout0[290]
      DIRECTION OUTPUT ;
      PORT
         LAYER metal4 ;
         RECT  1061.7475 0.0 1061.8875 0.14 ;
      END
   END dout0[290]
   PIN dout0[291]
      DIRECTION OUTPUT ;
      PORT
         LAYER metal4 ;
         RECT  1064.5675 0.0 1064.7075 0.14 ;
      END
   END dout0[291]
   PIN dout0[292]
      DIRECTION OUTPUT ;
      PORT
         LAYER metal4 ;
         RECT  1067.3875 0.0 1067.5275 0.14 ;
      END
   END dout0[292]
   PIN dout0[293]
      DIRECTION OUTPUT ;
      PORT
         LAYER metal4 ;
         RECT  1070.2075 0.0 1070.3475 0.14 ;
      END
   END dout0[293]
   PIN dout0[294]
      DIRECTION OUTPUT ;
      PORT
         LAYER metal4 ;
         RECT  1073.0275 0.0 1073.1675 0.14 ;
      END
   END dout0[294]
   PIN dout0[295]
      DIRECTION OUTPUT ;
      PORT
         LAYER metal4 ;
         RECT  1075.8475 0.0 1075.9875 0.14 ;
      END
   END dout0[295]
   PIN dout0[296]
      DIRECTION OUTPUT ;
      PORT
         LAYER metal4 ;
         RECT  1078.6675 0.0 1078.8075 0.14 ;
      END
   END dout0[296]
   PIN dout0[297]
      DIRECTION OUTPUT ;
      PORT
         LAYER metal4 ;
         RECT  1081.4875 0.0 1081.6275 0.14 ;
      END
   END dout0[297]
   PIN dout0[298]
      DIRECTION OUTPUT ;
      PORT
         LAYER metal4 ;
         RECT  1084.3075 0.0 1084.4475 0.14 ;
      END
   END dout0[298]
   PIN dout0[299]
      DIRECTION OUTPUT ;
      PORT
         LAYER metal4 ;
         RECT  1087.1275 0.0 1087.2675 0.14 ;
      END
   END dout0[299]
   PIN dout0[300]
      DIRECTION OUTPUT ;
      PORT
         LAYER metal4 ;
         RECT  1089.9475 0.0 1090.0875 0.14 ;
      END
   END dout0[300]
   PIN dout0[301]
      DIRECTION OUTPUT ;
      PORT
         LAYER metal4 ;
         RECT  1092.7675 0.0 1092.9075 0.14 ;
      END
   END dout0[301]
   PIN dout0[302]
      DIRECTION OUTPUT ;
      PORT
         LAYER metal4 ;
         RECT  1095.5875 0.0 1095.7275 0.14 ;
      END
   END dout0[302]
   PIN dout0[303]
      DIRECTION OUTPUT ;
      PORT
         LAYER metal4 ;
         RECT  1098.4075 0.0 1098.5475 0.14 ;
      END
   END dout0[303]
   PIN dout0[304]
      DIRECTION OUTPUT ;
      PORT
         LAYER metal4 ;
         RECT  1101.2275 0.0 1101.3675 0.14 ;
      END
   END dout0[304]
   PIN dout0[305]
      DIRECTION OUTPUT ;
      PORT
         LAYER metal4 ;
         RECT  1104.0475 0.0 1104.1875 0.14 ;
      END
   END dout0[305]
   PIN dout0[306]
      DIRECTION OUTPUT ;
      PORT
         LAYER metal4 ;
         RECT  1106.8675 0.0 1107.0075 0.14 ;
      END
   END dout0[306]
   PIN dout0[307]
      DIRECTION OUTPUT ;
      PORT
         LAYER metal4 ;
         RECT  1109.6875 0.0 1109.8275 0.14 ;
      END
   END dout0[307]
   PIN dout0[308]
      DIRECTION OUTPUT ;
      PORT
         LAYER metal4 ;
         RECT  1112.5075 0.0 1112.6475 0.14 ;
      END
   END dout0[308]
   PIN dout0[309]
      DIRECTION OUTPUT ;
      PORT
         LAYER metal4 ;
         RECT  1115.3275 0.0 1115.4675 0.14 ;
      END
   END dout0[309]
   PIN dout0[310]
      DIRECTION OUTPUT ;
      PORT
         LAYER metal4 ;
         RECT  1118.1475 0.0 1118.2875 0.14 ;
      END
   END dout0[310]
   PIN dout0[311]
      DIRECTION OUTPUT ;
      PORT
         LAYER metal4 ;
         RECT  1120.9675 0.0 1121.1075 0.14 ;
      END
   END dout0[311]
   PIN dout0[312]
      DIRECTION OUTPUT ;
      PORT
         LAYER metal4 ;
         RECT  1123.7875 0.0 1123.9275 0.14 ;
      END
   END dout0[312]
   PIN dout0[313]
      DIRECTION OUTPUT ;
      PORT
         LAYER metal4 ;
         RECT  1126.6075 0.0 1126.7475 0.14 ;
      END
   END dout0[313]
   PIN dout0[314]
      DIRECTION OUTPUT ;
      PORT
         LAYER metal4 ;
         RECT  1129.4275 0.0 1129.5675 0.14 ;
      END
   END dout0[314]
   PIN dout0[315]
      DIRECTION OUTPUT ;
      PORT
         LAYER metal4 ;
         RECT  1132.2475 0.0 1132.3875 0.14 ;
      END
   END dout0[315]
   PIN dout0[316]
      DIRECTION OUTPUT ;
      PORT
         LAYER metal4 ;
         RECT  1135.0675 0.0 1135.2075 0.14 ;
      END
   END dout0[316]
   PIN dout0[317]
      DIRECTION OUTPUT ;
      PORT
         LAYER metal4 ;
         RECT  1137.8875 0.0 1138.0275 0.14 ;
      END
   END dout0[317]
   PIN dout0[318]
      DIRECTION OUTPUT ;
      PORT
         LAYER metal4 ;
         RECT  1140.7075 0.0 1140.8475 0.14 ;
      END
   END dout0[318]
   PIN dout0[319]
      DIRECTION OUTPUT ;
      PORT
         LAYER metal4 ;
         RECT  1143.5275 0.0 1143.6675 0.14 ;
      END
   END dout0[319]
   PIN dout0[320]
      DIRECTION OUTPUT ;
      PORT
         LAYER metal4 ;
         RECT  1146.3475 0.0 1146.4875 0.14 ;
      END
   END dout0[320]
   PIN dout0[321]
      DIRECTION OUTPUT ;
      PORT
         LAYER metal4 ;
         RECT  1149.1675 0.0 1149.3075 0.14 ;
      END
   END dout0[321]
   PIN dout0[322]
      DIRECTION OUTPUT ;
      PORT
         LAYER metal4 ;
         RECT  1151.9875 0.0 1152.1275 0.14 ;
      END
   END dout0[322]
   PIN dout0[323]
      DIRECTION OUTPUT ;
      PORT
         LAYER metal4 ;
         RECT  1154.8075 0.0 1154.9475 0.14 ;
      END
   END dout0[323]
   PIN dout0[324]
      DIRECTION OUTPUT ;
      PORT
         LAYER metal4 ;
         RECT  1157.6275 0.0 1157.7675 0.14 ;
      END
   END dout0[324]
   PIN dout0[325]
      DIRECTION OUTPUT ;
      PORT
         LAYER metal4 ;
         RECT  1160.4475 0.0 1160.5875 0.14 ;
      END
   END dout0[325]
   PIN dout0[326]
      DIRECTION OUTPUT ;
      PORT
         LAYER metal4 ;
         RECT  1163.3025 0.0 1163.4425 0.14 ;
      END
   END dout0[326]
   PIN dout0[327]
      DIRECTION OUTPUT ;
      PORT
         LAYER metal4 ;
         RECT  1166.1625 0.0 1166.3025 0.14 ;
      END
   END dout0[327]
   PIN dout0[328]
      DIRECTION OUTPUT ;
      PORT
         LAYER metal4 ;
         RECT  1169.0225 0.0 1169.1625 0.14 ;
      END
   END dout0[328]
   PIN dout0[329]
      DIRECTION OUTPUT ;
      PORT
         LAYER metal4 ;
         RECT  1171.8825 0.0 1172.0225 0.14 ;
      END
   END dout0[329]
   PIN dout0[330]
      DIRECTION OUTPUT ;
      PORT
         LAYER metal4 ;
         RECT  1174.7425 0.0 1174.8825 0.14 ;
      END
   END dout0[330]
   PIN dout0[331]
      DIRECTION OUTPUT ;
      PORT
         LAYER metal4 ;
         RECT  1177.6025 0.0 1177.7425 0.14 ;
      END
   END dout0[331]
   PIN dout0[332]
      DIRECTION OUTPUT ;
      PORT
         LAYER metal4 ;
         RECT  1180.4625 0.0 1180.6025 0.14 ;
      END
   END dout0[332]
   PIN dout0[333]
      DIRECTION OUTPUT ;
      PORT
         LAYER metal4 ;
         RECT  1183.3225 0.0 1183.4625 0.14 ;
      END
   END dout0[333]
   PIN dout0[334]
      DIRECTION OUTPUT ;
      PORT
         LAYER metal4 ;
         RECT  1186.1825 0.0 1186.3225 0.14 ;
      END
   END dout0[334]
   PIN dout0[335]
      DIRECTION OUTPUT ;
      PORT
         LAYER metal4 ;
         RECT  1189.22 0.0 1189.36 0.14 ;
      END
   END dout0[335]
   PIN dout0[336]
      DIRECTION OUTPUT ;
      PORT
         LAYER metal4 ;
         RECT  1192.04 0.0 1192.18 0.14 ;
      END
   END dout0[336]
   PIN dout0[337]
      DIRECTION OUTPUT ;
      PORT
         LAYER metal4 ;
         RECT  1193.72 0.0 1193.86 0.14 ;
      END
   END dout0[337]
   PIN dout0[338]
      DIRECTION OUTPUT ;
      PORT
         LAYER metal4 ;
         RECT  1196.58 0.0 1196.72 0.14 ;
      END
   END dout0[338]
   PIN dout0[339]
      DIRECTION OUTPUT ;
      PORT
         LAYER metal4 ;
         RECT  1199.44 0.0 1199.58 0.14 ;
      END
   END dout0[339]
   PIN dout0[340]
      DIRECTION OUTPUT ;
      PORT
         LAYER metal4 ;
         RECT  1202.3 0.0 1202.44 0.14 ;
      END
   END dout0[340]
   PIN dout0[341]
      DIRECTION OUTPUT ;
      PORT
         LAYER metal4 ;
         RECT  1205.16 0.0 1205.3 0.14 ;
      END
   END dout0[341]
   PIN dout0[342]
      DIRECTION OUTPUT ;
      PORT
         LAYER metal4 ;
         RECT  1208.02 0.0 1208.16 0.14 ;
      END
   END dout0[342]
   PIN dout0[343]
      DIRECTION OUTPUT ;
      PORT
         LAYER metal4 ;
         RECT  1210.88 0.0 1211.02 0.14 ;
      END
   END dout0[343]
   PIN dout0[344]
      DIRECTION OUTPUT ;
      PORT
         LAYER metal4 ;
         RECT  1213.74 0.0 1213.88 0.14 ;
      END
   END dout0[344]
   PIN dout0[345]
      DIRECTION OUTPUT ;
      PORT
         LAYER metal4 ;
         RECT  1216.6 0.0 1216.74 0.14 ;
      END
   END dout0[345]
   PIN dout0[346]
      DIRECTION OUTPUT ;
      PORT
         LAYER metal4 ;
         RECT  1219.4325 0.0 1219.5725 0.14 ;
      END
   END dout0[346]
   PIN dout0[347]
      DIRECTION OUTPUT ;
      PORT
         LAYER metal4 ;
         RECT  1222.2525 0.0 1222.3925 0.14 ;
      END
   END dout0[347]
   PIN dout0[348]
      DIRECTION OUTPUT ;
      PORT
         LAYER metal4 ;
         RECT  1225.18 0.0 1225.32 0.14 ;
      END
   END dout0[348]
   PIN dout0[349]
      DIRECTION OUTPUT ;
      PORT
         LAYER metal4 ;
         RECT  1228.04 0.0 1228.18 0.14 ;
      END
   END dout0[349]
   PIN dout0[350]
      DIRECTION OUTPUT ;
      PORT
         LAYER metal4 ;
         RECT  1230.9 0.0 1231.04 0.14 ;
      END
   END dout0[350]
   PIN dout0[351]
      DIRECTION OUTPUT ;
      PORT
         LAYER metal4 ;
         RECT  1233.76 0.0 1233.9 0.14 ;
      END
   END dout0[351]
   PIN dout0[352]
      DIRECTION OUTPUT ;
      PORT
         LAYER metal4 ;
         RECT  1236.5875 0.0 1236.7275 0.14 ;
      END
   END dout0[352]
   PIN dout0[353]
      DIRECTION OUTPUT ;
      PORT
         LAYER metal4 ;
         RECT  1239.4075 0.0 1239.5475 0.14 ;
      END
   END dout0[353]
   PIN dout0[354]
      DIRECTION OUTPUT ;
      PORT
         LAYER metal4 ;
         RECT  1242.2275 0.0 1242.3675 0.14 ;
      END
   END dout0[354]
   PIN dout0[355]
      DIRECTION OUTPUT ;
      PORT
         LAYER metal4 ;
         RECT  1245.0475 0.0 1245.1875 0.14 ;
      END
   END dout0[355]
   PIN dout0[356]
      DIRECTION OUTPUT ;
      PORT
         LAYER metal4 ;
         RECT  1247.8675 0.0 1248.0075 0.14 ;
      END
   END dout0[356]
   PIN dout0[357]
      DIRECTION OUTPUT ;
      PORT
         LAYER metal4 ;
         RECT  1250.6875 0.0 1250.8275 0.14 ;
      END
   END dout0[357]
   PIN dout0[358]
      DIRECTION OUTPUT ;
      PORT
         LAYER metal4 ;
         RECT  1253.5075 0.0 1253.6475 0.14 ;
      END
   END dout0[358]
   PIN dout0[359]
      DIRECTION OUTPUT ;
      PORT
         LAYER metal4 ;
         RECT  1256.3275 0.0 1256.4675 0.14 ;
      END
   END dout0[359]
   PIN dout0[360]
      DIRECTION OUTPUT ;
      PORT
         LAYER metal4 ;
         RECT  1259.1475 0.0 1259.2875 0.14 ;
      END
   END dout0[360]
   PIN dout0[361]
      DIRECTION OUTPUT ;
      PORT
         LAYER metal4 ;
         RECT  1261.9675 0.0 1262.1075 0.14 ;
      END
   END dout0[361]
   PIN dout0[362]
      DIRECTION OUTPUT ;
      PORT
         LAYER metal4 ;
         RECT  1264.7875 0.0 1264.9275 0.14 ;
      END
   END dout0[362]
   PIN dout0[363]
      DIRECTION OUTPUT ;
      PORT
         LAYER metal4 ;
         RECT  1267.6075 0.0 1267.7475 0.14 ;
      END
   END dout0[363]
   PIN dout0[364]
      DIRECTION OUTPUT ;
      PORT
         LAYER metal4 ;
         RECT  1270.4275 0.0 1270.5675 0.14 ;
      END
   END dout0[364]
   PIN dout0[365]
      DIRECTION OUTPUT ;
      PORT
         LAYER metal4 ;
         RECT  1273.2475 0.0 1273.3875 0.14 ;
      END
   END dout0[365]
   PIN dout0[366]
      DIRECTION OUTPUT ;
      PORT
         LAYER metal4 ;
         RECT  1276.0675 0.0 1276.2075 0.14 ;
      END
   END dout0[366]
   PIN dout0[367]
      DIRECTION OUTPUT ;
      PORT
         LAYER metal4 ;
         RECT  1278.8875 0.0 1279.0275 0.14 ;
      END
   END dout0[367]
   PIN dout0[368]
      DIRECTION OUTPUT ;
      PORT
         LAYER metal4 ;
         RECT  1281.7075 0.0 1281.8475 0.14 ;
      END
   END dout0[368]
   PIN dout0[369]
      DIRECTION OUTPUT ;
      PORT
         LAYER metal4 ;
         RECT  1284.5275 0.0 1284.6675 0.14 ;
      END
   END dout0[369]
   PIN dout0[370]
      DIRECTION OUTPUT ;
      PORT
         LAYER metal4 ;
         RECT  1287.3475 0.0 1287.4875 0.14 ;
      END
   END dout0[370]
   PIN dout0[371]
      DIRECTION OUTPUT ;
      PORT
         LAYER metal4 ;
         RECT  1290.1675 0.0 1290.3075 0.14 ;
      END
   END dout0[371]
   PIN dout0[372]
      DIRECTION OUTPUT ;
      PORT
         LAYER metal4 ;
         RECT  1292.9875 0.0 1293.1275 0.14 ;
      END
   END dout0[372]
   PIN dout0[373]
      DIRECTION OUTPUT ;
      PORT
         LAYER metal4 ;
         RECT  1295.8075 0.0 1295.9475 0.14 ;
      END
   END dout0[373]
   PIN dout0[374]
      DIRECTION OUTPUT ;
      PORT
         LAYER metal4 ;
         RECT  1298.6275 0.0 1298.7675 0.14 ;
      END
   END dout0[374]
   PIN dout0[375]
      DIRECTION OUTPUT ;
      PORT
         LAYER metal4 ;
         RECT  1301.4475 0.0 1301.5875 0.14 ;
      END
   END dout0[375]
   PIN dout0[376]
      DIRECTION OUTPUT ;
      PORT
         LAYER metal4 ;
         RECT  1304.2675 0.0 1304.4075 0.14 ;
      END
   END dout0[376]
   PIN dout0[377]
      DIRECTION OUTPUT ;
      PORT
         LAYER metal4 ;
         RECT  1307.0875 0.0 1307.2275 0.14 ;
      END
   END dout0[377]
   PIN dout0[378]
      DIRECTION OUTPUT ;
      PORT
         LAYER metal4 ;
         RECT  1309.9075 0.0 1310.0475 0.14 ;
      END
   END dout0[378]
   PIN dout0[379]
      DIRECTION OUTPUT ;
      PORT
         LAYER metal4 ;
         RECT  1312.7275 0.0 1312.8675 0.14 ;
      END
   END dout0[379]
   PIN dout0[380]
      DIRECTION OUTPUT ;
      PORT
         LAYER metal4 ;
         RECT  1315.5475 0.0 1315.6875 0.14 ;
      END
   END dout0[380]
   PIN dout0[381]
      DIRECTION OUTPUT ;
      PORT
         LAYER metal4 ;
         RECT  1318.3675 0.0 1318.5075 0.14 ;
      END
   END dout0[381]
   PIN dout0[382]
      DIRECTION OUTPUT ;
      PORT
         LAYER metal4 ;
         RECT  1321.1875 0.0 1321.3275 0.14 ;
      END
   END dout0[382]
   PIN dout0[383]
      DIRECTION OUTPUT ;
      PORT
         LAYER metal4 ;
         RECT  1324.0075 0.0 1324.1475 0.14 ;
      END
   END dout0[383]
   PIN dout0[384]
      DIRECTION OUTPUT ;
      PORT
         LAYER metal4 ;
         RECT  1326.8275 0.0 1326.9675 0.14 ;
      END
   END dout0[384]
   PIN dout0[385]
      DIRECTION OUTPUT ;
      PORT
         LAYER metal4 ;
         RECT  1329.6475 0.0 1329.7875 0.14 ;
      END
   END dout0[385]
   PIN dout0[386]
      DIRECTION OUTPUT ;
      PORT
         LAYER metal4 ;
         RECT  1332.4675 0.0 1332.6075 0.14 ;
      END
   END dout0[386]
   PIN dout0[387]
      DIRECTION OUTPUT ;
      PORT
         LAYER metal4 ;
         RECT  1335.2875 0.0 1335.4275 0.14 ;
      END
   END dout0[387]
   PIN dout0[388]
      DIRECTION OUTPUT ;
      PORT
         LAYER metal4 ;
         RECT  1338.1075 0.0 1338.2475 0.14 ;
      END
   END dout0[388]
   PIN dout0[389]
      DIRECTION OUTPUT ;
      PORT
         LAYER metal4 ;
         RECT  1340.9275 0.0 1341.0675 0.14 ;
      END
   END dout0[389]
   PIN dout0[390]
      DIRECTION OUTPUT ;
      PORT
         LAYER metal4 ;
         RECT  1343.7475 0.0 1343.8875 0.14 ;
      END
   END dout0[390]
   PIN dout0[391]
      DIRECTION OUTPUT ;
      PORT
         LAYER metal4 ;
         RECT  1346.5675 0.0 1346.7075 0.14 ;
      END
   END dout0[391]
   PIN dout0[392]
      DIRECTION OUTPUT ;
      PORT
         LAYER metal4 ;
         RECT  1349.3875 0.0 1349.5275 0.14 ;
      END
   END dout0[392]
   PIN dout0[393]
      DIRECTION OUTPUT ;
      PORT
         LAYER metal4 ;
         RECT  1352.2075 0.0 1352.3475 0.14 ;
      END
   END dout0[393]
   PIN dout0[394]
      DIRECTION OUTPUT ;
      PORT
         LAYER metal4 ;
         RECT  1355.0275 0.0 1355.1675 0.14 ;
      END
   END dout0[394]
   PIN dout0[395]
      DIRECTION OUTPUT ;
      PORT
         LAYER metal4 ;
         RECT  1357.8475 0.0 1357.9875 0.14 ;
      END
   END dout0[395]
   PIN dout0[396]
      DIRECTION OUTPUT ;
      PORT
         LAYER metal4 ;
         RECT  1360.6675 0.0 1360.8075 0.14 ;
      END
   END dout0[396]
   PIN dout0[397]
      DIRECTION OUTPUT ;
      PORT
         LAYER metal4 ;
         RECT  1363.5025 0.0 1363.6425 0.14 ;
      END
   END dout0[397]
   PIN dout0[398]
      DIRECTION OUTPUT ;
      PORT
         LAYER metal4 ;
         RECT  1366.38 0.0 1366.52 0.14 ;
      END
   END dout0[398]
   PIN dout0[399]
      DIRECTION OUTPUT ;
      PORT
         LAYER metal4 ;
         RECT  1369.2225 0.0 1369.3625 0.14 ;
      END
   END dout0[399]
   PIN dout0[400]
      DIRECTION OUTPUT ;
      PORT
         LAYER metal4 ;
         RECT  1372.0825 0.0 1372.2225 0.14 ;
      END
   END dout0[400]
   PIN dout0[401]
      DIRECTION OUTPUT ;
      PORT
         LAYER metal4 ;
         RECT  1374.9425 0.0 1375.0825 0.14 ;
      END
   END dout0[401]
   PIN dout0[402]
      DIRECTION OUTPUT ;
      PORT
         LAYER metal4 ;
         RECT  1377.8025 0.0 1377.9425 0.14 ;
      END
   END dout0[402]
   PIN dout0[403]
      DIRECTION OUTPUT ;
      PORT
         LAYER metal4 ;
         RECT  1380.6625 0.0 1380.8025 0.14 ;
      END
   END dout0[403]
   PIN dout0[404]
      DIRECTION OUTPUT ;
      PORT
         LAYER metal4 ;
         RECT  1383.5225 0.0 1383.6625 0.14 ;
      END
   END dout0[404]
   PIN dout0[405]
      DIRECTION OUTPUT ;
      PORT
         LAYER metal4 ;
         RECT  1386.3825 0.0 1386.5225 0.14 ;
      END
   END dout0[405]
   PIN dout0[406]
      DIRECTION OUTPUT ;
      PORT
         LAYER metal4 ;
         RECT  1389.44 0.0 1389.58 0.14 ;
      END
   END dout0[406]
   PIN dout0[407]
      DIRECTION OUTPUT ;
      PORT
         LAYER metal4 ;
         RECT  1392.26 0.0 1392.4 0.14 ;
      END
   END dout0[407]
   PIN dout0[408]
      DIRECTION OUTPUT ;
      PORT
         LAYER metal4 ;
         RECT  1395.08 0.0 1395.22 0.14 ;
      END
   END dout0[408]
   PIN dout0[409]
      DIRECTION OUTPUT ;
      PORT
         LAYER metal4 ;
         RECT  1396.78 0.0 1396.92 0.14 ;
      END
   END dout0[409]
   PIN dout0[410]
      DIRECTION OUTPUT ;
      PORT
         LAYER metal4 ;
         RECT  1399.64 0.0 1399.78 0.14 ;
      END
   END dout0[410]
   PIN dout0[411]
      DIRECTION OUTPUT ;
      PORT
         LAYER metal4 ;
         RECT  1402.5 0.0 1402.64 0.14 ;
      END
   END dout0[411]
   PIN dout0[412]
      DIRECTION OUTPUT ;
      PORT
         LAYER metal4 ;
         RECT  1405.36 0.0 1405.5 0.14 ;
      END
   END dout0[412]
   PIN dout0[413]
      DIRECTION OUTPUT ;
      PORT
         LAYER metal4 ;
         RECT  1408.22 0.0 1408.36 0.14 ;
      END
   END dout0[413]
   PIN dout0[414]
      DIRECTION OUTPUT ;
      PORT
         LAYER metal4 ;
         RECT  1411.08 0.0 1411.22 0.14 ;
      END
   END dout0[414]
   PIN dout0[415]
      DIRECTION OUTPUT ;
      PORT
         LAYER metal4 ;
         RECT  1413.94 0.0 1414.08 0.14 ;
      END
   END dout0[415]
   PIN dout0[416]
      DIRECTION OUTPUT ;
      PORT
         LAYER metal4 ;
         RECT  1416.8 0.0 1416.94 0.14 ;
      END
   END dout0[416]
   PIN dout0[417]
      DIRECTION OUTPUT ;
      PORT
         LAYER metal4 ;
         RECT  1419.6525 0.0 1419.7925 0.14 ;
      END
   END dout0[417]
   PIN dout0[418]
      DIRECTION OUTPUT ;
      PORT
         LAYER metal4 ;
         RECT  1422.4725 0.0 1422.6125 0.14 ;
      END
   END dout0[418]
   PIN dout0[419]
      DIRECTION OUTPUT ;
      PORT
         LAYER metal4 ;
         RECT  1425.2925 0.0 1425.4325 0.14 ;
      END
   END dout0[419]
   PIN dout0[420]
      DIRECTION OUTPUT ;
      PORT
         LAYER metal4 ;
         RECT  1428.24 0.0 1428.38 0.14 ;
      END
   END dout0[420]
   PIN dout0[421]
      DIRECTION OUTPUT ;
      PORT
         LAYER metal4 ;
         RECT  1431.1 0.0 1431.24 0.14 ;
      END
   END dout0[421]
   PIN dout0[422]
      DIRECTION OUTPUT ;
      PORT
         LAYER metal4 ;
         RECT  1433.96 0.0 1434.1 0.14 ;
      END
   END dout0[422]
   PIN dout0[423]
      DIRECTION OUTPUT ;
      PORT
         LAYER metal4 ;
         RECT  1436.8075 0.0 1436.9475 0.14 ;
      END
   END dout0[423]
   PIN dout0[424]
      DIRECTION OUTPUT ;
      PORT
         LAYER metal4 ;
         RECT  1439.6275 0.0 1439.7675 0.14 ;
      END
   END dout0[424]
   PIN dout0[425]
      DIRECTION OUTPUT ;
      PORT
         LAYER metal4 ;
         RECT  1442.4475 0.0 1442.5875 0.14 ;
      END
   END dout0[425]
   PIN dout0[426]
      DIRECTION OUTPUT ;
      PORT
         LAYER metal4 ;
         RECT  1445.2675 0.0 1445.4075 0.14 ;
      END
   END dout0[426]
   PIN dout0[427]
      DIRECTION OUTPUT ;
      PORT
         LAYER metal4 ;
         RECT  1448.0875 0.0 1448.2275 0.14 ;
      END
   END dout0[427]
   PIN dout0[428]
      DIRECTION OUTPUT ;
      PORT
         LAYER metal4 ;
         RECT  1450.9075 0.0 1451.0475 0.14 ;
      END
   END dout0[428]
   PIN dout0[429]
      DIRECTION OUTPUT ;
      PORT
         LAYER metal4 ;
         RECT  1453.7275 0.0 1453.8675 0.14 ;
      END
   END dout0[429]
   PIN dout0[430]
      DIRECTION OUTPUT ;
      PORT
         LAYER metal4 ;
         RECT  1456.5475 0.0 1456.6875 0.14 ;
      END
   END dout0[430]
   PIN dout0[431]
      DIRECTION OUTPUT ;
      PORT
         LAYER metal4 ;
         RECT  1459.3675 0.0 1459.5075 0.14 ;
      END
   END dout0[431]
   PIN dout0[432]
      DIRECTION OUTPUT ;
      PORT
         LAYER metal4 ;
         RECT  1462.1875 0.0 1462.3275 0.14 ;
      END
   END dout0[432]
   PIN dout0[433]
      DIRECTION OUTPUT ;
      PORT
         LAYER metal4 ;
         RECT  1465.0075 0.0 1465.1475 0.14 ;
      END
   END dout0[433]
   PIN dout0[434]
      DIRECTION OUTPUT ;
      PORT
         LAYER metal4 ;
         RECT  1467.8275 0.0 1467.9675 0.14 ;
      END
   END dout0[434]
   PIN dout0[435]
      DIRECTION OUTPUT ;
      PORT
         LAYER metal4 ;
         RECT  1470.6475 0.0 1470.7875 0.14 ;
      END
   END dout0[435]
   PIN dout0[436]
      DIRECTION OUTPUT ;
      PORT
         LAYER metal4 ;
         RECT  1473.4675 0.0 1473.6075 0.14 ;
      END
   END dout0[436]
   PIN dout0[437]
      DIRECTION OUTPUT ;
      PORT
         LAYER metal4 ;
         RECT  1476.2875 0.0 1476.4275 0.14 ;
      END
   END dout0[437]
   PIN dout0[438]
      DIRECTION OUTPUT ;
      PORT
         LAYER metal4 ;
         RECT  1479.1075 0.0 1479.2475 0.14 ;
      END
   END dout0[438]
   PIN dout0[439]
      DIRECTION OUTPUT ;
      PORT
         LAYER metal4 ;
         RECT  1481.9275 0.0 1482.0675 0.14 ;
      END
   END dout0[439]
   PIN dout0[440]
      DIRECTION OUTPUT ;
      PORT
         LAYER metal4 ;
         RECT  1484.7475 0.0 1484.8875 0.14 ;
      END
   END dout0[440]
   PIN dout0[441]
      DIRECTION OUTPUT ;
      PORT
         LAYER metal4 ;
         RECT  1487.5675 0.0 1487.7075 0.14 ;
      END
   END dout0[441]
   PIN dout0[442]
      DIRECTION OUTPUT ;
      PORT
         LAYER metal4 ;
         RECT  1490.3875 0.0 1490.5275 0.14 ;
      END
   END dout0[442]
   PIN dout0[443]
      DIRECTION OUTPUT ;
      PORT
         LAYER metal4 ;
         RECT  1493.2075 0.0 1493.3475 0.14 ;
      END
   END dout0[443]
   PIN dout0[444]
      DIRECTION OUTPUT ;
      PORT
         LAYER metal4 ;
         RECT  1496.0275 0.0 1496.1675 0.14 ;
      END
   END dout0[444]
   PIN dout0[445]
      DIRECTION OUTPUT ;
      PORT
         LAYER metal4 ;
         RECT  1498.8475 0.0 1498.9875 0.14 ;
      END
   END dout0[445]
   PIN dout0[446]
      DIRECTION OUTPUT ;
      PORT
         LAYER metal4 ;
         RECT  1501.6675 0.0 1501.8075 0.14 ;
      END
   END dout0[446]
   PIN dout0[447]
      DIRECTION OUTPUT ;
      PORT
         LAYER metal4 ;
         RECT  1504.4875 0.0 1504.6275 0.14 ;
      END
   END dout0[447]
   PIN dout0[448]
      DIRECTION OUTPUT ;
      PORT
         LAYER metal4 ;
         RECT  1507.3075 0.0 1507.4475 0.14 ;
      END
   END dout0[448]
   PIN dout0[449]
      DIRECTION OUTPUT ;
      PORT
         LAYER metal4 ;
         RECT  1510.1275 0.0 1510.2675 0.14 ;
      END
   END dout0[449]
   PIN dout0[450]
      DIRECTION OUTPUT ;
      PORT
         LAYER metal4 ;
         RECT  1512.9475 0.0 1513.0875 0.14 ;
      END
   END dout0[450]
   PIN dout0[451]
      DIRECTION OUTPUT ;
      PORT
         LAYER metal4 ;
         RECT  1515.7675 0.0 1515.9075 0.14 ;
      END
   END dout0[451]
   PIN dout0[452]
      DIRECTION OUTPUT ;
      PORT
         LAYER metal4 ;
         RECT  1518.5875 0.0 1518.7275 0.14 ;
      END
   END dout0[452]
   PIN dout0[453]
      DIRECTION OUTPUT ;
      PORT
         LAYER metal4 ;
         RECT  1521.4075 0.0 1521.5475 0.14 ;
      END
   END dout0[453]
   PIN dout0[454]
      DIRECTION OUTPUT ;
      PORT
         LAYER metal4 ;
         RECT  1524.2275 0.0 1524.3675 0.14 ;
      END
   END dout0[454]
   PIN dout0[455]
      DIRECTION OUTPUT ;
      PORT
         LAYER metal4 ;
         RECT  1527.0475 0.0 1527.1875 0.14 ;
      END
   END dout0[455]
   PIN dout0[456]
      DIRECTION OUTPUT ;
      PORT
         LAYER metal4 ;
         RECT  1529.8675 0.0 1530.0075 0.14 ;
      END
   END dout0[456]
   PIN dout0[457]
      DIRECTION OUTPUT ;
      PORT
         LAYER metal4 ;
         RECT  1532.6875 0.0 1532.8275 0.14 ;
      END
   END dout0[457]
   PIN dout0[458]
      DIRECTION OUTPUT ;
      PORT
         LAYER metal4 ;
         RECT  1535.5075 0.0 1535.6475 0.14 ;
      END
   END dout0[458]
   PIN dout0[459]
      DIRECTION OUTPUT ;
      PORT
         LAYER metal4 ;
         RECT  1538.3275 0.0 1538.4675 0.14 ;
      END
   END dout0[459]
   PIN dout0[460]
      DIRECTION OUTPUT ;
      PORT
         LAYER metal4 ;
         RECT  1541.1475 0.0 1541.2875 0.14 ;
      END
   END dout0[460]
   PIN dout0[461]
      DIRECTION OUTPUT ;
      PORT
         LAYER metal4 ;
         RECT  1543.9675 0.0 1544.1075 0.14 ;
      END
   END dout0[461]
   PIN dout0[462]
      DIRECTION OUTPUT ;
      PORT
         LAYER metal4 ;
         RECT  1546.7875 0.0 1546.9275 0.14 ;
      END
   END dout0[462]
   PIN dout0[463]
      DIRECTION OUTPUT ;
      PORT
         LAYER metal4 ;
         RECT  1549.6075 0.0 1549.7475 0.14 ;
      END
   END dout0[463]
   PIN dout0[464]
      DIRECTION OUTPUT ;
      PORT
         LAYER metal4 ;
         RECT  1552.4275 0.0 1552.5675 0.14 ;
      END
   END dout0[464]
   PIN dout0[465]
      DIRECTION OUTPUT ;
      PORT
         LAYER metal4 ;
         RECT  1555.2475 0.0 1555.3875 0.14 ;
      END
   END dout0[465]
   PIN dout0[466]
      DIRECTION OUTPUT ;
      PORT
         LAYER metal4 ;
         RECT  1558.0675 0.0 1558.2075 0.14 ;
      END
   END dout0[466]
   PIN dout0[467]
      DIRECTION OUTPUT ;
      PORT
         LAYER metal4 ;
         RECT  1560.8875 0.0 1561.0275 0.14 ;
      END
   END dout0[467]
   PIN dout0[468]
      DIRECTION OUTPUT ;
      PORT
         LAYER metal4 ;
         RECT  1563.7075 0.0 1563.8475 0.14 ;
      END
   END dout0[468]
   PIN dout0[469]
      DIRECTION OUTPUT ;
      PORT
         LAYER metal4 ;
         RECT  1566.5625 0.0 1566.7025 0.14 ;
      END
   END dout0[469]
   PIN dout0[470]
      DIRECTION OUTPUT ;
      PORT
         LAYER metal4 ;
         RECT  1569.4225 0.0 1569.5625 0.14 ;
      END
   END dout0[470]
   PIN dout0[471]
      DIRECTION OUTPUT ;
      PORT
         LAYER metal4 ;
         RECT  1572.2825 0.0 1572.4225 0.14 ;
      END
   END dout0[471]
   PIN dout0[472]
      DIRECTION OUTPUT ;
      PORT
         LAYER metal4 ;
         RECT  1575.1425 0.0 1575.2825 0.14 ;
      END
   END dout0[472]
   PIN dout0[473]
      DIRECTION OUTPUT ;
      PORT
         LAYER metal4 ;
         RECT  1578.0025 0.0 1578.1425 0.14 ;
      END
   END dout0[473]
   PIN dout0[474]
      DIRECTION OUTPUT ;
      PORT
         LAYER metal4 ;
         RECT  1580.8625 0.0 1581.0025 0.14 ;
      END
   END dout0[474]
   PIN dout0[475]
      DIRECTION OUTPUT ;
      PORT
         LAYER metal4 ;
         RECT  1583.7225 0.0 1583.8625 0.14 ;
      END
   END dout0[475]
   PIN dout0[476]
      DIRECTION OUTPUT ;
      PORT
         LAYER metal4 ;
         RECT  1586.5825 0.0 1586.7225 0.14 ;
      END
   END dout0[476]
   PIN dout0[477]
      DIRECTION OUTPUT ;
      PORT
         LAYER metal4 ;
         RECT  1589.4425 0.0 1589.5825 0.14 ;
      END
   END dout0[477]
   PIN dout0[478]
      DIRECTION OUTPUT ;
      PORT
         LAYER metal4 ;
         RECT  1592.48 0.0 1592.62 0.14 ;
      END
   END dout0[478]
   PIN dout0[479]
      DIRECTION OUTPUT ;
      PORT
         LAYER metal4 ;
         RECT  1595.3 0.0 1595.44 0.14 ;
      END
   END dout0[479]
   PIN dout0[480]
      DIRECTION OUTPUT ;
      PORT
         LAYER metal4 ;
         RECT  1597.55 0.0 1597.69 0.14 ;
      END
   END dout0[480]
   PIN dout0[481]
      DIRECTION OUTPUT ;
      PORT
         LAYER metal4 ;
         RECT  1600.3675 0.0 1600.5075 0.14 ;
      END
   END dout0[481]
   PIN dout0[482]
      DIRECTION OUTPUT ;
      PORT
         LAYER metal4 ;
         RECT  1603.1875 0.0 1603.3275 0.14 ;
      END
   END dout0[482]
   PIN dout0[483]
      DIRECTION OUTPUT ;
      PORT
         LAYER metal4 ;
         RECT  1606.0075 0.0 1606.1475 0.14 ;
      END
   END dout0[483]
   PIN dout0[484]
      DIRECTION OUTPUT ;
      PORT
         LAYER metal4 ;
         RECT  1608.8275 0.0 1608.9675 0.14 ;
      END
   END dout0[484]
   PIN dout0[485]
      DIRECTION OUTPUT ;
      PORT
         LAYER metal4 ;
         RECT  1611.6475 0.0 1611.7875 0.14 ;
      END
   END dout0[485]
   PIN dout0[486]
      DIRECTION OUTPUT ;
      PORT
         LAYER metal4 ;
         RECT  1614.4675 0.0 1614.6075 0.14 ;
      END
   END dout0[486]
   PIN dout0[487]
      DIRECTION OUTPUT ;
      PORT
         LAYER metal4 ;
         RECT  1617.2875 0.0 1617.4275 0.14 ;
      END
   END dout0[487]
   PIN dout0[488]
      DIRECTION OUTPUT ;
      PORT
         LAYER metal4 ;
         RECT  1620.1075 0.0 1620.2475 0.14 ;
      END
   END dout0[488]
   PIN dout0[489]
      DIRECTION OUTPUT ;
      PORT
         LAYER metal4 ;
         RECT  1622.9275 0.0 1623.0675 0.14 ;
      END
   END dout0[489]
   PIN dout0[490]
      DIRECTION OUTPUT ;
      PORT
         LAYER metal4 ;
         RECT  1625.7475 0.0 1625.8875 0.14 ;
      END
   END dout0[490]
   PIN dout0[491]
      DIRECTION OUTPUT ;
      PORT
         LAYER metal4 ;
         RECT  1628.5675 0.0 1628.7075 0.14 ;
      END
   END dout0[491]
   PIN dout0[492]
      DIRECTION OUTPUT ;
      PORT
         LAYER metal4 ;
         RECT  1631.3875 0.0 1631.5275 0.14 ;
      END
   END dout0[492]
   PIN dout0[493]
      DIRECTION OUTPUT ;
      PORT
         LAYER metal4 ;
         RECT  1634.2075 0.0 1634.3475 0.14 ;
      END
   END dout0[493]
   PIN dout0[494]
      DIRECTION OUTPUT ;
      PORT
         LAYER metal4 ;
         RECT  1637.0275 0.0 1637.1675 0.14 ;
      END
   END dout0[494]
   PIN dout0[495]
      DIRECTION OUTPUT ;
      PORT
         LAYER metal4 ;
         RECT  1639.8475 0.0 1639.9875 0.14 ;
      END
   END dout0[495]
   PIN dout0[496]
      DIRECTION OUTPUT ;
      PORT
         LAYER metal4 ;
         RECT  1642.6675 0.0 1642.8075 0.14 ;
      END
   END dout0[496]
   PIN dout0[497]
      DIRECTION OUTPUT ;
      PORT
         LAYER metal4 ;
         RECT  1645.4875 0.0 1645.6275 0.14 ;
      END
   END dout0[497]
   PIN dout0[498]
      DIRECTION OUTPUT ;
      PORT
         LAYER metal4 ;
         RECT  1648.3075 0.0 1648.4475 0.14 ;
      END
   END dout0[498]
   PIN dout0[499]
      DIRECTION OUTPUT ;
      PORT
         LAYER metal4 ;
         RECT  1651.1275 0.0 1651.2675 0.14 ;
      END
   END dout0[499]
   PIN dout0[500]
      DIRECTION OUTPUT ;
      PORT
         LAYER metal4 ;
         RECT  1653.9475 0.0 1654.0875 0.14 ;
      END
   END dout0[500]
   PIN dout0[501]
      DIRECTION OUTPUT ;
      PORT
         LAYER metal4 ;
         RECT  1656.7675 0.0 1656.9075 0.14 ;
      END
   END dout0[501]
   PIN dout0[502]
      DIRECTION OUTPUT ;
      PORT
         LAYER metal4 ;
         RECT  1659.5875 0.0 1659.7275 0.14 ;
      END
   END dout0[502]
   PIN dout0[503]
      DIRECTION OUTPUT ;
      PORT
         LAYER metal4 ;
         RECT  1662.4075 0.0 1662.5475 0.14 ;
      END
   END dout0[503]
   PIN dout0[504]
      DIRECTION OUTPUT ;
      PORT
         LAYER metal4 ;
         RECT  1665.2275 0.0 1665.3675 0.14 ;
      END
   END dout0[504]
   PIN dout0[505]
      DIRECTION OUTPUT ;
      PORT
         LAYER metal4 ;
         RECT  1668.0475 0.0 1668.1875 0.14 ;
      END
   END dout0[505]
   PIN dout0[506]
      DIRECTION OUTPUT ;
      PORT
         LAYER metal3 ;
         RECT  1692.23 23.3875 1692.37 23.5275 ;
      END
   END dout0[506]
   PIN dout0[507]
      DIRECTION OUTPUT ;
      PORT
         LAYER metal3 ;
         RECT  1692.23 23.1525 1692.37 23.2925 ;
      END
   END dout0[507]
   PIN dout0[508]
      DIRECTION OUTPUT ;
      PORT
         LAYER metal3 ;
         RECT  1692.23 22.9175 1692.37 23.0575 ;
      END
   END dout0[508]
   PIN dout0[509]
      DIRECTION OUTPUT ;
      PORT
         LAYER metal3 ;
         RECT  1692.23 22.2125 1692.37 22.3525 ;
      END
   END dout0[509]
   PIN dout0[510]
      DIRECTION OUTPUT ;
      PORT
         LAYER metal3 ;
         RECT  1692.23 22.6825 1692.37 22.8225 ;
      END
   END dout0[510]
   PIN dout0[511]
      DIRECTION OUTPUT ;
      PORT
         LAYER metal3 ;
         RECT  1692.23 22.4475 1692.37 22.5875 ;
      END
   END dout0[511]
   PIN vdd
      DIRECTION INOUT ;
      USE POWER ; 
      SHAPE ABUTMENT ; 
      PORT
         LAYER metal3 ;
         RECT  0.0 740.055 1692.37 740.755 ;
         LAYER metal4 ;
         RECT  1691.67 0.0 1692.37 740.755 ;
         LAYER metal4 ;
         RECT  0.0 0.0 0.7 740.755 ;
         LAYER metal3 ;
         RECT  0.0 0.0 1692.37 0.7 ;
      END
   END vdd
   PIN gnd
      DIRECTION INOUT ;
      USE GROUND ; 
      SHAPE ABUTMENT ; 
      PORT
         LAYER metal4 ;
         RECT  1690.27 1.4 1690.97 739.355 ;
         LAYER metal3 ;
         RECT  1.4 738.655 1690.97 739.355 ;
         LAYER metal3 ;
         RECT  1.4 1.4 1690.97 2.1 ;
         LAYER metal4 ;
         RECT  1.4 1.4 2.1 739.355 ;
      END
   END gnd
   OBS
   LAYER  metal1 ;
      RECT  0.14 0.14 1692.23 740.615 ;
   LAYER  metal2 ;
      RECT  0.14 0.14 1692.23 740.615 ;
   LAYER  metal3 ;
      RECT  0.28 14.38 1692.23 14.8 ;
      RECT  0.14 15.035 0.28 17.11 ;
      RECT  0.28 14.8 1692.09 23.2475 ;
      RECT  0.28 23.2475 1692.09 23.6675 ;
      RECT  1692.09 14.8 1692.23 22.0725 ;
      RECT  0.14 17.53 0.28 739.915 ;
      RECT  1692.09 23.6675 1692.23 739.915 ;
      RECT  0.14 0.84 0.28 14.38 ;
      RECT  0.28 23.6675 1.26 738.515 ;
      RECT  0.28 738.515 1.26 739.495 ;
      RECT  0.28 739.495 1.26 739.915 ;
      RECT  1.26 23.6675 1691.11 738.515 ;
      RECT  1.26 739.495 1691.11 739.915 ;
      RECT  1691.11 23.6675 1692.09 738.515 ;
      RECT  1691.11 738.515 1692.09 739.495 ;
      RECT  1691.11 739.495 1692.09 739.915 ;
      RECT  0.28 0.84 1.26 1.26 ;
      RECT  0.28 1.26 1.26 2.24 ;
      RECT  0.28 2.24 1.26 14.38 ;
      RECT  1.26 0.84 1691.11 1.26 ;
      RECT  1.26 2.24 1691.11 14.38 ;
      RECT  1691.11 0.84 1692.23 1.26 ;
      RECT  1691.11 1.26 1692.23 2.24 ;
      RECT  1691.11 2.24 1692.23 14.38 ;
   LAYER  metal4 ;
      RECT  133.1375 0.42 133.8375 740.615 ;
      RECT  133.8375 0.14 135.9975 0.42 ;
      RECT  136.6975 0.14 138.8575 0.42 ;
      RECT  139.5575 0.14 141.7175 0.42 ;
      RECT  142.4175 0.14 144.5775 0.42 ;
      RECT  145.2775 0.14 147.4375 0.42 ;
      RECT  148.1375 0.14 150.2975 0.42 ;
      RECT  150.9975 0.14 153.1575 0.42 ;
      RECT  153.8575 0.14 156.0175 0.42 ;
      RECT  156.7175 0.14 158.8775 0.42 ;
      RECT  159.5775 0.14 161.7375 0.42 ;
      RECT  162.4375 0.14 164.5975 0.42 ;
      RECT  165.2975 0.14 167.4575 0.42 ;
      RECT  168.1575 0.14 170.3175 0.42 ;
      RECT  171.0175 0.14 173.1775 0.42 ;
      RECT  173.8775 0.14 176.0375 0.42 ;
      RECT  176.7375 0.14 178.8975 0.42 ;
      RECT  179.5975 0.14 181.7575 0.42 ;
      RECT  182.4575 0.14 184.6175 0.42 ;
      RECT  185.3175 0.14 187.4775 0.42 ;
      RECT  188.1775 0.14 190.3375 0.42 ;
      RECT  191.0375 0.14 193.1975 0.42 ;
      RECT  193.8975 0.14 196.0575 0.42 ;
      RECT  196.7575 0.14 198.9175 0.42 ;
      RECT  199.6175 0.14 201.7775 0.42 ;
      RECT  202.4775 0.14 204.6375 0.42 ;
      RECT  205.3375 0.14 207.4975 0.42 ;
      RECT  208.1975 0.14 210.3575 0.42 ;
      RECT  211.0575 0.14 213.2175 0.42 ;
      RECT  213.9175 0.14 216.0775 0.42 ;
      RECT  216.7775 0.14 218.9375 0.42 ;
      RECT  219.6375 0.14 221.7975 0.42 ;
      RECT  222.4975 0.14 224.6575 0.42 ;
      RECT  225.3575 0.14 227.5175 0.42 ;
      RECT  228.2175 0.14 230.3775 0.42 ;
      RECT  231.0775 0.14 233.2375 0.42 ;
      RECT  233.9375 0.14 236.0975 0.42 ;
      RECT  236.7975 0.14 238.9575 0.42 ;
      RECT  239.6575 0.14 241.8175 0.42 ;
      RECT  128.1175 0.14 130.2775 0.42 ;
      RECT  130.9775 0.14 133.1375 0.42 ;
      RECT  123.255 0.14 124.475 0.42 ;
      RECT  125.175 0.14 127.4175 0.42 ;
      RECT  242.5175 0.14 243.6675 0.42 ;
      RECT  244.3675 0.14 244.6775 0.42 ;
      RECT  245.3775 0.14 246.4875 0.42 ;
      RECT  247.1875 0.14 247.5375 0.42 ;
      RECT  248.2375 0.14 249.3075 0.42 ;
      RECT  250.0075 0.14 250.3975 0.42 ;
      RECT  251.0975 0.14 252.1275 0.42 ;
      RECT  252.8275 0.14 253.2575 0.42 ;
      RECT  253.9575 0.14 254.9475 0.42 ;
      RECT  255.6475 0.14 256.1175 0.42 ;
      RECT  256.8175 0.14 257.7675 0.42 ;
      RECT  258.4675 0.14 258.9775 0.42 ;
      RECT  259.6775 0.14 260.5875 0.42 ;
      RECT  261.2875 0.14 261.8375 0.42 ;
      RECT  262.5375 0.14 263.4075 0.42 ;
      RECT  264.1075 0.14 264.6975 0.42 ;
      RECT  265.3975 0.14 266.2275 0.42 ;
      RECT  266.9275 0.14 267.5575 0.42 ;
      RECT  268.2575 0.14 269.0475 0.42 ;
      RECT  269.7475 0.14 270.4175 0.42 ;
      RECT  271.1175 0.14 271.8675 0.42 ;
      RECT  272.5675 0.14 273.2775 0.42 ;
      RECT  273.9775 0.14 274.6875 0.42 ;
      RECT  275.3875 0.14 276.1375 0.42 ;
      RECT  276.8375 0.14 277.5075 0.42 ;
      RECT  278.2075 0.14 278.9975 0.42 ;
      RECT  279.6975 0.14 280.3275 0.42 ;
      RECT  281.0275 0.14 281.8575 0.42 ;
      RECT  282.5575 0.14 283.1475 0.42 ;
      RECT  283.8475 0.14 284.7175 0.42 ;
      RECT  285.4175 0.14 285.9675 0.42 ;
      RECT  286.6675 0.14 287.5775 0.42 ;
      RECT  288.2775 0.14 288.7875 0.42 ;
      RECT  289.4875 0.14 290.4375 0.42 ;
      RECT  291.1375 0.14 291.6075 0.42 ;
      RECT  292.3075 0.14 293.2975 0.42 ;
      RECT  293.9975 0.14 294.4275 0.42 ;
      RECT  295.1275 0.14 296.1575 0.42 ;
      RECT  296.8575 0.14 297.2475 0.42 ;
      RECT  297.9475 0.14 299.0175 0.42 ;
      RECT  299.7175 0.14 300.0675 0.42 ;
      RECT  300.7675 0.14 301.8775 0.42 ;
      RECT  302.5775 0.14 302.8875 0.42 ;
      RECT  303.5875 0.14 304.7375 0.42 ;
      RECT  305.4375 0.14 305.7075 0.42 ;
      RECT  306.4075 0.14 307.5975 0.42 ;
      RECT  308.2975 0.14 308.5275 0.42 ;
      RECT  309.2275 0.14 310.4575 0.42 ;
      RECT  311.1575 0.14 311.3475 0.42 ;
      RECT  312.0475 0.14 313.3175 0.42 ;
      RECT  314.0175 0.14 314.1675 0.42 ;
      RECT  314.8675 0.14 316.1775 0.42 ;
      RECT  316.8775 0.14 316.9875 0.42 ;
      RECT  317.6875 0.14 319.0375 0.42 ;
      RECT  319.7375 0.14 319.8075 0.42 ;
      RECT  320.5075 0.14 321.8975 0.42 ;
      RECT  322.5975 0.14 322.6275 0.42 ;
      RECT  323.3275 0.14 324.7575 0.42 ;
      RECT  326.1475 0.14 327.6175 0.42 ;
      RECT  328.9675 0.14 330.4775 0.42 ;
      RECT  331.7875 0.14 333.3375 0.42 ;
      RECT  334.6075 0.14 336.1975 0.42 ;
      RECT  337.4275 0.14 339.0575 0.42 ;
      RECT  340.2475 0.14 341.9175 0.42 ;
      RECT  343.0675 0.14 344.7775 0.42 ;
      RECT  345.8875 0.14 347.6375 0.42 ;
      RECT  348.7075 0.14 350.4975 0.42 ;
      RECT  351.5275 0.14 353.3575 0.42 ;
      RECT  354.3475 0.14 356.2175 0.42 ;
      RECT  357.2025 0.14 359.0775 0.42 ;
      RECT  360.0625 0.14 361.9375 0.42 ;
      RECT  362.9225 0.14 364.7975 0.42 ;
      RECT  365.7825 0.14 367.6575 0.42 ;
      RECT  368.6425 0.14 370.5175 0.42 ;
      RECT  371.5025 0.14 373.3775 0.42 ;
      RECT  374.3625 0.14 376.2375 0.42 ;
      RECT  377.2225 0.14 379.0975 0.42 ;
      RECT  380.0825 0.14 381.9575 0.42 ;
      RECT  383.12 0.14 384.8175 0.42 ;
      RECT  385.94 0.14 386.92 0.42 ;
      RECT  387.62 0.14 387.6775 0.42 ;
      RECT  388.3775 0.14 389.78 0.42 ;
      RECT  390.48 0.14 390.5375 0.42 ;
      RECT  391.2375 0.14 392.64 0.42 ;
      RECT  393.34 0.14 393.3975 0.42 ;
      RECT  394.0975 0.14 395.5 0.42 ;
      RECT  396.2 0.14 396.2575 0.42 ;
      RECT  396.9575 0.14 398.36 0.42 ;
      RECT  399.06 0.14 399.1175 0.42 ;
      RECT  399.8175 0.14 401.22 0.42 ;
      RECT  401.92 0.14 401.9775 0.42 ;
      RECT  402.6775 0.14 404.08 0.42 ;
      RECT  404.78 0.14 404.8375 0.42 ;
      RECT  405.5375 0.14 406.94 0.42 ;
      RECT  407.64 0.14 407.6975 0.42 ;
      RECT  408.3975 0.14 409.8 0.42 ;
      RECT  410.5 0.14 410.5575 0.42 ;
      RECT  411.2575 0.14 412.6325 0.42 ;
      RECT  413.3325 0.14 413.4175 0.42 ;
      RECT  414.1175 0.14 415.4525 0.42 ;
      RECT  416.1525 0.14 416.2775 0.42 ;
      RECT  416.9775 0.14 418.38 0.42 ;
      RECT  419.08 0.14 419.1375 0.42 ;
      RECT  419.8375 0.14 421.24 0.42 ;
      RECT  421.94 0.14 421.9975 0.42 ;
      RECT  422.6975 0.14 424.1 0.42 ;
      RECT  424.8 0.14 424.8575 0.42 ;
      RECT  425.5575 0.14 426.96 0.42 ;
      RECT  427.66 0.14 427.7175 0.42 ;
      RECT  428.4175 0.14 429.7875 0.42 ;
      RECT  430.4875 0.14 430.5775 0.42 ;
      RECT  431.2775 0.14 432.6075 0.42 ;
      RECT  433.3075 0.14 433.4375 0.42 ;
      RECT  434.1375 0.14 435.4275 0.42 ;
      RECT  436.1275 0.14 436.2975 0.42 ;
      RECT  436.9975 0.14 438.2475 0.42 ;
      RECT  438.9475 0.14 439.1575 0.42 ;
      RECT  439.8575 0.14 441.0675 0.42 ;
      RECT  441.7675 0.14 442.0175 0.42 ;
      RECT  442.7175 0.14 443.8875 0.42 ;
      RECT  444.5875 0.14 444.8775 0.42 ;
      RECT  445.5775 0.14 446.7075 0.42 ;
      RECT  447.4075 0.14 447.7375 0.42 ;
      RECT  448.4375 0.14 449.5275 0.42 ;
      RECT  450.2275 0.14 450.5975 0.42 ;
      RECT  451.2975 0.14 452.3475 0.42 ;
      RECT  453.0475 0.14 453.4575 0.42 ;
      RECT  454.1575 0.14 455.1675 0.42 ;
      RECT  455.8675 0.14 456.3175 0.42 ;
      RECT  457.0175 0.14 457.9875 0.42 ;
      RECT  458.6875 0.14 459.1775 0.42 ;
      RECT  459.8775 0.14 460.8075 0.42 ;
      RECT  461.5075 0.14 462.0375 0.42 ;
      RECT  462.7375 0.14 463.6275 0.42 ;
      RECT  464.3275 0.14 464.8975 0.42 ;
      RECT  465.5975 0.14 466.4475 0.42 ;
      RECT  467.1475 0.14 467.7575 0.42 ;
      RECT  468.4575 0.14 469.2675 0.42 ;
      RECT  469.9675 0.14 470.6175 0.42 ;
      RECT  471.3175 0.14 472.0875 0.42 ;
      RECT  472.7875 0.14 473.4775 0.42 ;
      RECT  474.1775 0.14 474.9075 0.42 ;
      RECT  475.6075 0.14 476.3375 0.42 ;
      RECT  477.0375 0.14 477.7275 0.42 ;
      RECT  478.4275 0.14 479.1975 0.42 ;
      RECT  479.8975 0.14 480.5475 0.42 ;
      RECT  481.2475 0.14 482.0575 0.42 ;
      RECT  482.7575 0.14 483.3675 0.42 ;
      RECT  484.0675 0.14 484.9175 0.42 ;
      RECT  485.6175 0.14 486.1875 0.42 ;
      RECT  486.8875 0.14 487.7775 0.42 ;
      RECT  488.4775 0.14 489.0075 0.42 ;
      RECT  489.7075 0.14 490.6375 0.42 ;
      RECT  491.3375 0.14 491.8275 0.42 ;
      RECT  492.5275 0.14 493.4975 0.42 ;
      RECT  494.1975 0.14 494.6475 0.42 ;
      RECT  495.3475 0.14 496.3575 0.42 ;
      RECT  497.0575 0.14 497.4675 0.42 ;
      RECT  498.1675 0.14 499.2175 0.42 ;
      RECT  499.9175 0.14 500.2875 0.42 ;
      RECT  500.9875 0.14 502.0775 0.42 ;
      RECT  502.7775 0.14 503.1075 0.42 ;
      RECT  503.8075 0.14 504.9375 0.42 ;
      RECT  505.6375 0.14 505.9275 0.42 ;
      RECT  506.6275 0.14 507.7975 0.42 ;
      RECT  508.4975 0.14 508.7475 0.42 ;
      RECT  509.4475 0.14 510.6575 0.42 ;
      RECT  511.3575 0.14 511.5675 0.42 ;
      RECT  512.2675 0.14 513.5175 0.42 ;
      RECT  514.2175 0.14 514.3875 0.42 ;
      RECT  515.0875 0.14 516.3775 0.42 ;
      RECT  517.0775 0.14 517.2075 0.42 ;
      RECT  517.9075 0.14 519.2375 0.42 ;
      RECT  519.9375 0.14 520.0275 0.42 ;
      RECT  520.7275 0.14 522.0975 0.42 ;
      RECT  522.7975 0.14 522.8475 0.42 ;
      RECT  523.5475 0.14 524.9575 0.42 ;
      RECT  525.6575 0.14 525.6675 0.42 ;
      RECT  526.3675 0.14 527.8175 0.42 ;
      RECT  529.1875 0.14 530.6775 0.42 ;
      RECT  532.0075 0.14 533.5375 0.42 ;
      RECT  534.8275 0.14 536.3975 0.42 ;
      RECT  537.6475 0.14 539.2575 0.42 ;
      RECT  540.4675 0.14 542.1175 0.42 ;
      RECT  543.2875 0.14 544.9775 0.42 ;
      RECT  546.1075 0.14 547.8375 0.42 ;
      RECT  548.9275 0.14 550.6975 0.42 ;
      RECT  551.7475 0.14 553.5575 0.42 ;
      RECT  554.5675 0.14 556.4175 0.42 ;
      RECT  557.4025 0.14 559.2775 0.42 ;
      RECT  560.28 0.14 562.1375 0.42 ;
      RECT  563.1225 0.14 564.9975 0.42 ;
      RECT  565.9825 0.14 567.8575 0.42 ;
      RECT  568.8425 0.14 570.7175 0.42 ;
      RECT  571.7025 0.14 573.5775 0.42 ;
      RECT  574.5625 0.14 576.4375 0.42 ;
      RECT  577.4225 0.14 579.2975 0.42 ;
      RECT  580.2825 0.14 582.1575 0.42 ;
      RECT  583.34 0.14 585.0175 0.42 ;
      RECT  586.16 0.14 587.8775 0.42 ;
      RECT  588.98 0.14 589.98 0.42 ;
      RECT  590.68 0.14 590.7375 0.42 ;
      RECT  591.4375 0.14 592.84 0.42 ;
      RECT  593.54 0.14 593.5975 0.42 ;
      RECT  594.2975 0.14 595.7 0.42 ;
      RECT  596.4 0.14 596.4575 0.42 ;
      RECT  597.1575 0.14 598.56 0.42 ;
      RECT  599.26 0.14 599.3175 0.42 ;
      RECT  600.0175 0.14 601.42 0.42 ;
      RECT  602.12 0.14 602.1775 0.42 ;
      RECT  602.8775 0.14 604.28 0.42 ;
      RECT  604.98 0.14 605.0375 0.42 ;
      RECT  605.7375 0.14 607.14 0.42 ;
      RECT  607.84 0.14 607.8975 0.42 ;
      RECT  608.5975 0.14 610.0 0.42 ;
      RECT  610.7 0.14 610.7575 0.42 ;
      RECT  611.4575 0.14 612.8525 0.42 ;
      RECT  613.5525 0.14 613.6175 0.42 ;
      RECT  614.3175 0.14 615.6725 0.42 ;
      RECT  616.3725 0.14 616.4775 0.42 ;
      RECT  617.1775 0.14 618.4925 0.42 ;
      RECT  619.1925 0.14 619.3375 0.42 ;
      RECT  620.0375 0.14 621.44 0.42 ;
      RECT  622.14 0.14 622.1975 0.42 ;
      RECT  622.8975 0.14 624.3 0.42 ;
      RECT  625.0 0.14 625.0575 0.42 ;
      RECT  625.7575 0.14 627.16 0.42 ;
      RECT  627.86 0.14 627.9175 0.42 ;
      RECT  628.6175 0.14 630.0075 0.42 ;
      RECT  630.7075 0.14 630.7775 0.42 ;
      RECT  631.4775 0.14 632.8275 0.42 ;
      RECT  633.5275 0.14 633.6375 0.42 ;
      RECT  634.3375 0.14 635.6475 0.42 ;
      RECT  636.3475 0.14 636.4975 0.42 ;
      RECT  637.1975 0.14 638.4675 0.42 ;
      RECT  639.1675 0.14 639.3575 0.42 ;
      RECT  640.0575 0.14 641.2875 0.42 ;
      RECT  641.9875 0.14 642.2175 0.42 ;
      RECT  642.9175 0.14 644.1075 0.42 ;
      RECT  644.8075 0.14 645.0775 0.42 ;
      RECT  645.7775 0.14 646.9275 0.42 ;
      RECT  647.6275 0.14 647.9375 0.42 ;
      RECT  648.6375 0.14 649.7475 0.42 ;
      RECT  650.4475 0.14 650.7975 0.42 ;
      RECT  651.4975 0.14 652.5675 0.42 ;
      RECT  653.2675 0.14 653.6575 0.42 ;
      RECT  654.3575 0.14 655.3875 0.42 ;
      RECT  656.0875 0.14 656.5175 0.42 ;
      RECT  657.2175 0.14 658.2075 0.42 ;
      RECT  658.9075 0.14 659.3775 0.42 ;
      RECT  660.0775 0.14 661.0275 0.42 ;
      RECT  661.7275 0.14 662.2375 0.42 ;
      RECT  662.9375 0.14 663.8475 0.42 ;
      RECT  664.5475 0.14 665.0975 0.42 ;
      RECT  665.7975 0.14 666.6675 0.42 ;
      RECT  667.3675 0.14 667.9575 0.42 ;
      RECT  668.6575 0.14 669.4875 0.42 ;
      RECT  670.1875 0.14 670.8175 0.42 ;
      RECT  671.5175 0.14 672.3075 0.42 ;
      RECT  673.0075 0.14 673.6775 0.42 ;
      RECT  674.3775 0.14 675.1275 0.42 ;
      RECT  675.8275 0.14 676.5375 0.42 ;
      RECT  677.2375 0.14 677.9475 0.42 ;
      RECT  678.6475 0.14 679.3975 0.42 ;
      RECT  680.0975 0.14 680.7675 0.42 ;
      RECT  681.4675 0.14 682.2575 0.42 ;
      RECT  682.9575 0.14 683.5875 0.42 ;
      RECT  684.2875 0.14 685.1175 0.42 ;
      RECT  685.8175 0.14 686.4075 0.42 ;
      RECT  687.1075 0.14 687.9775 0.42 ;
      RECT  688.6775 0.14 689.2275 0.42 ;
      RECT  689.9275 0.14 690.8375 0.42 ;
      RECT  691.5375 0.14 692.0475 0.42 ;
      RECT  692.7475 0.14 693.6975 0.42 ;
      RECT  694.3975 0.14 694.8675 0.42 ;
      RECT  695.5675 0.14 696.5575 0.42 ;
      RECT  697.2575 0.14 697.6875 0.42 ;
      RECT  698.3875 0.14 699.4175 0.42 ;
      RECT  700.1175 0.14 700.5075 0.42 ;
      RECT  701.2075 0.14 702.2775 0.42 ;
      RECT  702.9775 0.14 703.3275 0.42 ;
      RECT  704.0275 0.14 705.1375 0.42 ;
      RECT  705.8375 0.14 706.1475 0.42 ;
      RECT  706.8475 0.14 707.9975 0.42 ;
      RECT  708.6975 0.14 708.9675 0.42 ;
      RECT  709.6675 0.14 710.8575 0.42 ;
      RECT  711.5575 0.14 711.7875 0.42 ;
      RECT  712.4875 0.14 713.7175 0.42 ;
      RECT  714.4175 0.14 714.6075 0.42 ;
      RECT  715.3075 0.14 716.5775 0.42 ;
      RECT  717.2775 0.14 717.4275 0.42 ;
      RECT  718.1275 0.14 719.4375 0.42 ;
      RECT  720.1375 0.14 720.2475 0.42 ;
      RECT  720.9475 0.14 722.2975 0.42 ;
      RECT  722.9975 0.14 723.0675 0.42 ;
      RECT  723.7675 0.14 725.1575 0.42 ;
      RECT  725.8575 0.14 725.8875 0.42 ;
      RECT  726.5875 0.14 728.0175 0.42 ;
      RECT  729.4075 0.14 730.8775 0.42 ;
      RECT  732.2275 0.14 733.7375 0.42 ;
      RECT  735.0475 0.14 736.5975 0.42 ;
      RECT  737.8675 0.14 739.4575 0.42 ;
      RECT  740.6875 0.14 742.3175 0.42 ;
      RECT  743.5075 0.14 745.1775 0.42 ;
      RECT  746.3275 0.14 748.0375 0.42 ;
      RECT  749.1475 0.14 750.8975 0.42 ;
      RECT  751.9675 0.14 753.7575 0.42 ;
      RECT  754.7875 0.14 756.6175 0.42 ;
      RECT  757.6075 0.14 759.4775 0.42 ;
      RECT  760.4625 0.14 762.3375 0.42 ;
      RECT  763.3225 0.14 765.1975 0.42 ;
      RECT  766.1825 0.14 768.0575 0.42 ;
      RECT  769.0425 0.14 770.9175 0.42 ;
      RECT  771.9025 0.14 773.7775 0.42 ;
      RECT  774.7625 0.14 776.6375 0.42 ;
      RECT  777.6225 0.14 779.4975 0.42 ;
      RECT  780.4825 0.14 782.3575 0.42 ;
      RECT  783.3425 0.14 785.2175 0.42 ;
      RECT  786.38 0.14 788.0775 0.42 ;
      RECT  789.2 0.14 790.18 0.42 ;
      RECT  790.88 0.14 790.9375 0.42 ;
      RECT  791.6375 0.14 793.04 0.42 ;
      RECT  793.74 0.14 793.7975 0.42 ;
      RECT  794.4975 0.14 795.9 0.42 ;
      RECT  796.6 0.14 796.6575 0.42 ;
      RECT  797.3575 0.14 798.76 0.42 ;
      RECT  799.46 0.14 799.5175 0.42 ;
      RECT  800.2175 0.14 801.62 0.42 ;
      RECT  802.32 0.14 802.3775 0.42 ;
      RECT  803.0775 0.14 804.48 0.42 ;
      RECT  805.18 0.14 805.2375 0.42 ;
      RECT  805.9375 0.14 807.34 0.42 ;
      RECT  808.04 0.14 808.0975 0.42 ;
      RECT  808.7975 0.14 810.2 0.42 ;
      RECT  810.9 0.14 810.9575 0.42 ;
      RECT  811.6575 0.14 813.06 0.42 ;
      RECT  813.76 0.14 813.8175 0.42 ;
      RECT  814.5175 0.14 815.8925 0.42 ;
      RECT  816.5925 0.14 816.6775 0.42 ;
      RECT  817.3775 0.14 818.7125 0.42 ;
      RECT  819.4125 0.14 819.5375 0.42 ;
      RECT  820.2375 0.14 821.64 0.42 ;
      RECT  822.34 0.14 822.3975 0.42 ;
      RECT  823.0975 0.14 824.5 0.42 ;
      RECT  825.2 0.14 825.2575 0.42 ;
      RECT  825.9575 0.14 827.36 0.42 ;
      RECT  828.06 0.14 828.1175 0.42 ;
      RECT  828.8175 0.14 830.22 0.42 ;
      RECT  830.92 0.14 830.9775 0.42 ;
      RECT  831.6775 0.14 833.0475 0.42 ;
      RECT  833.7475 0.14 833.8375 0.42 ;
      RECT  834.5375 0.14 835.8675 0.42 ;
      RECT  836.5675 0.14 836.6975 0.42 ;
      RECT  837.3975 0.14 838.6875 0.42 ;
      RECT  839.3875 0.14 839.5575 0.42 ;
      RECT  840.2575 0.14 841.5075 0.42 ;
      RECT  842.2075 0.14 842.4175 0.42 ;
      RECT  843.1175 0.14 844.3275 0.42 ;
      RECT  845.0275 0.14 845.2775 0.42 ;
      RECT  845.9775 0.14 847.1475 0.42 ;
      RECT  847.8475 0.14 848.1375 0.42 ;
      RECT  848.8375 0.14 849.9675 0.42 ;
      RECT  850.6675 0.14 850.9975 0.42 ;
      RECT  851.6975 0.14 852.7875 0.42 ;
      RECT  853.4875 0.14 853.8575 0.42 ;
      RECT  854.5575 0.14 855.6075 0.42 ;
      RECT  856.3075 0.14 856.7175 0.42 ;
      RECT  857.4175 0.14 858.4275 0.42 ;
      RECT  859.1275 0.14 859.5775 0.42 ;
      RECT  860.2775 0.14 861.2475 0.42 ;
      RECT  861.9475 0.14 862.4375 0.42 ;
      RECT  863.1375 0.14 864.0675 0.42 ;
      RECT  864.7675 0.14 865.2975 0.42 ;
      RECT  865.9975 0.14 866.8875 0.42 ;
      RECT  867.5875 0.14 868.1575 0.42 ;
      RECT  868.8575 0.14 869.7075 0.42 ;
      RECT  870.4075 0.14 871.0175 0.42 ;
      RECT  871.7175 0.14 872.5275 0.42 ;
      RECT  873.2275 0.14 873.8775 0.42 ;
      RECT  874.5775 0.14 875.3475 0.42 ;
      RECT  876.0475 0.14 876.7375 0.42 ;
      RECT  877.4375 0.14 878.1675 0.42 ;
      RECT  878.8675 0.14 879.5975 0.42 ;
      RECT  880.2975 0.14 880.9875 0.42 ;
      RECT  881.6875 0.14 882.4575 0.42 ;
      RECT  883.1575 0.14 883.8075 0.42 ;
      RECT  884.5075 0.14 885.3175 0.42 ;
      RECT  886.0175 0.14 886.6275 0.42 ;
      RECT  887.3275 0.14 888.1775 0.42 ;
      RECT  888.8775 0.14 889.4475 0.42 ;
      RECT  890.1475 0.14 891.0375 0.42 ;
      RECT  891.7375 0.14 892.2675 0.42 ;
      RECT  892.9675 0.14 893.8975 0.42 ;
      RECT  894.5975 0.14 895.0875 0.42 ;
      RECT  895.7875 0.14 896.7575 0.42 ;
      RECT  897.4575 0.14 897.9075 0.42 ;
      RECT  898.6075 0.14 899.6175 0.42 ;
      RECT  900.3175 0.14 900.7275 0.42 ;
      RECT  901.4275 0.14 902.4775 0.42 ;
      RECT  903.1775 0.14 903.5475 0.42 ;
      RECT  904.2475 0.14 905.3375 0.42 ;
      RECT  906.0375 0.14 906.3675 0.42 ;
      RECT  907.0675 0.14 908.1975 0.42 ;
      RECT  908.8975 0.14 909.1875 0.42 ;
      RECT  909.8875 0.14 911.0575 0.42 ;
      RECT  911.7575 0.14 912.0075 0.42 ;
      RECT  912.7075 0.14 913.9175 0.42 ;
      RECT  914.6175 0.14 914.8275 0.42 ;
      RECT  915.5275 0.14 916.7775 0.42 ;
      RECT  917.4775 0.14 917.6475 0.42 ;
      RECT  918.3475 0.14 919.6375 0.42 ;
      RECT  920.3375 0.14 920.4675 0.42 ;
      RECT  921.1675 0.14 922.4975 0.42 ;
      RECT  923.1975 0.14 923.2875 0.42 ;
      RECT  923.9875 0.14 925.3575 0.42 ;
      RECT  926.0575 0.14 926.1075 0.42 ;
      RECT  926.8075 0.14 928.2175 0.42 ;
      RECT  928.9175 0.14 928.9275 0.42 ;
      RECT  929.6275 0.14 931.0775 0.42 ;
      RECT  932.4475 0.14 933.9375 0.42 ;
      RECT  935.2675 0.14 936.7975 0.42 ;
      RECT  938.0875 0.14 939.6575 0.42 ;
      RECT  940.9075 0.14 942.5175 0.42 ;
      RECT  943.7275 0.14 945.3775 0.42 ;
      RECT  946.5475 0.14 948.2375 0.42 ;
      RECT  949.3675 0.14 951.0975 0.42 ;
      RECT  952.1875 0.14 953.9575 0.42 ;
      RECT  955.0075 0.14 956.8175 0.42 ;
      RECT  957.8275 0.14 959.6775 0.42 ;
      RECT  960.6625 0.14 962.5375 0.42 ;
      RECT  963.54 0.14 965.3975 0.42 ;
      RECT  966.3825 0.14 968.2575 0.42 ;
      RECT  969.2425 0.14 971.1175 0.42 ;
      RECT  972.1025 0.14 973.9775 0.42 ;
      RECT  974.9625 0.14 976.8375 0.42 ;
      RECT  977.8225 0.14 979.6975 0.42 ;
      RECT  980.6825 0.14 982.5575 0.42 ;
      RECT  983.5425 0.14 985.4175 0.42 ;
      RECT  986.6 0.14 988.2775 0.42 ;
      RECT  989.42 0.14 991.1375 0.42 ;
      RECT  992.24 0.14 993.24 0.42 ;
      RECT  993.94 0.14 993.9975 0.42 ;
      RECT  994.6975 0.14 996.1 0.42 ;
      RECT  996.8 0.14 996.8575 0.42 ;
      RECT  997.5575 0.14 998.96 0.42 ;
      RECT  999.66 0.14 999.7175 0.42 ;
      RECT  1000.4175 0.14 1001.82 0.42 ;
      RECT  1002.52 0.14 1002.5775 0.42 ;
      RECT  1003.2775 0.14 1004.68 0.42 ;
      RECT  1005.38 0.14 1005.4375 0.42 ;
      RECT  1006.1375 0.14 1007.54 0.42 ;
      RECT  1008.24 0.14 1008.2975 0.42 ;
      RECT  1008.9975 0.14 1010.4 0.42 ;
      RECT  1011.1 0.14 1011.1575 0.42 ;
      RECT  1011.8575 0.14 1013.26 0.42 ;
      RECT  1013.96 0.14 1014.0175 0.42 ;
      RECT  1014.7175 0.14 1016.1125 0.42 ;
      RECT  1016.8125 0.14 1016.8775 0.42 ;
      RECT  1017.5775 0.14 1018.9325 0.42 ;
      RECT  1019.6325 0.14 1019.7375 0.42 ;
      RECT  1020.4375 0.14 1021.7525 0.42 ;
      RECT  1022.4525 0.14 1022.5975 0.42 ;
      RECT  1023.2975 0.14 1024.7 0.42 ;
      RECT  1025.4 0.14 1025.4575 0.42 ;
      RECT  1026.1575 0.14 1027.56 0.42 ;
      RECT  1028.26 0.14 1028.3175 0.42 ;
      RECT  1029.0175 0.14 1030.42 0.42 ;
      RECT  1031.12 0.14 1031.1775 0.42 ;
      RECT  1031.8775 0.14 1033.2675 0.42 ;
      RECT  1033.9675 0.14 1034.0375 0.42 ;
      RECT  1034.7375 0.14 1036.0875 0.42 ;
      RECT  1036.7875 0.14 1036.8975 0.42 ;
      RECT  1037.5975 0.14 1038.9075 0.42 ;
      RECT  1039.6075 0.14 1039.7575 0.42 ;
      RECT  1040.4575 0.14 1041.7275 0.42 ;
      RECT  1042.4275 0.14 1042.6175 0.42 ;
      RECT  1043.3175 0.14 1044.5475 0.42 ;
      RECT  1045.2475 0.14 1045.4775 0.42 ;
      RECT  1046.1775 0.14 1047.3675 0.42 ;
      RECT  1048.0675 0.14 1048.3375 0.42 ;
      RECT  1049.0375 0.14 1050.1875 0.42 ;
      RECT  1050.8875 0.14 1051.1975 0.42 ;
      RECT  1051.8975 0.14 1053.0075 0.42 ;
      RECT  1053.7075 0.14 1054.0575 0.42 ;
      RECT  1054.7575 0.14 1055.8275 0.42 ;
      RECT  1056.5275 0.14 1056.9175 0.42 ;
      RECT  1057.6175 0.14 1058.6475 0.42 ;
      RECT  1059.3475 0.14 1059.7775 0.42 ;
      RECT  1060.4775 0.14 1061.4675 0.42 ;
      RECT  1062.1675 0.14 1062.6375 0.42 ;
      RECT  1063.3375 0.14 1064.2875 0.42 ;
      RECT  1064.9875 0.14 1065.4975 0.42 ;
      RECT  1066.1975 0.14 1067.1075 0.42 ;
      RECT  1067.8075 0.14 1068.3575 0.42 ;
      RECT  1069.0575 0.14 1069.9275 0.42 ;
      RECT  1070.6275 0.14 1071.2175 0.42 ;
      RECT  1071.9175 0.14 1072.7475 0.42 ;
      RECT  1073.4475 0.14 1074.0775 0.42 ;
      RECT  1074.7775 0.14 1075.5675 0.42 ;
      RECT  1076.2675 0.14 1076.9375 0.42 ;
      RECT  1077.6375 0.14 1078.3875 0.42 ;
      RECT  1079.0875 0.14 1079.7975 0.42 ;
      RECT  1080.4975 0.14 1081.2075 0.42 ;
      RECT  1081.9075 0.14 1082.6575 0.42 ;
      RECT  1083.3575 0.14 1084.0275 0.42 ;
      RECT  1084.7275 0.14 1085.5175 0.42 ;
      RECT  1086.2175 0.14 1086.8475 0.42 ;
      RECT  1087.5475 0.14 1088.3775 0.42 ;
      RECT  1089.0775 0.14 1089.6675 0.42 ;
      RECT  1090.3675 0.14 1091.2375 0.42 ;
      RECT  1091.9375 0.14 1092.4875 0.42 ;
      RECT  1093.1875 0.14 1094.0975 0.42 ;
      RECT  1094.7975 0.14 1095.3075 0.42 ;
      RECT  1096.0075 0.14 1096.9575 0.42 ;
      RECT  1097.6575 0.14 1098.1275 0.42 ;
      RECT  1098.8275 0.14 1099.8175 0.42 ;
      RECT  1100.5175 0.14 1100.9475 0.42 ;
      RECT  1101.6475 0.14 1102.6775 0.42 ;
      RECT  1103.3775 0.14 1103.7675 0.42 ;
      RECT  1104.4675 0.14 1105.5375 0.42 ;
      RECT  1106.2375 0.14 1106.5875 0.42 ;
      RECT  1107.2875 0.14 1108.3975 0.42 ;
      RECT  1109.0975 0.14 1109.4075 0.42 ;
      RECT  1110.1075 0.14 1111.2575 0.42 ;
      RECT  1111.9575 0.14 1112.2275 0.42 ;
      RECT  1112.9275 0.14 1114.1175 0.42 ;
      RECT  1114.8175 0.14 1115.0475 0.42 ;
      RECT  1115.7475 0.14 1116.9775 0.42 ;
      RECT  1117.6775 0.14 1117.8675 0.42 ;
      RECT  1118.5675 0.14 1119.8375 0.42 ;
      RECT  1120.5375 0.14 1120.6875 0.42 ;
      RECT  1121.3875 0.14 1122.6975 0.42 ;
      RECT  1123.3975 0.14 1123.5075 0.42 ;
      RECT  1124.2075 0.14 1125.5575 0.42 ;
      RECT  1126.2575 0.14 1126.3275 0.42 ;
      RECT  1127.0275 0.14 1128.4175 0.42 ;
      RECT  1129.1175 0.14 1129.1475 0.42 ;
      RECT  1129.8475 0.14 1131.2775 0.42 ;
      RECT  1132.6675 0.14 1134.1375 0.42 ;
      RECT  1135.4875 0.14 1136.9975 0.42 ;
      RECT  1138.3075 0.14 1139.8575 0.42 ;
      RECT  1141.1275 0.14 1142.7175 0.42 ;
      RECT  1143.9475 0.14 1145.5775 0.42 ;
      RECT  1146.7675 0.14 1148.4375 0.42 ;
      RECT  1149.5875 0.14 1151.2975 0.42 ;
      RECT  1152.4075 0.14 1154.1575 0.42 ;
      RECT  1155.2275 0.14 1157.0175 0.42 ;
      RECT  1158.0475 0.14 1159.8775 0.42 ;
      RECT  1160.8675 0.14 1162.7375 0.42 ;
      RECT  1163.7225 0.14 1165.5975 0.42 ;
      RECT  1166.5825 0.14 1168.4575 0.42 ;
      RECT  1169.4425 0.14 1171.3175 0.42 ;
      RECT  1172.3025 0.14 1174.1775 0.42 ;
      RECT  1175.1625 0.14 1177.0375 0.42 ;
      RECT  1178.0225 0.14 1179.8975 0.42 ;
      RECT  1180.8825 0.14 1182.7575 0.42 ;
      RECT  1183.7425 0.14 1185.6175 0.42 ;
      RECT  1186.6025 0.14 1188.4775 0.42 ;
      RECT  1189.64 0.14 1191.3375 0.42 ;
      RECT  1192.46 0.14 1193.44 0.42 ;
      RECT  1194.14 0.14 1194.1975 0.42 ;
      RECT  1194.8975 0.14 1196.3 0.42 ;
      RECT  1197.0 0.14 1197.0575 0.42 ;
      RECT  1197.7575 0.14 1199.16 0.42 ;
      RECT  1199.86 0.14 1199.9175 0.42 ;
      RECT  1200.6175 0.14 1202.02 0.42 ;
      RECT  1202.72 0.14 1202.7775 0.42 ;
      RECT  1203.4775 0.14 1204.88 0.42 ;
      RECT  1205.58 0.14 1205.6375 0.42 ;
      RECT  1206.3375 0.14 1207.74 0.42 ;
      RECT  1208.44 0.14 1208.4975 0.42 ;
      RECT  1209.1975 0.14 1210.6 0.42 ;
      RECT  1211.3 0.14 1211.3575 0.42 ;
      RECT  1212.0575 0.14 1213.46 0.42 ;
      RECT  1214.16 0.14 1214.2175 0.42 ;
      RECT  1214.9175 0.14 1216.32 0.42 ;
      RECT  1217.02 0.14 1217.0775 0.42 ;
      RECT  1217.7775 0.14 1219.1525 0.42 ;
      RECT  1219.8525 0.14 1219.9375 0.42 ;
      RECT  1220.6375 0.14 1221.9725 0.42 ;
      RECT  1222.6725 0.14 1222.7975 0.42 ;
      RECT  1223.4975 0.14 1224.9 0.42 ;
      RECT  1225.6 0.14 1225.6575 0.42 ;
      RECT  1226.3575 0.14 1227.76 0.42 ;
      RECT  1228.46 0.14 1228.5175 0.42 ;
      RECT  1229.2175 0.14 1230.62 0.42 ;
      RECT  1231.32 0.14 1231.3775 0.42 ;
      RECT  1232.0775 0.14 1233.48 0.42 ;
      RECT  1234.18 0.14 1234.2375 0.42 ;
      RECT  1234.9375 0.14 1236.3075 0.42 ;
      RECT  1237.0075 0.14 1237.0975 0.42 ;
      RECT  1237.7975 0.14 1239.1275 0.42 ;
      RECT  1239.8275 0.14 1239.9575 0.42 ;
      RECT  1240.6575 0.14 1241.9475 0.42 ;
      RECT  1242.6475 0.14 1242.8175 0.42 ;
      RECT  1243.5175 0.14 1244.7675 0.42 ;
      RECT  1245.4675 0.14 1245.6775 0.42 ;
      RECT  1246.3775 0.14 1247.5875 0.42 ;
      RECT  1248.2875 0.14 1248.5375 0.42 ;
      RECT  1249.2375 0.14 1250.4075 0.42 ;
      RECT  1251.1075 0.14 1251.3975 0.42 ;
      RECT  1252.0975 0.14 1253.2275 0.42 ;
      RECT  1253.9275 0.14 1254.2575 0.42 ;
      RECT  1254.9575 0.14 1256.0475 0.42 ;
      RECT  1256.7475 0.14 1257.1175 0.42 ;
      RECT  1257.8175 0.14 1258.8675 0.42 ;
      RECT  1259.5675 0.14 1259.9775 0.42 ;
      RECT  1260.6775 0.14 1261.6875 0.42 ;
      RECT  1262.3875 0.14 1262.8375 0.42 ;
      RECT  1263.5375 0.14 1264.5075 0.42 ;
      RECT  1265.2075 0.14 1265.6975 0.42 ;
      RECT  1266.3975 0.14 1267.3275 0.42 ;
      RECT  1268.0275 0.14 1268.5575 0.42 ;
      RECT  1269.2575 0.14 1270.1475 0.42 ;
      RECT  1270.8475 0.14 1271.4175 0.42 ;
      RECT  1272.1175 0.14 1272.9675 0.42 ;
      RECT  1273.6675 0.14 1274.2775 0.42 ;
      RECT  1274.9775 0.14 1275.7875 0.42 ;
      RECT  1276.4875 0.14 1277.1375 0.42 ;
      RECT  1277.8375 0.14 1278.6075 0.42 ;
      RECT  1279.3075 0.14 1279.9975 0.42 ;
      RECT  1280.6975 0.14 1281.4275 0.42 ;
      RECT  1282.1275 0.14 1282.8575 0.42 ;
      RECT  1283.5575 0.14 1284.2475 0.42 ;
      RECT  1284.9475 0.14 1285.7175 0.42 ;
      RECT  1286.4175 0.14 1287.0675 0.42 ;
      RECT  1287.7675 0.14 1288.5775 0.42 ;
      RECT  1289.2775 0.14 1289.8875 0.42 ;
      RECT  1290.5875 0.14 1291.4375 0.42 ;
      RECT  1292.1375 0.14 1292.7075 0.42 ;
      RECT  1293.4075 0.14 1294.2975 0.42 ;
      RECT  1294.9975 0.14 1295.5275 0.42 ;
      RECT  1296.2275 0.14 1297.1575 0.42 ;
      RECT  1297.8575 0.14 1298.3475 0.42 ;
      RECT  1299.0475 0.14 1300.0175 0.42 ;
      RECT  1300.7175 0.14 1301.1675 0.42 ;
      RECT  1301.8675 0.14 1302.8775 0.42 ;
      RECT  1303.5775 0.14 1303.9875 0.42 ;
      RECT  1304.6875 0.14 1305.7375 0.42 ;
      RECT  1306.4375 0.14 1306.8075 0.42 ;
      RECT  1307.5075 0.14 1308.5975 0.42 ;
      RECT  1309.2975 0.14 1309.6275 0.42 ;
      RECT  1310.3275 0.14 1311.4575 0.42 ;
      RECT  1312.1575 0.14 1312.4475 0.42 ;
      RECT  1313.1475 0.14 1314.3175 0.42 ;
      RECT  1315.0175 0.14 1315.2675 0.42 ;
      RECT  1315.9675 0.14 1317.1775 0.42 ;
      RECT  1317.8775 0.14 1318.0875 0.42 ;
      RECT  1318.7875 0.14 1320.0375 0.42 ;
      RECT  1320.7375 0.14 1320.9075 0.42 ;
      RECT  1321.6075 0.14 1322.8975 0.42 ;
      RECT  1323.5975 0.14 1323.7275 0.42 ;
      RECT  1324.4275 0.14 1325.7575 0.42 ;
      RECT  1326.4575 0.14 1326.5475 0.42 ;
      RECT  1327.2475 0.14 1328.6175 0.42 ;
      RECT  1329.3175 0.14 1329.3675 0.42 ;
      RECT  1330.0675 0.14 1331.4775 0.42 ;
      RECT  1332.1775 0.14 1332.1875 0.42 ;
      RECT  1332.8875 0.14 1334.3375 0.42 ;
      RECT  1335.7075 0.14 1337.1975 0.42 ;
      RECT  1338.5275 0.14 1340.0575 0.42 ;
      RECT  1341.3475 0.14 1342.9175 0.42 ;
      RECT  1344.1675 0.14 1345.7775 0.42 ;
      RECT  1346.9875 0.14 1348.6375 0.42 ;
      RECT  1349.8075 0.14 1351.4975 0.42 ;
      RECT  1352.6275 0.14 1354.3575 0.42 ;
      RECT  1355.4475 0.14 1357.2175 0.42 ;
      RECT  1358.2675 0.14 1360.0775 0.42 ;
      RECT  1361.0875 0.14 1362.9375 0.42 ;
      RECT  1363.9225 0.14 1365.7975 0.42 ;
      RECT  1366.8 0.14 1368.6575 0.42 ;
      RECT  1369.6425 0.14 1371.5175 0.42 ;
      RECT  1372.5025 0.14 1374.3775 0.42 ;
      RECT  1375.3625 0.14 1377.2375 0.42 ;
      RECT  1378.2225 0.14 1380.0975 0.42 ;
      RECT  1381.0825 0.14 1382.9575 0.42 ;
      RECT  1383.9425 0.14 1385.8175 0.42 ;
      RECT  1386.8025 0.14 1388.6775 0.42 ;
      RECT  1389.86 0.14 1391.5375 0.42 ;
      RECT  1392.68 0.14 1394.3975 0.42 ;
      RECT  1395.5 0.14 1396.5 0.42 ;
      RECT  1397.2 0.14 1397.2575 0.42 ;
      RECT  1397.9575 0.14 1399.36 0.42 ;
      RECT  1400.06 0.14 1400.1175 0.42 ;
      RECT  1400.8175 0.14 1402.22 0.42 ;
      RECT  1402.92 0.14 1402.9775 0.42 ;
      RECT  1403.6775 0.14 1405.08 0.42 ;
      RECT  1405.78 0.14 1405.8375 0.42 ;
      RECT  1406.5375 0.14 1407.94 0.42 ;
      RECT  1408.64 0.14 1408.6975 0.42 ;
      RECT  1409.3975 0.14 1410.8 0.42 ;
      RECT  1411.5 0.14 1411.5575 0.42 ;
      RECT  1412.2575 0.14 1413.66 0.42 ;
      RECT  1414.36 0.14 1414.4175 0.42 ;
      RECT  1415.1175 0.14 1416.52 0.42 ;
      RECT  1417.22 0.14 1417.2775 0.42 ;
      RECT  1417.9775 0.14 1419.3725 0.42 ;
      RECT  1420.0725 0.14 1420.1375 0.42 ;
      RECT  1420.8375 0.14 1422.1925 0.42 ;
      RECT  1422.8925 0.14 1422.9975 0.42 ;
      RECT  1423.6975 0.14 1425.0125 0.42 ;
      RECT  1425.7125 0.14 1425.8575 0.42 ;
      RECT  1426.5575 0.14 1427.96 0.42 ;
      RECT  1428.66 0.14 1428.7175 0.42 ;
      RECT  1429.4175 0.14 1430.82 0.42 ;
      RECT  1431.52 0.14 1431.5775 0.42 ;
      RECT  1432.2775 0.14 1433.68 0.42 ;
      RECT  1434.38 0.14 1434.4375 0.42 ;
      RECT  1435.1375 0.14 1436.5275 0.42 ;
      RECT  1437.2275 0.14 1437.2975 0.42 ;
      RECT  1437.9975 0.14 1439.3475 0.42 ;
      RECT  1440.0475 0.14 1440.1575 0.42 ;
      RECT  1440.8575 0.14 1442.1675 0.42 ;
      RECT  1442.8675 0.14 1443.0175 0.42 ;
      RECT  1443.7175 0.14 1444.9875 0.42 ;
      RECT  1445.6875 0.14 1445.8775 0.42 ;
      RECT  1446.5775 0.14 1447.8075 0.42 ;
      RECT  1448.5075 0.14 1448.7375 0.42 ;
      RECT  1449.4375 0.14 1450.6275 0.42 ;
      RECT  1451.3275 0.14 1451.5975 0.42 ;
      RECT  1452.2975 0.14 1453.4475 0.42 ;
      RECT  1454.1475 0.14 1454.4575 0.42 ;
      RECT  1455.1575 0.14 1456.2675 0.42 ;
      RECT  1456.9675 0.14 1457.3175 0.42 ;
      RECT  1458.0175 0.14 1459.0875 0.42 ;
      RECT  1459.7875 0.14 1460.1775 0.42 ;
      RECT  1460.8775 0.14 1461.9075 0.42 ;
      RECT  1462.6075 0.14 1463.0375 0.42 ;
      RECT  1463.7375 0.14 1464.7275 0.42 ;
      RECT  1465.4275 0.14 1465.8975 0.42 ;
      RECT  1466.5975 0.14 1467.5475 0.42 ;
      RECT  1468.2475 0.14 1468.7575 0.42 ;
      RECT  1469.4575 0.14 1470.3675 0.42 ;
      RECT  1471.0675 0.14 1471.6175 0.42 ;
      RECT  1472.3175 0.14 1473.1875 0.42 ;
      RECT  1473.8875 0.14 1474.4775 0.42 ;
      RECT  1475.1775 0.14 1476.0075 0.42 ;
      RECT  1476.7075 0.14 1477.3375 0.42 ;
      RECT  1478.0375 0.14 1478.8275 0.42 ;
      RECT  1479.5275 0.14 1480.1975 0.42 ;
      RECT  1480.8975 0.14 1481.6475 0.42 ;
      RECT  1482.3475 0.14 1483.0575 0.42 ;
      RECT  1483.7575 0.14 1484.4675 0.42 ;
      RECT  1485.1675 0.14 1485.9175 0.42 ;
      RECT  1486.6175 0.14 1487.2875 0.42 ;
      RECT  1487.9875 0.14 1488.7775 0.42 ;
      RECT  1489.4775 0.14 1490.1075 0.42 ;
      RECT  1490.8075 0.14 1491.6375 0.42 ;
      RECT  1492.3375 0.14 1492.9275 0.42 ;
      RECT  1493.6275 0.14 1494.4975 0.42 ;
      RECT  1495.1975 0.14 1495.7475 0.42 ;
      RECT  1496.4475 0.14 1497.3575 0.42 ;
      RECT  1498.0575 0.14 1498.5675 0.42 ;
      RECT  1499.2675 0.14 1500.2175 0.42 ;
      RECT  1500.9175 0.14 1501.3875 0.42 ;
      RECT  1502.0875 0.14 1503.0775 0.42 ;
      RECT  1503.7775 0.14 1504.2075 0.42 ;
      RECT  1504.9075 0.14 1505.9375 0.42 ;
      RECT  1506.6375 0.14 1507.0275 0.42 ;
      RECT  1507.7275 0.14 1508.7975 0.42 ;
      RECT  1509.4975 0.14 1509.8475 0.42 ;
      RECT  1510.5475 0.14 1511.6575 0.42 ;
      RECT  1512.3575 0.14 1512.6675 0.42 ;
      RECT  1513.3675 0.14 1514.5175 0.42 ;
      RECT  1515.2175 0.14 1515.4875 0.42 ;
      RECT  1516.1875 0.14 1517.3775 0.42 ;
      RECT  1518.0775 0.14 1518.3075 0.42 ;
      RECT  1519.0075 0.14 1520.2375 0.42 ;
      RECT  1520.9375 0.14 1521.1275 0.42 ;
      RECT  1521.8275 0.14 1523.0975 0.42 ;
      RECT  1523.7975 0.14 1523.9475 0.42 ;
      RECT  1524.6475 0.14 1525.9575 0.42 ;
      RECT  1526.6575 0.14 1526.7675 0.42 ;
      RECT  1527.4675 0.14 1528.8175 0.42 ;
      RECT  1529.5175 0.14 1529.5875 0.42 ;
      RECT  1530.2875 0.14 1531.6775 0.42 ;
      RECT  1532.3775 0.14 1532.4075 0.42 ;
      RECT  1533.1075 0.14 1534.5375 0.42 ;
      RECT  1535.9275 0.14 1537.3975 0.42 ;
      RECT  1538.7475 0.14 1540.2575 0.42 ;
      RECT  1541.5675 0.14 1543.1175 0.42 ;
      RECT  1544.3875 0.14 1545.9775 0.42 ;
      RECT  1547.2075 0.14 1548.8375 0.42 ;
      RECT  1550.0275 0.14 1551.6975 0.42 ;
      RECT  1552.8475 0.14 1554.5575 0.42 ;
      RECT  1555.6675 0.14 1557.4175 0.42 ;
      RECT  1558.4875 0.14 1560.2775 0.42 ;
      RECT  1561.3075 0.14 1563.1375 0.42 ;
      RECT  1564.1275 0.14 1565.9975 0.42 ;
      RECT  1566.9825 0.14 1568.8575 0.42 ;
      RECT  1569.8425 0.14 1571.7175 0.42 ;
      RECT  1572.7025 0.14 1574.5775 0.42 ;
      RECT  1575.5625 0.14 1577.4375 0.42 ;
      RECT  1578.4225 0.14 1580.2975 0.42 ;
      RECT  1581.2825 0.14 1583.1575 0.42 ;
      RECT  1584.1425 0.14 1586.0175 0.42 ;
      RECT  1587.0025 0.14 1588.8775 0.42 ;
      RECT  1589.8625 0.14 1591.7375 0.42 ;
      RECT  1592.9 0.14 1594.5975 0.42 ;
      RECT  1595.72 0.14 1597.27 0.42 ;
      RECT  1597.97 0.14 1600.0875 0.42 ;
      RECT  1600.7875 0.14 1602.9075 0.42 ;
      RECT  1603.6075 0.14 1605.7275 0.42 ;
      RECT  1606.4275 0.14 1608.5475 0.42 ;
      RECT  1609.2475 0.14 1611.3675 0.42 ;
      RECT  1612.0675 0.14 1614.1875 0.42 ;
      RECT  1614.8875 0.14 1617.0075 0.42 ;
      RECT  1617.7075 0.14 1619.8275 0.42 ;
      RECT  1620.5275 0.14 1622.6475 0.42 ;
      RECT  1623.3475 0.14 1625.4675 0.42 ;
      RECT  1626.1675 0.14 1628.2875 0.42 ;
      RECT  1628.9875 0.14 1631.1075 0.42 ;
      RECT  1631.8075 0.14 1633.9275 0.42 ;
      RECT  1634.6275 0.14 1636.7475 0.42 ;
      RECT  1637.4475 0.14 1639.5675 0.42 ;
      RECT  1640.2675 0.14 1642.3875 0.42 ;
      RECT  1643.0875 0.14 1645.2075 0.42 ;
      RECT  1645.9075 0.14 1648.0275 0.42 ;
      RECT  1648.7275 0.14 1650.8475 0.42 ;
      RECT  1651.5475 0.14 1653.6675 0.42 ;
      RECT  1654.3675 0.14 1656.4875 0.42 ;
      RECT  1657.1875 0.14 1659.3075 0.42 ;
      RECT  1660.0075 0.14 1662.1275 0.42 ;
      RECT  1662.8275 0.14 1664.9475 0.42 ;
      RECT  1665.6475 0.14 1667.7675 0.42 ;
      RECT  1668.4675 0.14 1691.39 0.42 ;
      RECT  0.98 0.14 120.845 0.42 ;
      RECT  133.8375 0.42 1689.99 1.12 ;
      RECT  133.8375 1.12 1689.99 739.635 ;
      RECT  133.8375 739.635 1689.99 740.615 ;
      RECT  1689.99 0.42 1691.25 1.12 ;
      RECT  1689.99 739.635 1691.25 740.615 ;
      RECT  1691.25 0.42 1691.39 1.12 ;
      RECT  1691.25 1.12 1691.39 739.635 ;
      RECT  1691.25 739.635 1691.39 740.615 ;
      RECT  0.98 0.42 1.12 1.12 ;
      RECT  0.98 1.12 1.12 739.635 ;
      RECT  0.98 739.635 1.12 740.615 ;
      RECT  1.12 0.42 2.38 1.12 ;
      RECT  1.12 739.635 2.38 740.615 ;
      RECT  2.38 0.42 133.1375 1.12 ;
      RECT  2.38 1.12 133.1375 739.635 ;
      RECT  2.38 739.635 133.1375 740.615 ;
   END
END    sram_512b_2048_1rw_freepdk45
END    LIBRARY
